VERSION 5.7 ;
  NOWIREEXTENSIONATPIN ON ;
  DIVIDERCHAR "/" ;
  BUSBITCHARS "[]" ;
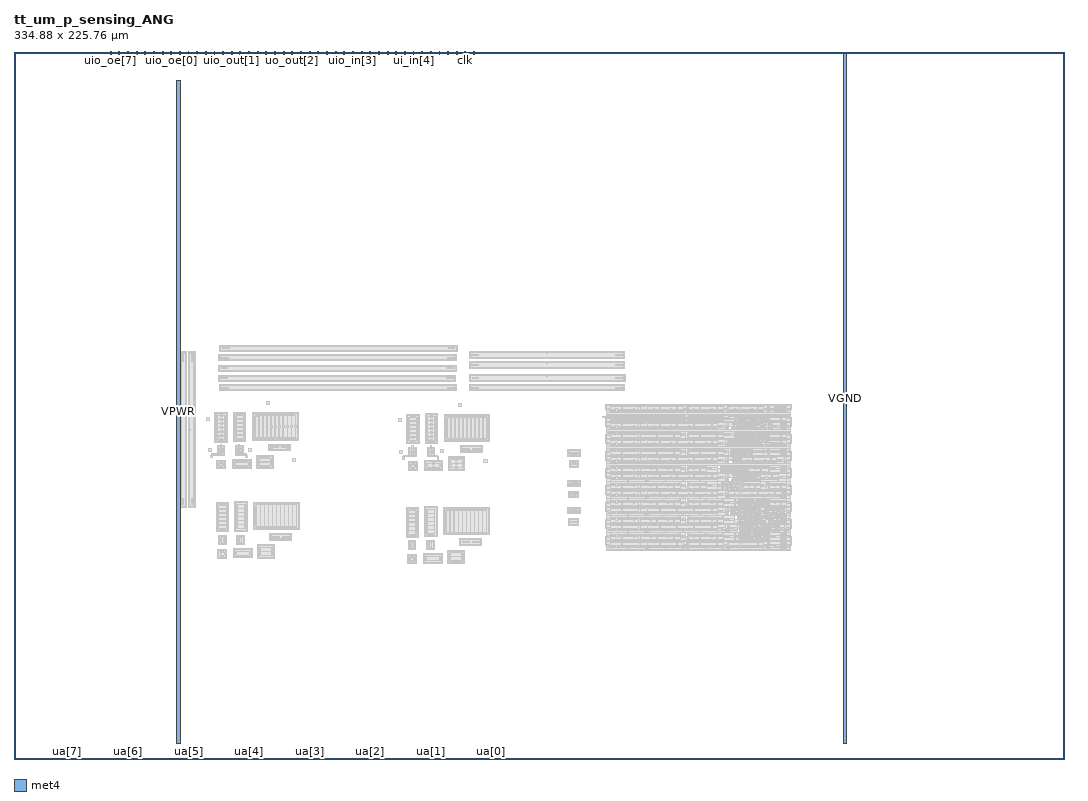
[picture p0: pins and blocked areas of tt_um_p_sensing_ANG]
MACRO tt_um_p_sensing_ANG
  CLASS BLOCK ;
  FOREIGN tt_um_p_sensing_ANG ;
  ORIGIN 0.000 0.000 ;
  SIZE 334.880 BY 225.760 ;
  PIN clk
    DIRECTION INPUT ;
    USE SIGNAL ;
    ANTENNAGATEAREA 0.852000 ;
    PORT
      LAYER met4 ;
        RECT 143.830 224.760 144.130 225.760 ;
    END
  END clk
  PIN ena
    DIRECTION INPUT ;
    USE SIGNAL ;
    PORT
      LAYER met4 ;
        RECT 146.590 224.760 146.890 225.760 ;
    END
  END ena
  PIN rst_n
    DIRECTION INPUT ;
    USE SIGNAL ;
    ANTENNAGATEAREA 0.159000 ;
    PORT
      LAYER met4 ;
        RECT 141.070 224.760 141.370 225.760 ;
    END
  END rst_n
  PIN ua[0]
    DIRECTION INOUT ;
    USE SIGNAL ;
    ANTENNAGATEAREA 0.500000 ;
    PORT
      LAYER met4 ;
        RECT 151.810 0.000 152.710 1.000 ;
    END
  END ua[0]
  PIN ua[1]
    DIRECTION INOUT ;
    USE SIGNAL ;
    ANTENNAGATEAREA 0.500000 ;
    ANTENNADIFFAREA 14.065000 ;
    PORT
      LAYER met4 ;
        RECT 132.490 0.000 133.390 1.000 ;
    END
  END ua[1]
  PIN ua[2]
    DIRECTION INOUT ;
    USE SIGNAL ;
    ANTENNADIFFAREA 13.195000 ;
    PORT
      LAYER met4 ;
        RECT 113.170 0.000 114.070 1.000 ;
    END
  END ua[2]
  PIN ua[3]
    DIRECTION INOUT ;
    USE SIGNAL ;
    ANTENNAGATEAREA 44.079998 ;
    ANTENNADIFFAREA 0.754000 ;
    PORT
      LAYER met4 ;
        RECT 93.850 0.000 94.750 1.000 ;
    END
  END ua[3]
  PIN ua[4]
    DIRECTION INOUT ;
    USE SIGNAL ;
    ANTENNAGATEAREA 0.500000 ;
    PORT
      LAYER met4 ;
        RECT 74.530 0.000 75.430 1.000 ;
    END
  END ua[4]
  PIN ua[5]
    DIRECTION INOUT ;
    USE SIGNAL ;
    ANTENNADIFFAREA 0.445500 ;
    PORT
      LAYER met4 ;
        RECT 55.210 0.000 56.110 1.000 ;
    END
  END ua[5]
  PIN ua[6]
    DIRECTION INOUT ;
    USE SIGNAL ;
    PORT
      LAYER met4 ;
        RECT 35.890 0.000 36.790 1.000 ;
    END
  END ua[6]
  PIN ua[7]
    DIRECTION INOUT ;
    USE SIGNAL ;
    PORT
      LAYER met4 ;
        RECT 16.570 0.000 17.470 1.000 ;
    END
  END ua[7]
  PIN ui_in[0]
    DIRECTION INPUT ;
    USE SIGNAL ;
    PORT
      LAYER met4 ;
        RECT 138.310 224.760 138.610 225.760 ;
    END
  END ui_in[0]
  PIN ui_in[1]
    DIRECTION INPUT ;
    USE SIGNAL ;
    PORT
      LAYER met4 ;
        RECT 135.550 224.760 135.850 225.760 ;
    END
  END ui_in[1]
  PIN ui_in[2]
    DIRECTION INPUT ;
    USE SIGNAL ;
    PORT
      LAYER met4 ;
        RECT 132.790 224.760 133.090 225.760 ;
    END
  END ui_in[2]
  PIN ui_in[3]
    DIRECTION INPUT ;
    USE SIGNAL ;
    PORT
      LAYER met4 ;
        RECT 130.030 224.760 130.330 225.760 ;
    END
  END ui_in[3]
  PIN ui_in[4]
    DIRECTION INPUT ;
    USE SIGNAL ;
    PORT
      LAYER met4 ;
        RECT 127.270 224.760 127.570 225.760 ;
    END
  END ui_in[4]
  PIN ui_in[5]
    DIRECTION INPUT ;
    USE SIGNAL ;
    PORT
      LAYER met4 ;
        RECT 124.510 224.760 124.810 225.760 ;
    END
  END ui_in[5]
  PIN ui_in[6]
    DIRECTION INPUT ;
    USE SIGNAL ;
    PORT
      LAYER met4 ;
        RECT 121.750 224.760 122.050 225.760 ;
    END
  END ui_in[6]
  PIN ui_in[7]
    DIRECTION INPUT ;
    USE SIGNAL ;
    PORT
      LAYER met4 ;
        RECT 118.990 224.760 119.290 225.760 ;
    END
  END ui_in[7]
  PIN uio_in[0]
    DIRECTION INPUT ;
    USE SIGNAL ;
    PORT
      LAYER met4 ;
        RECT 116.230 224.760 116.530 225.760 ;
    END
  END uio_in[0]
  PIN uio_in[1]
    DIRECTION INPUT ;
    USE SIGNAL ;
    PORT
      LAYER met4 ;
        RECT 113.470 224.760 113.770 225.760 ;
    END
  END uio_in[1]
  PIN uio_in[2]
    DIRECTION INPUT ;
    USE SIGNAL ;
    PORT
      LAYER met4 ;
        RECT 110.710 224.760 111.010 225.760 ;
    END
  END uio_in[2]
  PIN uio_in[3]
    DIRECTION INPUT ;
    USE SIGNAL ;
    PORT
      LAYER met4 ;
        RECT 107.950 224.760 108.250 225.760 ;
    END
  END uio_in[3]
  PIN uio_in[4]
    DIRECTION INPUT ;
    USE SIGNAL ;
    PORT
      LAYER met4 ;
        RECT 105.190 224.760 105.490 225.760 ;
    END
  END uio_in[4]
  PIN uio_in[5]
    DIRECTION INPUT ;
    USE SIGNAL ;
    PORT
      LAYER met4 ;
        RECT 102.430 224.760 102.730 225.760 ;
    END
  END uio_in[5]
  PIN uio_in[6]
    DIRECTION INPUT ;
    USE SIGNAL ;
    PORT
      LAYER met4 ;
        RECT 99.670 224.760 99.970 225.760 ;
    END
  END uio_in[6]
  PIN uio_in[7]
    DIRECTION INPUT ;
    USE SIGNAL ;
    PORT
      LAYER met4 ;
        RECT 96.910 224.760 97.210 225.760 ;
    END
  END uio_in[7]
  PIN uio_oe[0]
    DIRECTION OUTPUT ;
    USE SIGNAL ;
    ANTENNAGATEAREA 564.151489 ;
    ANTENNADIFFAREA 378.463593 ;
    PORT
      LAYER met4 ;
        RECT 49.990 224.760 50.290 225.760 ;
    END
  END uio_oe[0]
  PIN uio_oe[1]
    DIRECTION OUTPUT ;
    USE SIGNAL ;
    PORT
      LAYER met4 ;
        RECT 47.230 224.760 47.530 225.760 ;
    END
  END uio_oe[1]
  PIN uio_oe[2]
    DIRECTION OUTPUT ;
    USE SIGNAL ;
    PORT
      LAYER met4 ;
        RECT 44.470 224.760 44.770 225.760 ;
    END
  END uio_oe[2]
  PIN uio_oe[3]
    DIRECTION OUTPUT ;
    USE SIGNAL ;
    PORT
      LAYER met4 ;
        RECT 41.710 224.760 42.010 225.760 ;
    END
  END uio_oe[3]
  PIN uio_oe[4]
    DIRECTION OUTPUT ;
    USE SIGNAL ;
    PORT
      LAYER met4 ;
        RECT 38.950 224.760 39.250 225.760 ;
    END
  END uio_oe[4]
  PIN uio_oe[5]
    DIRECTION OUTPUT ;
    USE SIGNAL ;
    PORT
      LAYER met4 ;
        RECT 36.190 224.760 36.490 225.760 ;
    END
  END uio_oe[5]
  PIN uio_oe[6]
    DIRECTION OUTPUT ;
    USE SIGNAL ;
    PORT
      LAYER met4 ;
        RECT 33.430 224.760 33.730 225.760 ;
    END
  END uio_oe[6]
  PIN uio_oe[7]
    DIRECTION OUTPUT ;
    USE SIGNAL ;
    PORT
      LAYER met4 ;
        RECT 30.670 224.760 30.970 225.760 ;
    END
  END uio_oe[7]
  PIN uio_out[0]
    DIRECTION OUTPUT ;
    USE SIGNAL ;
    ANTENNAGATEAREA 564.151489 ;
    ANTENNADIFFAREA 378.463593 ;
    PORT
      LAYER met4 ;
        RECT 72.070 224.760 72.370 225.760 ;
    END
  END uio_out[0]
  PIN uio_out[1]
    DIRECTION OUTPUT ;
    USE SIGNAL ;
    PORT
      LAYER met4 ;
        RECT 69.310 224.760 69.610 225.760 ;
    END
  END uio_out[1]
  PIN uio_out[2]
    DIRECTION OUTPUT ;
    USE SIGNAL ;
    PORT
      LAYER met4 ;
        RECT 66.550 224.760 66.850 225.760 ;
    END
  END uio_out[2]
  PIN uio_out[3]
    DIRECTION OUTPUT ;
    USE SIGNAL ;
    PORT
      LAYER met4 ;
        RECT 63.790 224.760 64.090 225.760 ;
    END
  END uio_out[3]
  PIN uio_out[4]
    DIRECTION OUTPUT ;
    USE SIGNAL ;
    PORT
      LAYER met4 ;
        RECT 61.030 224.760 61.330 225.760 ;
    END
  END uio_out[4]
  PIN uio_out[5]
    DIRECTION OUTPUT ;
    USE SIGNAL ;
    PORT
      LAYER met4 ;
        RECT 58.270 224.760 58.570 225.760 ;
    END
  END uio_out[5]
  PIN uio_out[6]
    DIRECTION OUTPUT ;
    USE SIGNAL ;
    PORT
      LAYER met4 ;
        RECT 55.510 224.760 55.810 225.760 ;
    END
  END uio_out[6]
  PIN uio_out[7]
    DIRECTION OUTPUT ;
    USE SIGNAL ;
    PORT
      LAYER met4 ;
        RECT 52.750 224.760 53.050 225.760 ;
    END
  END uio_out[7]
  PIN uo_out[0]
    DIRECTION OUTPUT ;
    USE SIGNAL ;
    ANTENNAGATEAREA 564.151489 ;
    ANTENNADIFFAREA 378.463593 ;
    PORT
      LAYER met4 ;
        RECT 94.150 224.760 94.450 225.760 ;
    END
  END uo_out[0]
  PIN uo_out[1]
    DIRECTION OUTPUT ;
    USE SIGNAL ;
    ANTENNAGATEAREA 564.151489 ;
    ANTENNADIFFAREA 378.463593 ;
    PORT
      LAYER met4 ;
        RECT 91.390 224.760 91.690 225.760 ;
    END
  END uo_out[1]
  PIN uo_out[2]
    DIRECTION OUTPUT ;
    USE SIGNAL ;
    PORT
      LAYER met4 ;
        RECT 88.630 224.760 88.930 225.760 ;
    END
  END uo_out[2]
  PIN uo_out[3]
    DIRECTION OUTPUT ;
    USE SIGNAL ;
    PORT
      LAYER met4 ;
        RECT 85.870 224.760 86.170 225.760 ;
    END
  END uo_out[3]
  PIN uo_out[4]
    DIRECTION OUTPUT ;
    USE SIGNAL ;
    PORT
      LAYER met4 ;
        RECT 83.110 224.760 83.410 225.760 ;
    END
  END uo_out[4]
  PIN uo_out[5]
    DIRECTION OUTPUT ;
    USE SIGNAL ;
    PORT
      LAYER met4 ;
        RECT 80.350 224.760 80.650 225.760 ;
    END
  END uo_out[5]
  PIN uo_out[6]
    DIRECTION OUTPUT ;
    USE SIGNAL ;
    PORT
      LAYER met4 ;
        RECT 77.590 224.760 77.890 225.760 ;
    END
  END uo_out[6]
  PIN uo_out[7]
    DIRECTION OUTPUT ;
    USE SIGNAL ;
    PORT
      LAYER met4 ;
        RECT 74.830 224.760 75.130 225.760 ;
    END
  END uo_out[7]
  PIN VPWR
    DIRECTION INOUT ;
    USE POWER ;
    PORT
      LAYER met4 ;
        RECT 51.900 5.000 53.100 216.500 ;
    END
  END VPWR
  PIN VGND
    DIRECTION INOUT ;
    USE GROUND ;
    PORT
      LAYER met4 ;
        RECT 264.400 5.000 265.600 225.000 ;
    END
  END VGND
  OBS
      LAYER pwell ;
        RECT 65.610 129.960 141.430 131.970 ;
        RECT 52.995 80.190 55.005 129.810 ;
        RECT 55.745 80.190 57.755 129.810 ;
        RECT 65.370 127.010 141.190 129.020 ;
        RECT 145.150 127.840 194.770 129.850 ;
        RECT 65.250 123.590 141.070 125.600 ;
        RECT 145.150 124.650 194.770 126.660 ;
        RECT 65.140 120.400 140.960 122.410 ;
        RECT 145.270 120.520 194.890 122.530 ;
        RECT 65.440 117.430 141.260 119.440 ;
        RECT 145.150 117.450 194.770 119.460 ;
      LAYER nwell ;
        RECT 188.740 111.565 248.000 113.170 ;
        RECT 64.100 100.980 68.120 110.390 ;
        RECT 69.970 101.180 73.990 110.590 ;
        RECT 76.040 101.710 90.610 110.400 ;
      LAYER pwell ;
        RECT 188.935 110.365 190.305 111.175 ;
        RECT 190.315 110.365 195.825 111.175 ;
        RECT 195.835 110.365 201.345 111.175 ;
        RECT 201.825 110.450 202.255 111.235 ;
        RECT 202.275 110.365 207.785 111.175 ;
        RECT 207.795 110.365 213.305 111.175 ;
        RECT 213.315 110.365 214.685 111.175 ;
        RECT 214.705 110.450 215.135 111.235 ;
        RECT 215.155 110.365 220.665 111.175 ;
        RECT 220.675 110.365 226.185 111.175 ;
        RECT 226.195 110.365 227.565 111.175 ;
        RECT 227.585 110.450 228.015 111.235 ;
        RECT 228.035 110.365 233.545 111.175 ;
        RECT 233.555 110.365 239.065 111.175 ;
        RECT 239.075 110.365 240.445 111.175 ;
        RECT 240.465 110.450 240.895 111.235 ;
        RECT 240.915 110.365 242.745 111.175 ;
        RECT 243.240 111.045 244.585 111.275 ;
        RECT 245.080 111.045 246.425 111.275 ;
        RECT 242.755 110.365 244.585 111.045 ;
        RECT 244.595 110.365 246.425 111.045 ;
        RECT 246.435 110.365 247.805 111.175 ;
        RECT 189.075 110.155 189.245 110.365 ;
        RECT 190.455 110.155 190.625 110.365 ;
        RECT 192.295 110.155 192.465 110.345 ;
        RECT 195.975 110.175 196.145 110.365 ;
        RECT 197.815 110.155 197.985 110.345 ;
        RECT 201.490 110.205 201.610 110.315 ;
        RECT 202.415 110.175 202.585 110.365 ;
        RECT 203.335 110.155 203.505 110.345 ;
        RECT 207.935 110.175 208.105 110.365 ;
        RECT 208.855 110.155 209.025 110.345 ;
        RECT 213.455 110.175 213.625 110.365 ;
        RECT 214.370 110.205 214.490 110.315 ;
        RECT 215.295 110.155 215.465 110.365 ;
        RECT 220.815 110.155 220.985 110.365 ;
        RECT 226.335 110.155 226.505 110.365 ;
        RECT 228.175 110.175 228.345 110.365 ;
        RECT 230.015 110.155 230.185 110.345 ;
        RECT 233.695 110.175 233.865 110.365 ;
        RECT 239.215 110.175 239.385 110.365 ;
        RECT 240.135 110.155 240.305 110.345 ;
        RECT 241.055 110.155 241.225 110.365 ;
        RECT 242.895 110.175 243.065 110.365 ;
        RECT 244.735 110.175 244.905 110.365 ;
        RECT 247.495 110.155 247.665 110.365 ;
      LAYER nwell ;
        RECT 125.240 100.500 129.260 109.910 ;
        RECT 131.110 100.700 135.130 110.110 ;
        RECT 137.180 101.230 151.750 109.920 ;
      LAYER pwell ;
        RECT 188.935 109.345 190.305 110.155 ;
        RECT 190.315 109.475 192.145 110.155 ;
        RECT 190.800 109.245 192.145 109.475 ;
        RECT 192.155 109.345 197.665 110.155 ;
        RECT 197.675 109.345 203.185 110.155 ;
        RECT 203.195 109.345 208.705 110.155 ;
        RECT 208.715 109.345 214.225 110.155 ;
        RECT 214.705 109.285 215.135 110.070 ;
        RECT 215.155 109.345 220.665 110.155 ;
        RECT 220.675 109.345 226.185 110.155 ;
        RECT 226.195 109.345 229.865 110.155 ;
        RECT 229.875 109.345 231.245 110.155 ;
        RECT 231.255 109.475 240.445 110.155 ;
        RECT 231.255 109.245 232.175 109.475 ;
        RECT 235.005 109.255 235.935 109.475 ;
        RECT 240.465 109.285 240.895 110.070 ;
        RECT 240.915 109.345 246.425 110.155 ;
        RECT 246.435 109.345 247.805 110.155 ;
      LAYER nwell ;
        RECT 188.740 106.125 248.000 108.955 ;
      LAYER pwell ;
        RECT 188.935 104.925 190.305 105.735 ;
        RECT 190.315 104.925 195.825 105.735 ;
        RECT 195.835 104.925 201.345 105.735 ;
        RECT 201.825 105.010 202.255 105.795 ;
        RECT 202.275 104.925 207.785 105.735 ;
        RECT 207.795 104.925 213.305 105.735 ;
        RECT 213.315 104.925 218.825 105.735 ;
        RECT 218.835 104.925 224.345 105.735 ;
        RECT 224.355 104.925 227.105 105.735 ;
        RECT 227.585 105.010 228.015 105.795 ;
        RECT 238.250 105.605 239.170 105.835 ;
        RECT 228.955 104.925 238.060 105.605 ;
        RECT 238.250 104.925 241.715 105.605 ;
        RECT 241.835 104.925 244.585 105.735 ;
        RECT 245.080 105.605 246.425 105.835 ;
        RECT 244.595 104.925 246.425 105.605 ;
        RECT 246.435 104.925 247.805 105.735 ;
        RECT 189.075 104.715 189.245 104.925 ;
        RECT 190.455 104.715 190.625 104.925 ;
        RECT 195.975 104.715 196.145 104.925 ;
        RECT 201.495 104.875 201.665 104.905 ;
        RECT 201.490 104.765 201.665 104.875 ;
        RECT 201.495 104.715 201.665 104.765 ;
        RECT 202.415 104.735 202.585 104.925 ;
        RECT 207.015 104.715 207.185 104.905 ;
        RECT 207.935 104.735 208.105 104.925 ;
        RECT 212.535 104.715 212.705 104.905 ;
        RECT 213.455 104.735 213.625 104.925 ;
        RECT 214.370 104.765 214.490 104.875 ;
        RECT 215.295 104.715 215.465 104.905 ;
        RECT 218.975 104.735 219.145 104.925 ;
        RECT 220.815 104.715 220.985 104.905 ;
        RECT 224.495 104.735 224.665 104.925 ;
        RECT 226.335 104.715 226.505 104.905 ;
        RECT 227.250 104.765 227.370 104.875 ;
        RECT 228.185 104.770 228.345 104.880 ;
        RECT 229.095 104.735 229.265 104.925 ;
        RECT 230.015 104.715 230.185 104.905 ;
        RECT 239.215 104.715 239.385 104.905 ;
        RECT 241.055 104.715 241.225 104.905 ;
        RECT 241.515 104.735 241.685 104.925 ;
        RECT 241.975 104.735 242.145 104.925 ;
        RECT 244.735 104.735 244.905 104.925 ;
        RECT 247.495 104.715 247.665 104.925 ;
        RECT 188.935 103.905 190.305 104.715 ;
        RECT 190.315 103.905 195.825 104.715 ;
        RECT 195.835 103.905 201.345 104.715 ;
        RECT 201.355 103.905 206.865 104.715 ;
        RECT 206.875 103.905 212.385 104.715 ;
        RECT 212.395 103.905 214.225 104.715 ;
        RECT 214.705 103.845 215.135 104.630 ;
        RECT 215.155 103.905 220.665 104.715 ;
        RECT 220.675 103.905 226.185 104.715 ;
        RECT 226.195 103.905 229.865 104.715 ;
        RECT 229.875 104.035 239.065 104.715 ;
        RECT 234.385 103.815 235.315 104.035 ;
        RECT 238.145 103.805 239.065 104.035 ;
        RECT 239.075 103.935 240.445 104.715 ;
        RECT 240.465 103.845 240.895 104.630 ;
        RECT 240.915 103.905 246.425 104.715 ;
        RECT 246.435 103.905 247.805 104.715 ;
      LAYER nwell ;
        RECT 188.740 100.685 248.000 103.515 ;
      LAYER pwell ;
        RECT 64.770 96.840 67.230 99.940 ;
        RECT 70.580 96.840 73.040 99.940 ;
        RECT 81.250 98.370 88.240 100.380 ;
        RECT 64.570 92.580 67.530 95.330 ;
        RECT 69.640 92.640 75.610 95.600 ;
        RECT 77.310 92.570 82.660 96.820 ;
        RECT 125.910 96.360 128.370 99.460 ;
        RECT 131.720 96.360 134.180 99.460 ;
        RECT 142.390 97.890 149.380 99.900 ;
        RECT 188.935 99.485 190.305 100.295 ;
        RECT 190.315 99.485 195.825 100.295 ;
        RECT 195.835 99.485 201.345 100.295 ;
        RECT 201.825 99.570 202.255 100.355 ;
        RECT 202.275 99.485 207.785 100.295 ;
        RECT 207.795 99.485 213.305 100.295 ;
        RECT 213.315 99.485 218.825 100.295 ;
        RECT 218.835 99.485 224.345 100.295 ;
        RECT 224.355 99.485 227.105 100.295 ;
        RECT 227.585 99.570 228.015 100.355 ;
        RECT 228.035 100.165 228.955 100.395 ;
        RECT 231.785 100.165 232.715 100.385 ;
        RECT 237.330 100.165 238.250 100.395 ;
        RECT 228.035 99.485 237.225 100.165 ;
        RECT 237.330 99.485 240.795 100.165 ;
        RECT 240.915 99.485 246.425 100.295 ;
        RECT 246.435 99.485 247.805 100.295 ;
        RECT 189.075 99.275 189.245 99.485 ;
        RECT 190.455 99.275 190.625 99.485 ;
        RECT 195.975 99.275 196.145 99.485 ;
        RECT 201.495 99.435 201.665 99.465 ;
        RECT 201.490 99.325 201.665 99.435 ;
        RECT 201.495 99.275 201.665 99.325 ;
        RECT 202.415 99.295 202.585 99.485 ;
        RECT 207.015 99.275 207.185 99.465 ;
        RECT 207.935 99.295 208.105 99.485 ;
        RECT 212.535 99.275 212.705 99.465 ;
        RECT 213.455 99.295 213.625 99.485 ;
        RECT 214.370 99.325 214.490 99.435 ;
        RECT 215.295 99.275 215.465 99.465 ;
        RECT 218.975 99.295 219.145 99.485 ;
        RECT 220.815 99.275 220.985 99.465 ;
        RECT 224.495 99.295 224.665 99.485 ;
        RECT 226.335 99.275 226.505 99.465 ;
        RECT 227.250 99.325 227.370 99.435 ;
        RECT 228.170 99.325 228.290 99.435 ;
        RECT 231.395 99.275 231.565 99.465 ;
        RECT 231.855 99.275 232.025 99.465 ;
        RECT 235.535 99.275 235.705 99.465 ;
        RECT 236.915 99.295 237.085 99.485 ;
        RECT 239.215 99.275 239.385 99.465 ;
        RECT 240.595 99.295 240.765 99.485 ;
        RECT 241.055 99.275 241.225 99.485 ;
        RECT 244.735 99.275 244.905 99.465 ;
        RECT 247.495 99.275 247.665 99.485 ;
      LAYER nwell ;
        RECT 176.540 96.490 180.730 98.600 ;
      LAYER pwell ;
        RECT 188.935 98.465 190.305 99.275 ;
        RECT 190.315 98.465 195.825 99.275 ;
        RECT 195.835 98.465 201.345 99.275 ;
        RECT 201.355 98.465 206.865 99.275 ;
        RECT 206.875 98.465 212.385 99.275 ;
        RECT 212.395 98.465 214.225 99.275 ;
        RECT 214.705 98.405 215.135 99.190 ;
        RECT 215.155 98.465 220.665 99.275 ;
        RECT 220.675 98.465 226.185 99.275 ;
        RECT 226.195 98.465 228.025 99.275 ;
        RECT 228.495 98.365 231.605 99.275 ;
        RECT 231.825 98.595 235.290 99.275 ;
        RECT 234.370 98.365 235.290 98.595 ;
        RECT 235.395 98.465 239.065 99.275 ;
        RECT 239.075 98.465 240.445 99.275 ;
        RECT 240.465 98.405 240.895 99.190 ;
        RECT 240.915 98.465 244.585 99.275 ;
        RECT 244.595 98.595 246.425 99.275 ;
        RECT 245.080 98.365 246.425 98.595 ;
        RECT 246.435 98.465 247.805 99.275 ;
        RECT 125.710 92.100 128.670 94.850 ;
        RECT 130.780 92.160 136.750 95.120 ;
        RECT 138.450 92.090 143.800 96.340 ;
      LAYER nwell ;
        RECT 188.740 95.245 248.000 98.075 ;
      LAYER pwell ;
        RECT 177.040 93.070 180.140 95.180 ;
        RECT 188.935 94.045 190.305 94.855 ;
        RECT 190.315 94.045 195.825 94.855 ;
        RECT 195.835 94.045 201.345 94.855 ;
        RECT 201.825 94.130 202.255 94.915 ;
        RECT 202.275 94.045 207.785 94.855 ;
        RECT 207.795 94.045 213.305 94.855 ;
        RECT 213.315 94.045 218.825 94.855 ;
        RECT 218.835 94.045 224.345 94.855 ;
        RECT 224.355 94.045 227.105 94.855 ;
        RECT 227.585 94.130 228.015 94.915 ;
        RECT 229.055 94.045 232.165 94.955 ;
        RECT 232.175 94.045 237.685 94.855 ;
        RECT 237.695 94.045 243.205 94.855 ;
        RECT 243.215 94.045 245.965 94.855 ;
        RECT 246.435 94.045 247.805 94.855 ;
        RECT 189.075 93.835 189.245 94.045 ;
        RECT 190.455 93.835 190.625 94.045 ;
        RECT 195.975 93.835 196.145 94.045 ;
        RECT 201.495 93.995 201.665 94.025 ;
        RECT 201.490 93.885 201.665 93.995 ;
        RECT 201.495 93.835 201.665 93.885 ;
        RECT 202.415 93.855 202.585 94.045 ;
        RECT 207.015 93.835 207.185 94.025 ;
        RECT 207.935 93.855 208.105 94.045 ;
        RECT 212.535 93.835 212.705 94.025 ;
        RECT 213.455 93.855 213.625 94.045 ;
        RECT 214.370 93.885 214.490 93.995 ;
        RECT 215.295 93.835 215.465 94.025 ;
        RECT 218.975 93.855 219.145 94.045 ;
        RECT 220.815 93.835 220.985 94.025 ;
        RECT 224.495 93.855 224.665 94.045 ;
        RECT 227.250 93.885 227.370 93.995 ;
        RECT 228.185 93.890 228.345 94.000 ;
        RECT 229.095 93.855 229.265 94.045 ;
        RECT 232.315 93.855 232.485 94.045 ;
        RECT 234.155 93.835 234.325 94.025 ;
        RECT 234.615 93.835 234.785 94.025 ;
        RECT 237.835 93.855 238.005 94.045 ;
        RECT 240.130 93.885 240.250 93.995 ;
        RECT 241.055 93.835 241.225 94.025 ;
        RECT 243.355 93.855 243.525 94.045 ;
        RECT 244.735 93.835 244.905 94.025 ;
        RECT 246.110 93.885 246.230 93.995 ;
        RECT 247.495 93.835 247.665 94.045 ;
        RECT 188.935 93.025 190.305 93.835 ;
        RECT 190.315 93.025 195.825 93.835 ;
        RECT 195.835 93.025 201.345 93.835 ;
        RECT 201.355 93.025 206.865 93.835 ;
        RECT 206.875 93.025 212.385 93.835 ;
        RECT 212.395 93.025 214.225 93.835 ;
        RECT 214.705 92.965 215.135 93.750 ;
        RECT 215.155 93.025 220.665 93.835 ;
        RECT 220.675 93.025 224.345 93.835 ;
        RECT 225.275 93.155 234.465 93.835 ;
        RECT 225.275 92.925 226.195 93.155 ;
        RECT 229.025 92.935 229.955 93.155 ;
        RECT 234.475 93.025 239.985 93.835 ;
        RECT 240.465 92.965 240.895 93.750 ;
        RECT 240.915 93.025 244.585 93.835 ;
        RECT 244.595 93.155 246.425 93.835 ;
        RECT 245.080 92.925 246.425 93.155 ;
        RECT 246.435 93.025 247.805 93.835 ;
      LAYER nwell ;
        RECT 188.740 89.805 248.000 92.635 ;
        RECT 176.580 86.750 180.770 88.860 ;
      LAYER pwell ;
        RECT 188.935 88.605 190.305 89.415 ;
        RECT 190.315 88.605 195.825 89.415 ;
        RECT 195.835 88.605 201.345 89.415 ;
        RECT 201.825 88.690 202.255 89.475 ;
        RECT 202.275 88.605 207.785 89.415 ;
        RECT 207.795 88.605 213.305 89.415 ;
        RECT 213.315 88.605 218.825 89.415 ;
        RECT 218.835 88.605 224.345 89.415 ;
        RECT 224.355 88.605 227.105 89.415 ;
        RECT 227.585 88.690 228.015 89.475 ;
        RECT 228.955 88.605 238.060 89.285 ;
        RECT 238.155 88.605 243.665 89.415 ;
        RECT 243.675 88.605 246.425 89.415 ;
        RECT 246.435 88.605 247.805 89.415 ;
        RECT 189.075 88.395 189.245 88.605 ;
        RECT 190.455 88.395 190.625 88.605 ;
        RECT 195.975 88.395 196.145 88.605 ;
        RECT 201.495 88.555 201.665 88.585 ;
        RECT 201.490 88.445 201.665 88.555 ;
        RECT 201.495 88.395 201.665 88.445 ;
        RECT 202.415 88.415 202.585 88.605 ;
        RECT 207.015 88.395 207.185 88.585 ;
        RECT 207.935 88.415 208.105 88.605 ;
        RECT 212.535 88.395 212.705 88.585 ;
        RECT 213.455 88.415 213.625 88.605 ;
        RECT 214.370 88.445 214.490 88.555 ;
        RECT 215.295 88.395 215.465 88.585 ;
        RECT 218.975 88.415 219.145 88.605 ;
        RECT 220.815 88.395 220.985 88.585 ;
        RECT 224.495 88.395 224.665 88.605 ;
        RECT 225.875 88.395 226.045 88.585 ;
        RECT 227.250 88.445 227.370 88.555 ;
        RECT 228.185 88.450 228.345 88.560 ;
        RECT 229.095 88.395 229.265 88.605 ;
        RECT 232.775 88.395 232.945 88.585 ;
        RECT 238.295 88.395 238.465 88.605 ;
        RECT 240.130 88.445 240.250 88.555 ;
        RECT 241.055 88.395 241.225 88.585 ;
        RECT 243.815 88.415 243.985 88.605 ;
        RECT 247.495 88.395 247.665 88.605 ;
        RECT 188.935 87.585 190.305 88.395 ;
        RECT 190.315 87.585 195.825 88.395 ;
        RECT 195.835 87.585 201.345 88.395 ;
        RECT 201.355 87.585 206.865 88.395 ;
        RECT 206.875 87.585 212.385 88.395 ;
        RECT 212.395 87.585 214.225 88.395 ;
        RECT 214.705 87.525 215.135 88.310 ;
        RECT 215.155 87.585 220.665 88.395 ;
        RECT 220.675 87.585 224.345 88.395 ;
        RECT 224.355 87.585 225.725 88.395 ;
        RECT 225.775 87.485 228.945 88.395 ;
        RECT 229.065 87.715 232.530 88.395 ;
        RECT 231.610 87.485 232.530 87.715 ;
        RECT 232.635 87.585 238.145 88.395 ;
        RECT 238.155 87.585 239.985 88.395 ;
        RECT 240.465 87.525 240.895 88.310 ;
        RECT 240.915 87.585 246.425 88.395 ;
        RECT 246.435 87.585 247.805 88.395 ;
        RECT 177.000 83.330 180.100 85.440 ;
      LAYER nwell ;
        RECT 188.740 84.365 248.000 87.195 ;
      LAYER pwell ;
        RECT 188.935 83.165 190.305 83.975 ;
        RECT 190.315 83.165 195.825 83.975 ;
        RECT 195.835 83.165 201.345 83.975 ;
        RECT 201.825 83.250 202.255 84.035 ;
        RECT 202.275 83.165 207.785 83.975 ;
        RECT 207.795 83.165 213.305 83.975 ;
        RECT 213.315 83.165 218.825 83.975 ;
        RECT 218.835 83.165 224.345 83.975 ;
        RECT 224.355 83.165 227.105 83.975 ;
        RECT 227.585 83.250 228.015 84.035 ;
        RECT 228.035 83.165 233.545 83.975 ;
        RECT 233.555 83.165 239.065 83.975 ;
        RECT 239.075 83.165 244.585 83.975 ;
        RECT 245.080 83.845 246.425 84.075 ;
        RECT 244.595 83.165 246.425 83.845 ;
        RECT 246.435 83.165 247.805 83.975 ;
        RECT 189.075 82.955 189.245 83.165 ;
        RECT 190.455 82.955 190.625 83.165 ;
        RECT 195.975 82.955 196.145 83.165 ;
        RECT 201.495 83.115 201.665 83.145 ;
        RECT 201.490 83.005 201.665 83.115 ;
        RECT 201.495 82.955 201.665 83.005 ;
        RECT 202.415 82.975 202.585 83.165 ;
        RECT 207.015 82.955 207.185 83.145 ;
        RECT 207.935 82.975 208.105 83.165 ;
        RECT 212.535 82.955 212.705 83.145 ;
        RECT 213.455 82.975 213.625 83.165 ;
        RECT 214.370 83.005 214.490 83.115 ;
        RECT 215.295 82.955 215.465 83.145 ;
        RECT 218.975 82.975 219.145 83.165 ;
        RECT 220.815 82.955 220.985 83.145 ;
        RECT 224.495 82.975 224.665 83.165 ;
        RECT 226.335 82.955 226.505 83.145 ;
        RECT 227.250 83.005 227.370 83.115 ;
        RECT 228.175 82.975 228.345 83.165 ;
        RECT 230.015 82.955 230.185 83.145 ;
        RECT 233.695 82.975 233.865 83.165 ;
        RECT 239.215 82.975 239.385 83.165 ;
        RECT 240.135 82.955 240.305 83.145 ;
        RECT 241.055 82.955 241.225 83.145 ;
        RECT 244.735 82.975 244.905 83.165 ;
        RECT 247.495 82.955 247.665 83.165 ;
        RECT 188.935 82.145 190.305 82.955 ;
        RECT 190.315 82.145 195.825 82.955 ;
        RECT 195.835 82.145 201.345 82.955 ;
        RECT 201.355 82.145 206.865 82.955 ;
        RECT 206.875 82.145 212.385 82.955 ;
        RECT 212.395 82.145 214.225 82.955 ;
        RECT 214.705 82.085 215.135 82.870 ;
        RECT 215.155 82.145 220.665 82.955 ;
        RECT 220.675 82.145 226.185 82.955 ;
        RECT 226.195 82.145 229.865 82.955 ;
        RECT 229.875 82.145 231.245 82.955 ;
        RECT 231.255 82.275 240.445 82.955 ;
      LAYER nwell ;
        RECT 64.490 72.450 68.510 81.860 ;
        RECT 70.360 72.650 74.380 82.060 ;
      LAYER pwell ;
        RECT 231.255 82.045 232.175 82.275 ;
        RECT 235.005 82.055 235.935 82.275 ;
        RECT 240.465 82.085 240.895 82.870 ;
        RECT 240.915 82.145 246.425 82.955 ;
        RECT 246.435 82.145 247.805 82.955 ;
      LAYER nwell ;
        RECT 76.430 73.180 91.000 81.870 ;
      LAYER pwell ;
        RECT 65.160 68.310 67.620 71.410 ;
        RECT 70.970 68.310 73.430 71.410 ;
        RECT 81.640 69.840 88.630 71.850 ;
      LAYER nwell ;
        RECT 125.050 70.800 129.070 80.210 ;
        RECT 130.920 71.000 134.940 80.410 ;
        RECT 136.990 71.530 151.560 80.220 ;
        RECT 176.440 78.190 180.630 80.300 ;
        RECT 188.740 78.925 248.000 81.755 ;
      LAYER pwell ;
        RECT 188.935 77.725 190.305 78.535 ;
        RECT 190.315 77.725 195.825 78.535 ;
        RECT 195.835 77.725 201.345 78.535 ;
        RECT 201.825 77.810 202.255 78.595 ;
        RECT 202.275 77.725 207.785 78.535 ;
        RECT 207.795 77.725 213.305 78.535 ;
        RECT 213.315 77.725 218.825 78.535 ;
        RECT 218.835 77.725 224.345 78.535 ;
        RECT 224.355 77.725 227.105 78.535 ;
        RECT 227.585 77.810 228.015 78.595 ;
        RECT 229.855 78.405 230.775 78.625 ;
        RECT 236.855 78.525 237.775 78.635 ;
        RECT 235.440 78.405 237.775 78.525 ;
        RECT 228.495 77.725 237.775 78.405 ;
        RECT 238.155 77.725 239.525 78.535 ;
        RECT 239.630 78.405 240.550 78.635 ;
        RECT 239.630 77.725 243.095 78.405 ;
        RECT 243.215 77.725 245.955 78.405 ;
        RECT 246.435 77.725 247.805 78.535 ;
        RECT 189.075 77.515 189.245 77.725 ;
        RECT 190.455 77.515 190.625 77.725 ;
        RECT 195.975 77.515 196.145 77.725 ;
        RECT 201.495 77.675 201.665 77.705 ;
        RECT 201.490 77.565 201.665 77.675 ;
        RECT 201.495 77.515 201.665 77.565 ;
        RECT 202.415 77.535 202.585 77.725 ;
        RECT 207.015 77.515 207.185 77.705 ;
        RECT 207.935 77.535 208.105 77.725 ;
        RECT 212.535 77.515 212.705 77.705 ;
        RECT 213.455 77.535 213.625 77.725 ;
        RECT 214.370 77.565 214.490 77.675 ;
        RECT 215.295 77.515 215.465 77.705 ;
        RECT 218.975 77.535 219.145 77.725 ;
        RECT 220.815 77.515 220.985 77.705 ;
        RECT 224.495 77.535 224.665 77.725 ;
        RECT 226.335 77.515 226.505 77.705 ;
        RECT 227.250 77.565 227.370 77.675 ;
        RECT 228.170 77.565 228.290 77.675 ;
        RECT 228.635 77.535 228.805 77.725 ;
        RECT 230.025 77.560 230.185 77.670 ;
        RECT 230.935 77.515 231.105 77.705 ;
        RECT 238.295 77.535 238.465 77.725 ;
        RECT 240.130 77.565 240.250 77.675 ;
        RECT 242.895 77.535 243.065 77.725 ;
        RECT 243.355 77.535 243.525 77.725 ;
        RECT 244.275 77.515 244.445 77.705 ;
        RECT 244.735 77.515 244.905 77.705 ;
        RECT 246.110 77.565 246.230 77.675 ;
        RECT 247.495 77.515 247.665 77.725 ;
        RECT 188.935 76.705 190.305 77.515 ;
        RECT 190.315 76.705 195.825 77.515 ;
        RECT 195.835 76.705 201.345 77.515 ;
        RECT 201.355 76.705 206.865 77.515 ;
        RECT 206.875 76.705 212.385 77.515 ;
        RECT 212.395 76.705 214.225 77.515 ;
        RECT 214.705 76.645 215.135 77.430 ;
        RECT 215.155 76.705 220.665 77.515 ;
        RECT 220.675 76.705 226.185 77.515 ;
        RECT 226.195 76.705 229.865 77.515 ;
        RECT 230.795 76.835 239.900 77.515 ;
        RECT 240.465 76.645 240.895 77.430 ;
        RECT 241.010 76.835 244.475 77.515 ;
        RECT 244.595 76.835 246.425 77.515 ;
        RECT 176.910 74.520 180.010 76.630 ;
        RECT 241.010 76.605 241.930 76.835 ;
        RECT 245.080 76.605 246.425 76.835 ;
        RECT 246.435 76.705 247.805 77.515 ;
      LAYER nwell ;
        RECT 188.740 73.485 248.000 76.315 ;
      LAYER pwell ;
        RECT 188.935 72.285 190.305 73.095 ;
        RECT 190.315 72.285 195.825 73.095 ;
        RECT 195.835 72.285 201.345 73.095 ;
        RECT 201.825 72.370 202.255 73.155 ;
        RECT 202.275 72.285 207.785 73.095 ;
        RECT 207.795 72.285 213.305 73.095 ;
        RECT 213.315 72.285 218.825 73.095 ;
        RECT 218.835 72.285 224.345 73.095 ;
        RECT 224.355 72.285 227.105 73.095 ;
        RECT 227.585 72.370 228.015 73.155 ;
        RECT 228.035 72.285 230.785 73.095 ;
        RECT 235.765 72.965 236.695 73.185 ;
        RECT 239.525 72.965 240.445 73.195 ;
        RECT 231.255 72.285 240.445 72.965 ;
        RECT 240.550 72.965 241.470 73.195 ;
        RECT 240.550 72.285 244.015 72.965 ;
        RECT 244.135 72.285 245.965 73.095 ;
        RECT 246.435 72.285 247.805 73.095 ;
        RECT 189.075 72.075 189.245 72.285 ;
        RECT 190.455 72.075 190.625 72.285 ;
        RECT 195.975 72.075 196.145 72.285 ;
        RECT 201.495 72.235 201.665 72.265 ;
        RECT 201.490 72.125 201.665 72.235 ;
        RECT 201.495 72.075 201.665 72.125 ;
        RECT 202.415 72.095 202.585 72.285 ;
        RECT 207.015 72.075 207.185 72.265 ;
        RECT 207.935 72.095 208.105 72.285 ;
        RECT 212.535 72.075 212.705 72.265 ;
        RECT 213.455 72.095 213.625 72.285 ;
        RECT 214.370 72.125 214.490 72.235 ;
        RECT 215.295 72.075 215.465 72.265 ;
        RECT 218.975 72.095 219.145 72.285 ;
        RECT 220.815 72.075 220.985 72.265 ;
        RECT 224.495 72.095 224.665 72.285 ;
        RECT 226.335 72.075 226.505 72.265 ;
        RECT 227.250 72.125 227.370 72.235 ;
        RECT 228.175 72.095 228.345 72.285 ;
        RECT 230.015 72.075 230.185 72.265 ;
        RECT 230.930 72.125 231.050 72.235 ;
        RECT 231.395 72.075 231.565 72.285 ;
        RECT 241.055 72.075 241.225 72.265 ;
        RECT 243.815 72.095 243.985 72.285 ;
        RECT 244.275 72.095 244.445 72.285 ;
        RECT 244.735 72.075 244.905 72.265 ;
        RECT 246.110 72.125 246.230 72.235 ;
        RECT 247.495 72.075 247.665 72.285 ;
        RECT 188.935 71.265 190.305 72.075 ;
        RECT 190.315 71.265 195.825 72.075 ;
        RECT 195.835 71.265 201.345 72.075 ;
        RECT 201.355 71.265 206.865 72.075 ;
        RECT 206.875 71.265 212.385 72.075 ;
        RECT 212.395 71.265 214.225 72.075 ;
        RECT 214.705 71.205 215.135 71.990 ;
        RECT 215.155 71.265 220.665 72.075 ;
        RECT 220.675 71.265 226.185 72.075 ;
        RECT 226.195 71.265 229.865 72.075 ;
        RECT 229.875 71.265 231.245 72.075 ;
        RECT 231.255 71.395 240.445 72.075 ;
        RECT 235.765 71.175 236.695 71.395 ;
        RECT 239.525 71.165 240.445 71.395 ;
        RECT 240.465 71.205 240.895 71.990 ;
        RECT 240.915 71.265 244.585 72.075 ;
        RECT 244.595 71.395 246.425 72.075 ;
        RECT 245.080 71.165 246.425 71.395 ;
        RECT 246.435 71.265 247.805 72.075 ;
        RECT 64.960 64.050 67.920 66.800 ;
        RECT 70.030 64.110 76.000 67.070 ;
        RECT 77.700 64.040 83.050 68.290 ;
        RECT 125.720 66.660 128.180 69.760 ;
        RECT 131.530 66.660 133.990 69.760 ;
        RECT 142.200 68.190 149.190 70.200 ;
      LAYER nwell ;
        RECT 188.740 68.045 248.000 70.875 ;
      LAYER pwell ;
        RECT 188.935 66.845 190.305 67.655 ;
        RECT 190.315 66.845 195.825 67.655 ;
        RECT 195.835 66.845 201.345 67.655 ;
        RECT 201.825 66.930 202.255 67.715 ;
        RECT 202.275 66.845 207.785 67.655 ;
        RECT 207.795 66.845 213.305 67.655 ;
        RECT 213.315 66.845 214.685 67.655 ;
        RECT 214.705 66.930 215.135 67.715 ;
        RECT 215.155 66.845 220.665 67.655 ;
        RECT 220.675 66.845 226.185 67.655 ;
        RECT 226.195 66.845 227.565 67.655 ;
        RECT 227.585 66.930 228.015 67.715 ;
        RECT 228.035 66.845 233.545 67.655 ;
        RECT 233.555 66.845 239.065 67.655 ;
        RECT 239.075 66.845 240.445 67.655 ;
        RECT 240.465 66.930 240.895 67.715 ;
        RECT 240.915 66.845 244.585 67.655 ;
        RECT 245.080 67.525 246.425 67.755 ;
        RECT 244.595 66.845 246.425 67.525 ;
        RECT 246.435 66.845 247.805 67.655 ;
        RECT 189.075 66.655 189.245 66.845 ;
        RECT 190.455 66.655 190.625 66.845 ;
        RECT 195.975 66.655 196.145 66.845 ;
        RECT 201.490 66.685 201.610 66.795 ;
        RECT 202.415 66.655 202.585 66.845 ;
        RECT 207.935 66.655 208.105 66.845 ;
        RECT 213.455 66.655 213.625 66.845 ;
        RECT 215.295 66.655 215.465 66.845 ;
        RECT 220.815 66.655 220.985 66.845 ;
        RECT 226.335 66.655 226.505 66.845 ;
        RECT 228.175 66.655 228.345 66.845 ;
        RECT 233.695 66.655 233.865 66.845 ;
        RECT 239.215 66.655 239.385 66.845 ;
        RECT 241.055 66.655 241.225 66.845 ;
        RECT 244.735 66.655 244.905 66.845 ;
        RECT 247.495 66.655 247.665 66.845 ;
        RECT 125.520 62.400 128.480 65.150 ;
        RECT 130.590 62.460 136.560 65.420 ;
        RECT 138.260 62.390 143.610 66.640 ;
      LAYER li1 ;
        RECT 65.790 131.620 141.250 131.790 ;
        RECT 65.790 130.310 65.960 131.620 ;
        RECT 66.440 130.790 68.600 131.140 ;
        RECT 138.440 130.790 140.600 131.140 ;
        RECT 141.080 130.310 141.250 131.620 ;
        RECT 65.790 130.140 141.250 130.310 ;
        RECT 53.175 129.460 54.825 129.630 ;
        RECT 53.175 80.540 53.345 129.460 ;
        RECT 53.825 126.820 54.175 128.980 ;
        RECT 53.825 81.020 54.175 83.180 ;
        RECT 54.655 80.540 54.825 129.460 ;
        RECT 53.175 80.370 54.825 80.540 ;
        RECT 55.925 129.460 57.575 129.630 ;
        RECT 55.925 80.540 56.095 129.460 ;
        RECT 56.575 126.820 56.925 128.980 ;
        RECT 56.575 81.020 56.925 83.180 ;
        RECT 57.405 80.540 57.575 129.460 ;
        RECT 145.330 129.500 194.590 129.670 ;
        RECT 65.550 128.670 141.010 128.840 ;
        RECT 65.550 127.360 65.720 128.670 ;
        RECT 66.200 127.840 68.360 128.190 ;
        RECT 138.200 127.840 140.360 128.190 ;
        RECT 140.840 127.360 141.010 128.670 ;
        RECT 145.330 128.190 145.500 129.500 ;
        RECT 145.980 128.670 148.140 129.020 ;
        RECT 191.780 128.670 193.940 129.020 ;
        RECT 194.420 128.190 194.590 129.500 ;
        RECT 145.330 128.020 194.590 128.190 ;
        RECT 65.550 127.190 141.010 127.360 ;
        RECT 145.330 126.310 194.590 126.480 ;
        RECT 65.430 125.250 140.890 125.420 ;
        RECT 65.430 123.940 65.600 125.250 ;
        RECT 66.080 124.420 68.240 124.770 ;
        RECT 138.080 124.420 140.240 124.770 ;
        RECT 140.720 123.940 140.890 125.250 ;
        RECT 145.330 125.000 145.500 126.310 ;
        RECT 145.980 125.480 148.140 125.830 ;
        RECT 191.780 125.480 193.940 125.830 ;
        RECT 194.420 125.000 194.590 126.310 ;
        RECT 145.330 124.830 194.590 125.000 ;
        RECT 65.430 123.770 140.890 123.940 ;
        RECT 65.320 122.060 140.780 122.230 ;
        RECT 65.320 120.750 65.490 122.060 ;
        RECT 65.970 121.230 68.130 121.580 ;
        RECT 137.970 121.230 140.130 121.580 ;
        RECT 140.610 120.750 140.780 122.060 ;
        RECT 65.320 120.580 140.780 120.750 ;
        RECT 145.450 122.180 194.710 122.350 ;
        RECT 145.450 120.870 145.620 122.180 ;
        RECT 146.100 121.350 148.260 121.700 ;
        RECT 191.900 121.350 194.060 121.700 ;
        RECT 194.540 120.870 194.710 122.180 ;
        RECT 145.450 120.700 194.710 120.870 ;
        RECT 65.620 119.090 141.080 119.260 ;
        RECT 65.620 117.780 65.790 119.090 ;
        RECT 66.270 118.260 68.430 118.610 ;
        RECT 138.270 118.260 140.430 118.610 ;
        RECT 140.910 117.780 141.080 119.090 ;
        RECT 65.620 117.610 141.080 117.780 ;
        RECT 145.330 119.110 194.590 119.280 ;
        RECT 145.330 117.800 145.500 119.110 ;
        RECT 145.980 118.280 148.140 118.630 ;
        RECT 191.780 118.280 193.940 118.630 ;
        RECT 194.420 117.800 194.590 119.110 ;
        RECT 145.330 117.630 194.590 117.800 ;
        RECT 188.930 112.895 247.810 113.065 ;
        RECT 189.015 111.805 190.225 112.895 ;
        RECT 190.395 112.460 195.740 112.895 ;
        RECT 195.915 112.460 201.260 112.895 ;
        RECT 189.015 111.095 189.535 111.635 ;
        RECT 189.705 111.265 190.225 111.805 ;
        RECT 70.150 110.240 73.810 110.410 ;
        RECT 189.015 110.345 190.225 111.095 ;
        RECT 191.980 110.890 192.320 111.720 ;
        RECT 193.800 111.210 194.150 112.460 ;
        RECT 197.500 110.890 197.840 111.720 ;
        RECT 199.320 111.210 199.670 112.460 ;
        RECT 201.895 111.730 202.185 112.895 ;
        RECT 202.355 112.460 207.700 112.895 ;
        RECT 207.875 112.460 213.220 112.895 ;
        RECT 190.395 110.345 195.740 110.890 ;
        RECT 195.915 110.345 201.260 110.890 ;
        RECT 201.895 110.345 202.185 111.070 ;
        RECT 203.940 110.890 204.280 111.720 ;
        RECT 205.760 111.210 206.110 112.460 ;
        RECT 209.460 110.890 209.800 111.720 ;
        RECT 211.280 111.210 211.630 112.460 ;
        RECT 213.395 111.805 214.605 112.895 ;
        RECT 213.395 111.095 213.915 111.635 ;
        RECT 214.085 111.265 214.605 111.805 ;
        RECT 214.775 111.730 215.065 112.895 ;
        RECT 215.235 112.460 220.580 112.895 ;
        RECT 220.755 112.460 226.100 112.895 ;
        RECT 202.355 110.345 207.700 110.890 ;
        RECT 207.875 110.345 213.220 110.890 ;
        RECT 213.395 110.345 214.605 111.095 ;
        RECT 214.775 110.345 215.065 111.070 ;
        RECT 216.820 110.890 217.160 111.720 ;
        RECT 218.640 111.210 218.990 112.460 ;
        RECT 222.340 110.890 222.680 111.720 ;
        RECT 224.160 111.210 224.510 112.460 ;
        RECT 226.275 111.805 227.485 112.895 ;
        RECT 226.275 111.095 226.795 111.635 ;
        RECT 226.965 111.265 227.485 111.805 ;
        RECT 227.655 111.730 227.945 112.895 ;
        RECT 228.115 112.460 233.460 112.895 ;
        RECT 233.635 112.460 238.980 112.895 ;
        RECT 215.235 110.345 220.580 110.890 ;
        RECT 220.755 110.345 226.100 110.890 ;
        RECT 226.275 110.345 227.485 111.095 ;
        RECT 227.655 110.345 227.945 111.070 ;
        RECT 229.700 110.890 230.040 111.720 ;
        RECT 231.520 111.210 231.870 112.460 ;
        RECT 235.220 110.890 235.560 111.720 ;
        RECT 237.040 111.210 237.390 112.460 ;
        RECT 239.155 111.805 240.365 112.895 ;
        RECT 239.155 111.095 239.675 111.635 ;
        RECT 239.845 111.265 240.365 111.805 ;
        RECT 240.535 111.730 240.825 112.895 ;
        RECT 240.995 111.805 242.665 112.895 ;
        RECT 240.995 111.115 241.745 111.635 ;
        RECT 241.915 111.285 242.665 111.805 ;
        RECT 242.925 111.965 243.095 112.725 ;
        RECT 243.310 112.135 243.640 112.895 ;
        RECT 242.925 111.795 243.640 111.965 ;
        RECT 243.810 111.820 244.065 112.725 ;
        RECT 242.835 111.245 243.190 111.615 ;
        RECT 243.470 111.585 243.640 111.795 ;
        RECT 243.470 111.255 243.725 111.585 ;
        RECT 228.115 110.345 233.460 110.890 ;
        RECT 233.635 110.345 238.980 110.890 ;
        RECT 239.155 110.345 240.365 111.095 ;
        RECT 240.535 110.345 240.825 111.070 ;
        RECT 240.995 110.345 242.665 111.115 ;
        RECT 243.470 111.065 243.640 111.255 ;
        RECT 243.895 111.090 244.065 111.820 ;
        RECT 244.240 111.745 244.500 112.895 ;
        RECT 244.765 111.965 244.935 112.725 ;
        RECT 245.150 112.135 245.480 112.895 ;
        RECT 244.765 111.795 245.480 111.965 ;
        RECT 245.650 111.820 245.905 112.725 ;
        RECT 244.675 111.245 245.030 111.615 ;
        RECT 245.310 111.585 245.480 111.795 ;
        RECT 245.310 111.255 245.565 111.585 ;
        RECT 242.925 110.895 243.640 111.065 ;
        RECT 242.925 110.515 243.095 110.895 ;
        RECT 243.310 110.345 243.640 110.725 ;
        RECT 243.810 110.515 244.065 111.090 ;
        RECT 244.240 110.345 244.500 111.185 ;
        RECT 245.310 111.065 245.480 111.255 ;
        RECT 245.735 111.090 245.905 111.820 ;
        RECT 246.080 111.745 246.340 112.895 ;
        RECT 246.515 111.805 247.725 112.895 ;
        RECT 246.515 111.265 247.035 111.805 ;
        RECT 244.765 110.895 245.480 111.065 ;
        RECT 244.765 110.515 244.935 110.895 ;
        RECT 245.150 110.345 245.480 110.725 ;
        RECT 245.650 110.515 245.905 111.090 ;
        RECT 246.080 110.345 246.340 111.185 ;
        RECT 247.205 111.095 247.725 111.635 ;
        RECT 246.515 110.345 247.725 111.095 ;
        RECT 64.280 110.040 67.940 110.210 ;
        RECT 64.280 101.330 64.450 110.040 ;
        RECT 65.175 109.470 67.045 109.640 ;
        RECT 64.790 108.410 64.960 109.410 ;
        RECT 67.260 108.410 67.430 109.410 ;
        RECT 65.175 108.180 67.045 108.350 ;
        RECT 64.790 107.120 64.960 108.120 ;
        RECT 67.260 107.120 67.430 108.120 ;
        RECT 65.175 106.890 67.045 107.060 ;
        RECT 64.790 105.830 64.960 106.830 ;
        RECT 67.260 105.830 67.430 106.830 ;
        RECT 65.175 105.600 67.045 105.770 ;
        RECT 64.790 104.540 64.960 105.540 ;
        RECT 67.260 104.540 67.430 105.540 ;
        RECT 65.175 104.310 67.045 104.480 ;
        RECT 64.790 103.250 64.960 104.250 ;
        RECT 67.260 103.250 67.430 104.250 ;
        RECT 65.175 103.020 67.045 103.190 ;
        RECT 64.790 101.960 64.960 102.960 ;
        RECT 67.260 101.960 67.430 102.960 ;
        RECT 65.175 101.730 67.045 101.900 ;
        RECT 67.770 101.330 67.940 110.040 ;
        RECT 70.150 101.530 70.320 110.240 ;
        RECT 71.045 109.670 72.915 109.840 ;
        RECT 70.660 108.610 70.830 109.610 ;
        RECT 73.130 108.610 73.300 109.610 ;
        RECT 71.045 108.380 72.915 108.550 ;
        RECT 70.660 107.320 70.830 108.320 ;
        RECT 73.130 107.320 73.300 108.320 ;
        RECT 71.045 107.090 72.915 107.260 ;
        RECT 70.660 106.030 70.830 107.030 ;
        RECT 73.130 106.030 73.300 107.030 ;
        RECT 71.045 105.800 72.915 105.970 ;
        RECT 70.660 104.740 70.830 105.740 ;
        RECT 73.130 104.740 73.300 105.740 ;
        RECT 71.045 104.510 72.915 104.680 ;
        RECT 70.660 103.450 70.830 104.450 ;
        RECT 73.130 103.450 73.300 104.450 ;
        RECT 71.045 103.220 72.915 103.390 ;
        RECT 70.660 102.160 70.830 103.160 ;
        RECT 73.130 102.160 73.300 103.160 ;
        RECT 71.045 101.930 72.915 102.100 ;
        RECT 73.640 101.530 73.810 110.240 ;
        RECT 76.220 110.050 90.430 110.220 ;
        RECT 188.930 110.175 247.810 110.345 ;
        RECT 76.220 102.060 76.390 110.050 ;
        RECT 77.020 109.540 78.020 109.710 ;
        RECT 78.310 109.540 79.310 109.710 ;
        RECT 79.600 109.540 80.600 109.710 ;
        RECT 80.890 109.540 81.890 109.710 ;
        RECT 82.180 109.540 83.180 109.710 ;
        RECT 83.470 109.540 84.470 109.710 ;
        RECT 84.760 109.540 85.760 109.710 ;
        RECT 86.050 109.540 87.050 109.710 ;
        RECT 87.340 109.540 88.340 109.710 ;
        RECT 88.630 109.540 89.630 109.710 ;
        RECT 76.790 102.785 76.960 109.325 ;
        RECT 78.080 102.785 78.250 109.325 ;
        RECT 79.370 102.785 79.540 109.325 ;
        RECT 80.660 102.785 80.830 109.325 ;
        RECT 81.950 102.785 82.120 109.325 ;
        RECT 83.240 102.785 83.410 109.325 ;
        RECT 84.530 102.785 84.700 109.325 ;
        RECT 85.820 102.785 85.990 109.325 ;
        RECT 87.110 102.785 87.280 109.325 ;
        RECT 88.400 102.785 88.570 109.325 ;
        RECT 89.690 102.785 89.860 109.325 ;
        RECT 77.020 102.400 78.020 102.570 ;
        RECT 78.310 102.400 79.310 102.570 ;
        RECT 79.600 102.400 80.600 102.570 ;
        RECT 80.890 102.400 81.890 102.570 ;
        RECT 82.180 102.400 83.180 102.570 ;
        RECT 83.470 102.400 84.470 102.570 ;
        RECT 84.760 102.400 85.760 102.570 ;
        RECT 86.050 102.400 87.050 102.570 ;
        RECT 87.340 102.400 88.340 102.570 ;
        RECT 88.630 102.400 89.630 102.570 ;
        RECT 90.260 102.060 90.430 110.050 ;
        RECT 131.290 109.760 134.950 109.930 ;
        RECT 76.220 101.890 90.430 102.060 ;
        RECT 125.420 109.560 129.080 109.730 ;
        RECT 70.150 101.360 73.810 101.530 ;
        RECT 64.280 101.160 67.940 101.330 ;
        RECT 125.420 100.850 125.590 109.560 ;
        RECT 126.315 108.990 128.185 109.160 ;
        RECT 125.930 107.930 126.100 108.930 ;
        RECT 128.400 107.930 128.570 108.930 ;
        RECT 126.315 107.700 128.185 107.870 ;
        RECT 125.930 106.640 126.100 107.640 ;
        RECT 128.400 106.640 128.570 107.640 ;
        RECT 126.315 106.410 128.185 106.580 ;
        RECT 125.930 105.350 126.100 106.350 ;
        RECT 128.400 105.350 128.570 106.350 ;
        RECT 126.315 105.120 128.185 105.290 ;
        RECT 125.930 104.060 126.100 105.060 ;
        RECT 128.400 104.060 128.570 105.060 ;
        RECT 126.315 103.830 128.185 104.000 ;
        RECT 125.930 102.770 126.100 103.770 ;
        RECT 128.400 102.770 128.570 103.770 ;
        RECT 126.315 102.540 128.185 102.710 ;
        RECT 125.930 101.480 126.100 102.480 ;
        RECT 128.400 101.480 128.570 102.480 ;
        RECT 126.315 101.250 128.185 101.420 ;
        RECT 128.910 100.850 129.080 109.560 ;
        RECT 131.290 101.050 131.460 109.760 ;
        RECT 132.185 109.190 134.055 109.360 ;
        RECT 131.800 108.130 131.970 109.130 ;
        RECT 134.270 108.130 134.440 109.130 ;
        RECT 132.185 107.900 134.055 108.070 ;
        RECT 131.800 106.840 131.970 107.840 ;
        RECT 134.270 106.840 134.440 107.840 ;
        RECT 132.185 106.610 134.055 106.780 ;
        RECT 131.800 105.550 131.970 106.550 ;
        RECT 134.270 105.550 134.440 106.550 ;
        RECT 132.185 105.320 134.055 105.490 ;
        RECT 131.800 104.260 131.970 105.260 ;
        RECT 134.270 104.260 134.440 105.260 ;
        RECT 132.185 104.030 134.055 104.200 ;
        RECT 131.800 102.970 131.970 103.970 ;
        RECT 134.270 102.970 134.440 103.970 ;
        RECT 132.185 102.740 134.055 102.910 ;
        RECT 131.800 101.680 131.970 102.680 ;
        RECT 134.270 101.680 134.440 102.680 ;
        RECT 132.185 101.450 134.055 101.620 ;
        RECT 134.780 101.050 134.950 109.760 ;
        RECT 137.360 109.570 151.570 109.740 ;
        RECT 137.360 101.580 137.530 109.570 ;
        RECT 138.160 109.060 139.160 109.230 ;
        RECT 139.450 109.060 140.450 109.230 ;
        RECT 140.740 109.060 141.740 109.230 ;
        RECT 142.030 109.060 143.030 109.230 ;
        RECT 143.320 109.060 144.320 109.230 ;
        RECT 144.610 109.060 145.610 109.230 ;
        RECT 145.900 109.060 146.900 109.230 ;
        RECT 147.190 109.060 148.190 109.230 ;
        RECT 148.480 109.060 149.480 109.230 ;
        RECT 149.770 109.060 150.770 109.230 ;
        RECT 137.930 102.305 138.100 108.845 ;
        RECT 139.220 102.305 139.390 108.845 ;
        RECT 140.510 102.305 140.680 108.845 ;
        RECT 141.800 102.305 141.970 108.845 ;
        RECT 143.090 102.305 143.260 108.845 ;
        RECT 144.380 102.305 144.550 108.845 ;
        RECT 145.670 102.305 145.840 108.845 ;
        RECT 146.960 102.305 147.130 108.845 ;
        RECT 148.250 102.305 148.420 108.845 ;
        RECT 149.540 102.305 149.710 108.845 ;
        RECT 150.830 102.305 151.000 108.845 ;
        RECT 138.160 101.920 139.160 102.090 ;
        RECT 139.450 101.920 140.450 102.090 ;
        RECT 140.740 101.920 141.740 102.090 ;
        RECT 142.030 101.920 143.030 102.090 ;
        RECT 143.320 101.920 144.320 102.090 ;
        RECT 144.610 101.920 145.610 102.090 ;
        RECT 145.900 101.920 146.900 102.090 ;
        RECT 147.190 101.920 148.190 102.090 ;
        RECT 148.480 101.920 149.480 102.090 ;
        RECT 149.770 101.920 150.770 102.090 ;
        RECT 151.400 101.580 151.570 109.570 ;
        RECT 189.015 109.425 190.225 110.175 ;
        RECT 190.485 109.625 190.655 110.005 ;
        RECT 190.870 109.795 191.200 110.175 ;
        RECT 190.485 109.455 191.200 109.625 ;
        RECT 189.015 108.885 189.535 109.425 ;
        RECT 189.705 108.715 190.225 109.255 ;
        RECT 190.395 108.905 190.750 109.275 ;
        RECT 191.030 109.265 191.200 109.455 ;
        RECT 191.370 109.430 191.625 110.005 ;
        RECT 191.030 108.935 191.285 109.265 ;
        RECT 191.030 108.725 191.200 108.935 ;
        RECT 189.015 107.625 190.225 108.715 ;
        RECT 190.485 108.555 191.200 108.725 ;
        RECT 191.455 108.700 191.625 109.430 ;
        RECT 191.800 109.335 192.060 110.175 ;
        RECT 192.235 109.630 197.580 110.175 ;
        RECT 197.755 109.630 203.100 110.175 ;
        RECT 203.275 109.630 208.620 110.175 ;
        RECT 208.795 109.630 214.140 110.175 ;
        RECT 193.820 108.800 194.160 109.630 ;
        RECT 190.485 107.795 190.655 108.555 ;
        RECT 190.870 107.625 191.200 108.385 ;
        RECT 191.370 107.795 191.625 108.700 ;
        RECT 191.800 107.625 192.060 108.775 ;
        RECT 195.640 108.060 195.990 109.310 ;
        RECT 199.340 108.800 199.680 109.630 ;
        RECT 201.160 108.060 201.510 109.310 ;
        RECT 204.860 108.800 205.200 109.630 ;
        RECT 206.680 108.060 207.030 109.310 ;
        RECT 210.380 108.800 210.720 109.630 ;
        RECT 214.775 109.450 215.065 110.175 ;
        RECT 215.235 109.630 220.580 110.175 ;
        RECT 220.755 109.630 226.100 110.175 ;
        RECT 212.200 108.060 212.550 109.310 ;
        RECT 216.820 108.800 217.160 109.630 ;
        RECT 192.235 107.625 197.580 108.060 ;
        RECT 197.755 107.625 203.100 108.060 ;
        RECT 203.275 107.625 208.620 108.060 ;
        RECT 208.795 107.625 214.140 108.060 ;
        RECT 214.775 107.625 215.065 108.790 ;
        RECT 218.640 108.060 218.990 109.310 ;
        RECT 222.340 108.800 222.680 109.630 ;
        RECT 226.275 109.405 229.785 110.175 ;
        RECT 229.955 109.425 231.165 110.175 ;
        RECT 231.340 109.465 231.595 109.995 ;
        RECT 231.765 109.715 232.070 110.175 ;
        RECT 232.315 109.795 233.385 109.965 ;
        RECT 224.160 108.060 224.510 109.310 ;
        RECT 226.275 108.885 227.925 109.405 ;
        RECT 228.095 108.715 229.785 109.235 ;
        RECT 229.955 108.885 230.475 109.425 ;
        RECT 230.645 108.715 231.165 109.255 ;
        RECT 215.235 107.625 220.580 108.060 ;
        RECT 220.755 107.625 226.100 108.060 ;
        RECT 226.275 107.625 229.785 108.715 ;
        RECT 229.955 107.625 231.165 108.715 ;
        RECT 231.340 108.815 231.550 109.465 ;
        RECT 232.315 109.440 232.635 109.795 ;
        RECT 232.310 109.265 232.635 109.440 ;
        RECT 231.720 108.965 232.635 109.265 ;
        RECT 232.805 109.225 233.045 109.625 ;
        RECT 233.215 109.565 233.385 109.795 ;
        RECT 233.555 109.735 233.745 110.175 ;
        RECT 233.915 109.725 234.865 110.005 ;
        RECT 235.085 109.815 235.435 109.985 ;
        RECT 233.215 109.395 233.745 109.565 ;
        RECT 231.720 108.935 232.460 108.965 ;
        RECT 231.340 107.935 231.595 108.815 ;
        RECT 231.765 107.625 232.070 108.765 ;
        RECT 232.290 108.345 232.460 108.935 ;
        RECT 232.805 108.855 233.345 109.225 ;
        RECT 233.525 109.115 233.745 109.395 ;
        RECT 233.915 108.945 234.085 109.725 ;
        RECT 233.680 108.775 234.085 108.945 ;
        RECT 234.255 108.935 234.605 109.555 ;
        RECT 233.680 108.685 233.850 108.775 ;
        RECT 234.775 108.765 234.985 109.555 ;
        RECT 232.630 108.515 233.850 108.685 ;
        RECT 234.310 108.605 234.985 108.765 ;
        RECT 232.290 108.175 233.090 108.345 ;
        RECT 232.410 107.625 232.740 108.005 ;
        RECT 232.920 107.885 233.090 108.175 ;
        RECT 233.680 108.135 233.850 108.515 ;
        RECT 234.020 108.595 234.985 108.605 ;
        RECT 235.175 109.425 235.435 109.815 ;
        RECT 235.645 109.715 235.975 110.175 ;
        RECT 236.850 109.785 237.705 109.955 ;
        RECT 237.910 109.785 238.405 109.955 ;
        RECT 238.575 109.815 238.905 110.175 ;
        RECT 235.175 108.735 235.345 109.425 ;
        RECT 235.515 109.075 235.685 109.255 ;
        RECT 235.855 109.245 236.645 109.495 ;
        RECT 236.850 109.075 237.020 109.785 ;
        RECT 237.190 109.275 237.545 109.495 ;
        RECT 235.515 108.905 237.205 109.075 ;
        RECT 234.020 108.305 234.480 108.595 ;
        RECT 235.175 108.565 236.675 108.735 ;
        RECT 235.175 108.425 235.345 108.565 ;
        RECT 234.785 108.255 235.345 108.425 ;
        RECT 233.260 107.625 233.510 108.085 ;
        RECT 233.680 107.795 234.550 108.135 ;
        RECT 234.785 107.795 234.955 108.255 ;
        RECT 235.790 108.225 236.865 108.395 ;
        RECT 235.125 107.625 235.495 108.085 ;
        RECT 235.790 107.885 235.960 108.225 ;
        RECT 236.130 107.625 236.460 108.055 ;
        RECT 236.695 107.885 236.865 108.225 ;
        RECT 237.035 108.125 237.205 108.905 ;
        RECT 237.375 108.685 237.545 109.275 ;
        RECT 237.715 108.875 238.065 109.495 ;
        RECT 237.375 108.295 237.840 108.685 ;
        RECT 238.235 108.425 238.405 109.785 ;
        RECT 238.575 108.595 239.035 109.645 ;
        RECT 238.010 108.255 238.405 108.425 ;
        RECT 238.010 108.125 238.180 108.255 ;
        RECT 237.035 107.795 237.715 108.125 ;
        RECT 237.930 107.795 238.180 108.125 ;
        RECT 238.350 107.625 238.600 108.085 ;
        RECT 238.770 107.810 239.095 108.595 ;
        RECT 239.265 107.795 239.435 109.915 ;
        RECT 239.605 109.795 239.935 110.175 ;
        RECT 240.105 109.625 240.360 109.915 ;
        RECT 239.610 109.455 240.360 109.625 ;
        RECT 239.610 108.465 239.840 109.455 ;
        RECT 240.535 109.450 240.825 110.175 ;
        RECT 240.995 109.630 246.340 110.175 ;
        RECT 240.010 108.635 240.360 109.285 ;
        RECT 242.580 108.800 242.920 109.630 ;
        RECT 246.515 109.425 247.725 110.175 ;
        RECT 239.610 108.295 240.360 108.465 ;
        RECT 239.605 107.625 239.935 108.125 ;
        RECT 240.105 107.795 240.360 108.295 ;
        RECT 240.535 107.625 240.825 108.790 ;
        RECT 244.400 108.060 244.750 109.310 ;
        RECT 246.515 108.715 247.035 109.255 ;
        RECT 247.205 108.885 247.725 109.425 ;
        RECT 240.995 107.625 246.340 108.060 ;
        RECT 246.515 107.625 247.725 108.715 ;
        RECT 188.930 107.455 247.810 107.625 ;
        RECT 189.015 106.365 190.225 107.455 ;
        RECT 190.395 107.020 195.740 107.455 ;
        RECT 195.915 107.020 201.260 107.455 ;
        RECT 189.015 105.655 189.535 106.195 ;
        RECT 189.705 105.825 190.225 106.365 ;
        RECT 189.015 104.905 190.225 105.655 ;
        RECT 191.980 105.450 192.320 106.280 ;
        RECT 193.800 105.770 194.150 107.020 ;
        RECT 197.500 105.450 197.840 106.280 ;
        RECT 199.320 105.770 199.670 107.020 ;
        RECT 201.895 106.290 202.185 107.455 ;
        RECT 202.355 107.020 207.700 107.455 ;
        RECT 207.875 107.020 213.220 107.455 ;
        RECT 213.395 107.020 218.740 107.455 ;
        RECT 218.915 107.020 224.260 107.455 ;
        RECT 190.395 104.905 195.740 105.450 ;
        RECT 195.915 104.905 201.260 105.450 ;
        RECT 201.895 104.905 202.185 105.630 ;
        RECT 203.940 105.450 204.280 106.280 ;
        RECT 205.760 105.770 206.110 107.020 ;
        RECT 209.460 105.450 209.800 106.280 ;
        RECT 211.280 105.770 211.630 107.020 ;
        RECT 214.980 105.450 215.320 106.280 ;
        RECT 216.800 105.770 217.150 107.020 ;
        RECT 220.500 105.450 220.840 106.280 ;
        RECT 222.320 105.770 222.670 107.020 ;
        RECT 224.435 106.365 227.025 107.455 ;
        RECT 224.435 105.675 225.645 106.195 ;
        RECT 225.815 105.845 227.025 106.365 ;
        RECT 227.655 106.290 227.945 107.455 ;
        RECT 229.045 106.645 229.340 107.455 ;
        RECT 229.520 106.145 229.765 107.285 ;
        RECT 229.940 106.645 230.200 107.455 ;
        RECT 230.800 107.450 237.075 107.455 ;
        RECT 230.380 106.145 230.630 107.280 ;
        RECT 230.800 106.655 231.060 107.450 ;
        RECT 231.230 106.555 231.490 107.280 ;
        RECT 231.660 106.725 231.920 107.450 ;
        RECT 232.090 106.555 232.350 107.280 ;
        RECT 232.520 106.725 232.780 107.450 ;
        RECT 232.950 106.555 233.210 107.280 ;
        RECT 233.380 106.725 233.640 107.450 ;
        RECT 233.810 106.555 234.070 107.280 ;
        RECT 234.240 106.725 234.485 107.450 ;
        RECT 234.655 106.555 234.915 107.280 ;
        RECT 235.100 106.725 235.345 107.450 ;
        RECT 235.515 106.555 235.775 107.280 ;
        RECT 235.960 106.725 236.205 107.450 ;
        RECT 236.375 106.555 236.635 107.280 ;
        RECT 236.820 106.725 237.075 107.450 ;
        RECT 231.230 106.540 236.635 106.555 ;
        RECT 237.245 106.540 237.535 107.280 ;
        RECT 237.705 106.710 237.975 107.455 ;
        RECT 231.230 106.435 237.975 106.540 ;
        RECT 231.230 106.315 238.005 106.435 ;
        RECT 236.810 106.265 238.005 106.315 ;
        RECT 238.235 106.315 238.620 107.285 ;
        RECT 238.790 106.995 239.115 107.455 ;
        RECT 239.635 106.825 239.915 107.285 ;
        RECT 238.790 106.605 239.915 106.825 ;
        RECT 202.355 104.905 207.700 105.450 ;
        RECT 207.875 104.905 213.220 105.450 ;
        RECT 213.395 104.905 218.740 105.450 ;
        RECT 218.915 104.905 224.260 105.450 ;
        RECT 224.435 104.905 227.025 105.675 ;
        RECT 227.655 104.905 227.945 105.630 ;
        RECT 229.035 105.585 229.350 106.145 ;
        RECT 229.520 105.895 236.640 106.145 ;
        RECT 229.035 104.905 229.340 105.415 ;
        RECT 229.520 105.085 229.770 105.895 ;
        RECT 229.940 104.905 230.200 105.430 ;
        RECT 230.380 105.085 230.630 105.895 ;
        RECT 236.810 105.725 237.975 106.265 ;
        RECT 231.230 105.555 237.975 105.725 ;
        RECT 238.235 105.645 238.515 106.315 ;
        RECT 238.790 106.145 239.240 106.605 ;
        RECT 240.105 106.435 240.505 107.285 ;
        RECT 240.905 106.995 241.175 107.455 ;
        RECT 241.345 106.825 241.630 107.285 ;
        RECT 238.685 105.815 239.240 106.145 ;
        RECT 239.410 105.875 240.505 106.435 ;
        RECT 238.790 105.705 239.240 105.815 ;
        RECT 230.800 104.905 231.060 105.465 ;
        RECT 231.230 105.100 231.490 105.555 ;
        RECT 231.660 104.905 231.920 105.385 ;
        RECT 232.090 105.100 232.350 105.555 ;
        RECT 232.520 104.905 232.780 105.385 ;
        RECT 232.950 105.100 233.210 105.555 ;
        RECT 233.380 104.905 233.625 105.385 ;
        RECT 233.795 105.100 234.070 105.555 ;
        RECT 234.240 104.905 234.485 105.385 ;
        RECT 234.655 105.100 234.915 105.555 ;
        RECT 235.095 104.905 235.345 105.385 ;
        RECT 235.515 105.100 235.775 105.555 ;
        RECT 235.955 104.905 236.205 105.385 ;
        RECT 236.375 105.100 236.635 105.555 ;
        RECT 236.815 104.905 237.075 105.385 ;
        RECT 237.245 105.100 237.505 105.555 ;
        RECT 237.675 104.905 237.975 105.385 ;
        RECT 238.235 105.075 238.620 105.645 ;
        RECT 238.790 105.535 239.915 105.705 ;
        RECT 238.790 104.905 239.115 105.365 ;
        RECT 239.635 105.075 239.915 105.535 ;
        RECT 240.105 105.075 240.505 105.875 ;
        RECT 240.675 106.605 241.630 106.825 ;
        RECT 240.675 105.705 240.885 106.605 ;
        RECT 241.055 105.875 241.745 106.435 ;
        RECT 241.915 106.365 244.505 107.455 ;
        RECT 240.675 105.535 241.630 105.705 ;
        RECT 240.905 104.905 241.175 105.365 ;
        RECT 241.345 105.075 241.630 105.535 ;
        RECT 241.915 105.675 243.125 106.195 ;
        RECT 243.295 105.845 244.505 106.365 ;
        RECT 244.765 106.525 244.935 107.285 ;
        RECT 245.150 106.695 245.480 107.455 ;
        RECT 244.765 106.355 245.480 106.525 ;
        RECT 245.650 106.380 245.905 107.285 ;
        RECT 244.675 105.805 245.030 106.175 ;
        RECT 245.310 106.145 245.480 106.355 ;
        RECT 245.310 105.815 245.565 106.145 ;
        RECT 241.915 104.905 244.505 105.675 ;
        RECT 245.310 105.625 245.480 105.815 ;
        RECT 245.735 105.650 245.905 106.380 ;
        RECT 246.080 106.305 246.340 107.455 ;
        RECT 246.515 106.365 247.725 107.455 ;
        RECT 246.515 105.825 247.035 106.365 ;
        RECT 244.765 105.455 245.480 105.625 ;
        RECT 244.765 105.075 244.935 105.455 ;
        RECT 245.150 104.905 245.480 105.285 ;
        RECT 245.650 105.075 245.905 105.650 ;
        RECT 246.080 104.905 246.340 105.745 ;
        RECT 247.205 105.655 247.725 106.195 ;
        RECT 246.515 104.905 247.725 105.655 ;
        RECT 188.930 104.735 247.810 104.905 ;
        RECT 189.015 103.985 190.225 104.735 ;
        RECT 190.395 104.190 195.740 104.735 ;
        RECT 195.915 104.190 201.260 104.735 ;
        RECT 201.435 104.190 206.780 104.735 ;
        RECT 206.955 104.190 212.300 104.735 ;
        RECT 189.015 103.445 189.535 103.985 ;
        RECT 189.705 103.275 190.225 103.815 ;
        RECT 191.980 103.360 192.320 104.190 ;
        RECT 189.015 102.185 190.225 103.275 ;
        RECT 193.800 102.620 194.150 103.870 ;
        RECT 197.500 103.360 197.840 104.190 ;
        RECT 199.320 102.620 199.670 103.870 ;
        RECT 203.020 103.360 203.360 104.190 ;
        RECT 204.840 102.620 205.190 103.870 ;
        RECT 208.540 103.360 208.880 104.190 ;
        RECT 212.475 103.965 214.145 104.735 ;
        RECT 214.775 104.010 215.065 104.735 ;
        RECT 215.235 104.190 220.580 104.735 ;
        RECT 220.755 104.190 226.100 104.735 ;
        RECT 210.360 102.620 210.710 103.870 ;
        RECT 212.475 103.445 213.225 103.965 ;
        RECT 213.395 103.275 214.145 103.795 ;
        RECT 216.820 103.360 217.160 104.190 ;
        RECT 190.395 102.185 195.740 102.620 ;
        RECT 195.915 102.185 201.260 102.620 ;
        RECT 201.435 102.185 206.780 102.620 ;
        RECT 206.955 102.185 212.300 102.620 ;
        RECT 212.475 102.185 214.145 103.275 ;
        RECT 214.775 102.185 215.065 103.350 ;
        RECT 218.640 102.620 218.990 103.870 ;
        RECT 222.340 103.360 222.680 104.190 ;
        RECT 226.275 103.965 229.785 104.735 ;
        RECT 229.960 104.185 230.215 104.475 ;
        RECT 230.385 104.355 230.715 104.735 ;
        RECT 229.960 104.015 230.710 104.185 ;
        RECT 224.160 102.620 224.510 103.870 ;
        RECT 226.275 103.445 227.925 103.965 ;
        RECT 228.095 103.275 229.785 103.795 ;
        RECT 215.235 102.185 220.580 102.620 ;
        RECT 220.755 102.185 226.100 102.620 ;
        RECT 226.275 102.185 229.785 103.275 ;
        RECT 229.960 103.195 230.310 103.845 ;
        RECT 230.480 103.025 230.710 104.015 ;
        RECT 229.960 102.855 230.710 103.025 ;
        RECT 229.960 102.355 230.215 102.855 ;
        RECT 230.385 102.185 230.715 102.685 ;
        RECT 230.885 102.355 231.055 104.475 ;
        RECT 231.415 104.375 231.745 104.735 ;
        RECT 231.915 104.345 232.410 104.515 ;
        RECT 232.615 104.345 233.470 104.515 ;
        RECT 231.285 103.155 231.745 104.205 ;
        RECT 231.225 102.370 231.550 103.155 ;
        RECT 231.915 102.985 232.085 104.345 ;
        RECT 232.255 103.435 232.605 104.055 ;
        RECT 232.775 103.835 233.130 104.055 ;
        RECT 232.775 103.245 232.945 103.835 ;
        RECT 233.300 103.635 233.470 104.345 ;
        RECT 234.345 104.275 234.675 104.735 ;
        RECT 234.885 104.375 235.235 104.545 ;
        RECT 233.675 103.805 234.465 104.055 ;
        RECT 234.885 103.985 235.145 104.375 ;
        RECT 235.455 104.285 236.405 104.565 ;
        RECT 236.575 104.295 236.765 104.735 ;
        RECT 236.935 104.355 238.005 104.525 ;
        RECT 234.635 103.635 234.805 103.815 ;
        RECT 231.915 102.815 232.310 102.985 ;
        RECT 232.480 102.855 232.945 103.245 ;
        RECT 233.115 103.465 234.805 103.635 ;
        RECT 232.140 102.685 232.310 102.815 ;
        RECT 233.115 102.685 233.285 103.465 ;
        RECT 234.975 103.295 235.145 103.985 ;
        RECT 233.645 103.125 235.145 103.295 ;
        RECT 235.335 103.325 235.545 104.115 ;
        RECT 235.715 103.495 236.065 104.115 ;
        RECT 236.235 103.505 236.405 104.285 ;
        RECT 236.935 104.125 237.105 104.355 ;
        RECT 236.575 103.955 237.105 104.125 ;
        RECT 236.575 103.675 236.795 103.955 ;
        RECT 237.275 103.785 237.515 104.185 ;
        RECT 236.235 103.335 236.640 103.505 ;
        RECT 236.975 103.415 237.515 103.785 ;
        RECT 237.685 104.000 238.005 104.355 ;
        RECT 238.250 104.275 238.555 104.735 ;
        RECT 238.725 104.025 238.980 104.555 ;
        RECT 237.685 103.825 238.010 104.000 ;
        RECT 237.685 103.525 238.600 103.825 ;
        RECT 237.860 103.495 238.600 103.525 ;
        RECT 235.335 103.165 236.010 103.325 ;
        RECT 236.470 103.245 236.640 103.335 ;
        RECT 235.335 103.155 236.300 103.165 ;
        RECT 234.975 102.985 235.145 103.125 ;
        RECT 231.720 102.185 231.970 102.645 ;
        RECT 232.140 102.355 232.390 102.685 ;
        RECT 232.605 102.355 233.285 102.685 ;
        RECT 233.455 102.785 234.530 102.955 ;
        RECT 234.975 102.815 235.535 102.985 ;
        RECT 235.840 102.865 236.300 103.155 ;
        RECT 236.470 103.075 237.690 103.245 ;
        RECT 233.455 102.445 233.625 102.785 ;
        RECT 233.860 102.185 234.190 102.615 ;
        RECT 234.360 102.445 234.530 102.785 ;
        RECT 234.825 102.185 235.195 102.645 ;
        RECT 235.365 102.355 235.535 102.815 ;
        RECT 236.470 102.695 236.640 103.075 ;
        RECT 237.860 102.905 238.030 103.495 ;
        RECT 238.770 103.375 238.980 104.025 ;
        RECT 239.245 104.185 239.415 104.565 ;
        RECT 239.595 104.355 239.925 104.735 ;
        RECT 239.245 104.015 239.910 104.185 ;
        RECT 240.105 104.060 240.365 104.565 ;
        RECT 239.175 103.465 239.505 103.835 ;
        RECT 239.740 103.760 239.910 104.015 ;
        RECT 235.770 102.355 236.640 102.695 ;
        RECT 237.230 102.735 238.030 102.905 ;
        RECT 236.810 102.185 237.060 102.645 ;
        RECT 237.230 102.445 237.400 102.735 ;
        RECT 237.580 102.185 237.910 102.565 ;
        RECT 238.250 102.185 238.555 103.325 ;
        RECT 238.725 102.495 238.980 103.375 ;
        RECT 239.740 103.430 240.025 103.760 ;
        RECT 239.740 103.285 239.910 103.430 ;
        RECT 239.245 103.115 239.910 103.285 ;
        RECT 240.195 103.260 240.365 104.060 ;
        RECT 240.535 104.010 240.825 104.735 ;
        RECT 240.995 104.190 246.340 104.735 ;
        RECT 242.580 103.360 242.920 104.190 ;
        RECT 246.515 103.985 247.725 104.735 ;
        RECT 239.245 102.355 239.415 103.115 ;
        RECT 239.595 102.185 239.925 102.945 ;
        RECT 240.095 102.355 240.365 103.260 ;
        RECT 240.535 102.185 240.825 103.350 ;
        RECT 244.400 102.620 244.750 103.870 ;
        RECT 246.515 103.275 247.035 103.815 ;
        RECT 247.205 103.445 247.725 103.985 ;
        RECT 240.995 102.185 246.340 102.620 ;
        RECT 246.515 102.185 247.725 103.275 ;
        RECT 188.930 102.015 247.810 102.185 ;
        RECT 137.360 101.410 151.570 101.580 ;
        RECT 131.290 100.880 134.950 101.050 ;
        RECT 189.015 100.925 190.225 102.015 ;
        RECT 190.395 101.580 195.740 102.015 ;
        RECT 195.915 101.580 201.260 102.015 ;
        RECT 125.420 100.680 129.080 100.850 ;
        RECT 189.015 100.215 189.535 100.755 ;
        RECT 189.705 100.385 190.225 100.925 ;
        RECT 81.430 100.030 88.060 100.200 ;
        RECT 64.950 99.590 67.050 99.760 ;
        RECT 64.950 97.190 65.120 99.590 ;
        RECT 65.750 99.080 66.250 99.250 ;
        RECT 65.520 97.870 65.690 98.910 ;
        RECT 66.310 97.870 66.480 98.910 ;
        RECT 65.750 97.530 66.250 97.700 ;
        RECT 66.880 97.190 67.050 99.590 ;
        RECT 64.950 97.020 67.050 97.190 ;
        RECT 70.760 99.590 72.860 99.760 ;
        RECT 70.760 97.190 70.930 99.590 ;
        RECT 71.560 99.080 72.060 99.250 ;
        RECT 71.330 97.870 71.500 98.910 ;
        RECT 72.120 97.870 72.290 98.910 ;
        RECT 71.560 97.530 72.060 97.700 ;
        RECT 72.690 97.190 72.860 99.590 ;
        RECT 81.430 98.720 81.600 100.030 ;
        RECT 82.080 99.200 84.240 99.550 ;
        RECT 85.250 99.200 87.410 99.550 ;
        RECT 87.890 98.720 88.060 100.030 ;
        RECT 142.570 99.550 149.200 99.720 ;
        RECT 81.430 98.550 88.060 98.720 ;
        RECT 126.090 99.110 128.190 99.280 ;
        RECT 70.760 97.020 72.860 97.190 ;
        RECT 126.090 96.710 126.260 99.110 ;
        RECT 126.890 98.600 127.390 98.770 ;
        RECT 126.660 97.390 126.830 98.430 ;
        RECT 127.450 97.390 127.620 98.430 ;
        RECT 126.890 97.050 127.390 97.220 ;
        RECT 128.020 96.710 128.190 99.110 ;
        RECT 77.490 96.470 82.480 96.640 ;
        RECT 126.090 96.540 128.190 96.710 ;
        RECT 131.900 99.110 134.000 99.280 ;
        RECT 131.900 96.710 132.070 99.110 ;
        RECT 132.700 98.600 133.200 98.770 ;
        RECT 132.470 97.390 132.640 98.430 ;
        RECT 133.260 97.390 133.430 98.430 ;
        RECT 132.700 97.050 133.200 97.220 ;
        RECT 133.830 96.710 134.000 99.110 ;
        RECT 142.570 98.240 142.740 99.550 ;
        RECT 143.220 98.720 145.380 99.070 ;
        RECT 146.390 98.720 148.550 99.070 ;
        RECT 149.030 98.240 149.200 99.550 ;
        RECT 189.015 99.465 190.225 100.215 ;
        RECT 191.980 100.010 192.320 100.840 ;
        RECT 193.800 100.330 194.150 101.580 ;
        RECT 197.500 100.010 197.840 100.840 ;
        RECT 199.320 100.330 199.670 101.580 ;
        RECT 201.895 100.850 202.185 102.015 ;
        RECT 202.355 101.580 207.700 102.015 ;
        RECT 207.875 101.580 213.220 102.015 ;
        RECT 213.395 101.580 218.740 102.015 ;
        RECT 218.915 101.580 224.260 102.015 ;
        RECT 190.395 99.465 195.740 100.010 ;
        RECT 195.915 99.465 201.260 100.010 ;
        RECT 201.895 99.465 202.185 100.190 ;
        RECT 203.940 100.010 204.280 100.840 ;
        RECT 205.760 100.330 206.110 101.580 ;
        RECT 209.460 100.010 209.800 100.840 ;
        RECT 211.280 100.330 211.630 101.580 ;
        RECT 214.980 100.010 215.320 100.840 ;
        RECT 216.800 100.330 217.150 101.580 ;
        RECT 220.500 100.010 220.840 100.840 ;
        RECT 222.320 100.330 222.670 101.580 ;
        RECT 224.435 100.925 227.025 102.015 ;
        RECT 224.435 100.235 225.645 100.755 ;
        RECT 225.815 100.405 227.025 100.925 ;
        RECT 227.655 100.850 227.945 102.015 ;
        RECT 228.120 100.825 228.375 101.705 ;
        RECT 228.545 100.875 228.850 102.015 ;
        RECT 229.190 101.635 229.520 102.015 ;
        RECT 229.700 101.465 229.870 101.755 ;
        RECT 230.040 101.555 230.290 102.015 ;
        RECT 229.070 101.295 229.870 101.465 ;
        RECT 230.460 101.505 231.330 101.845 ;
        RECT 202.355 99.465 207.700 100.010 ;
        RECT 207.875 99.465 213.220 100.010 ;
        RECT 213.395 99.465 218.740 100.010 ;
        RECT 218.915 99.465 224.260 100.010 ;
        RECT 224.435 99.465 227.025 100.235 ;
        RECT 227.655 99.465 227.945 100.190 ;
        RECT 228.120 100.175 228.330 100.825 ;
        RECT 229.070 100.705 229.240 101.295 ;
        RECT 230.460 101.125 230.630 101.505 ;
        RECT 231.565 101.385 231.735 101.845 ;
        RECT 231.905 101.555 232.275 102.015 ;
        RECT 232.570 101.415 232.740 101.755 ;
        RECT 232.910 101.585 233.240 102.015 ;
        RECT 233.475 101.415 233.645 101.755 ;
        RECT 229.410 100.955 230.630 101.125 ;
        RECT 230.800 101.045 231.260 101.335 ;
        RECT 231.565 101.215 232.125 101.385 ;
        RECT 232.570 101.245 233.645 101.415 ;
        RECT 233.815 101.515 234.495 101.845 ;
        RECT 234.710 101.515 234.960 101.845 ;
        RECT 235.130 101.555 235.380 102.015 ;
        RECT 231.955 101.075 232.125 101.215 ;
        RECT 230.800 101.035 231.765 101.045 ;
        RECT 230.460 100.865 230.630 100.955 ;
        RECT 231.090 100.875 231.765 101.035 ;
        RECT 228.500 100.675 229.240 100.705 ;
        RECT 228.500 100.375 229.415 100.675 ;
        RECT 229.090 100.200 229.415 100.375 ;
        RECT 228.120 99.645 228.375 100.175 ;
        RECT 228.545 99.465 228.850 99.925 ;
        RECT 229.095 99.845 229.415 100.200 ;
        RECT 229.585 100.415 230.125 100.785 ;
        RECT 230.460 100.695 230.865 100.865 ;
        RECT 229.585 100.015 229.825 100.415 ;
        RECT 230.305 100.245 230.525 100.525 ;
        RECT 229.995 100.075 230.525 100.245 ;
        RECT 229.995 99.845 230.165 100.075 ;
        RECT 230.695 99.915 230.865 100.695 ;
        RECT 231.035 100.085 231.385 100.705 ;
        RECT 231.555 100.085 231.765 100.875 ;
        RECT 231.955 100.905 233.455 101.075 ;
        RECT 231.955 100.215 232.125 100.905 ;
        RECT 233.815 100.735 233.985 101.515 ;
        RECT 234.790 101.385 234.960 101.515 ;
        RECT 232.295 100.565 233.985 100.735 ;
        RECT 234.155 100.955 234.620 101.345 ;
        RECT 234.790 101.215 235.185 101.385 ;
        RECT 232.295 100.385 232.465 100.565 ;
        RECT 229.095 99.675 230.165 99.845 ;
        RECT 230.335 99.465 230.525 99.905 ;
        RECT 230.695 99.635 231.645 99.915 ;
        RECT 231.955 99.825 232.215 100.215 ;
        RECT 232.635 100.145 233.425 100.395 ;
        RECT 231.865 99.655 232.215 99.825 ;
        RECT 232.425 99.465 232.755 99.925 ;
        RECT 233.630 99.855 233.800 100.565 ;
        RECT 234.155 100.365 234.325 100.955 ;
        RECT 233.970 100.145 234.325 100.365 ;
        RECT 234.495 100.145 234.845 100.765 ;
        RECT 235.015 99.855 235.185 101.215 ;
        RECT 235.550 101.045 235.875 101.830 ;
        RECT 235.355 99.995 235.815 101.045 ;
        RECT 233.630 99.685 234.485 99.855 ;
        RECT 234.690 99.685 235.185 99.855 ;
        RECT 235.355 99.465 235.685 99.825 ;
        RECT 236.045 99.725 236.215 101.845 ;
        RECT 236.385 101.515 236.715 102.015 ;
        RECT 236.885 101.345 237.140 101.845 ;
        RECT 236.390 101.175 237.140 101.345 ;
        RECT 236.390 100.185 236.620 101.175 ;
        RECT 236.790 100.355 237.140 101.005 ;
        RECT 237.315 100.875 237.700 101.845 ;
        RECT 237.870 101.555 238.195 102.015 ;
        RECT 238.715 101.385 238.995 101.845 ;
        RECT 237.870 101.165 238.995 101.385 ;
        RECT 237.315 100.205 237.595 100.875 ;
        RECT 237.870 100.705 238.320 101.165 ;
        RECT 239.185 100.995 239.585 101.845 ;
        RECT 239.985 101.555 240.255 102.015 ;
        RECT 240.425 101.385 240.710 101.845 ;
        RECT 240.995 101.580 246.340 102.015 ;
        RECT 237.765 100.375 238.320 100.705 ;
        RECT 238.490 100.435 239.585 100.995 ;
        RECT 237.870 100.265 238.320 100.375 ;
        RECT 236.390 100.015 237.140 100.185 ;
        RECT 236.385 99.465 236.715 99.845 ;
        RECT 236.885 99.725 237.140 100.015 ;
        RECT 237.315 99.635 237.700 100.205 ;
        RECT 237.870 100.095 238.995 100.265 ;
        RECT 237.870 99.465 238.195 99.925 ;
        RECT 238.715 99.635 238.995 100.095 ;
        RECT 239.185 99.635 239.585 100.435 ;
        RECT 239.755 101.165 240.710 101.385 ;
        RECT 239.755 100.265 239.965 101.165 ;
        RECT 240.135 100.435 240.825 100.995 ;
        RECT 239.755 100.095 240.710 100.265 ;
        RECT 239.985 99.465 240.255 99.925 ;
        RECT 240.425 99.635 240.710 100.095 ;
        RECT 242.580 100.010 242.920 100.840 ;
        RECT 244.400 100.330 244.750 101.580 ;
        RECT 246.515 100.925 247.725 102.015 ;
        RECT 246.515 100.385 247.035 100.925 ;
        RECT 247.205 100.215 247.725 100.755 ;
        RECT 240.995 99.465 246.340 100.010 ;
        RECT 246.515 99.465 247.725 100.215 ;
        RECT 188.930 99.295 247.810 99.465 ;
        RECT 189.015 98.545 190.225 99.295 ;
        RECT 190.395 98.750 195.740 99.295 ;
        RECT 195.915 98.750 201.260 99.295 ;
        RECT 201.435 98.750 206.780 99.295 ;
        RECT 206.955 98.750 212.300 99.295 ;
        RECT 142.570 98.070 149.200 98.240 ;
        RECT 176.720 98.250 180.550 98.420 ;
        RECT 131.900 96.540 134.000 96.710 ;
        RECT 176.720 96.840 176.890 98.250 ;
        RECT 177.230 97.380 177.400 97.710 ;
        RECT 177.615 97.680 179.655 97.850 ;
        RECT 177.615 97.240 179.655 97.410 ;
        RECT 179.870 97.380 180.040 97.710 ;
        RECT 180.380 96.840 180.550 98.250 ;
        RECT 189.015 98.005 189.535 98.545 ;
        RECT 189.705 97.835 190.225 98.375 ;
        RECT 191.980 97.920 192.320 98.750 ;
        RECT 176.720 96.670 180.550 96.840 ;
        RECT 189.015 96.745 190.225 97.835 ;
        RECT 193.800 97.180 194.150 98.430 ;
        RECT 197.500 97.920 197.840 98.750 ;
        RECT 199.320 97.180 199.670 98.430 ;
        RECT 203.020 97.920 203.360 98.750 ;
        RECT 204.840 97.180 205.190 98.430 ;
        RECT 208.540 97.920 208.880 98.750 ;
        RECT 212.475 98.525 214.145 99.295 ;
        RECT 214.775 98.570 215.065 99.295 ;
        RECT 215.235 98.750 220.580 99.295 ;
        RECT 220.755 98.750 226.100 99.295 ;
        RECT 210.360 97.180 210.710 98.430 ;
        RECT 212.475 98.005 213.225 98.525 ;
        RECT 213.395 97.835 214.145 98.355 ;
        RECT 216.820 97.920 217.160 98.750 ;
        RECT 190.395 96.745 195.740 97.180 ;
        RECT 195.915 96.745 201.260 97.180 ;
        RECT 201.435 96.745 206.780 97.180 ;
        RECT 206.955 96.745 212.300 97.180 ;
        RECT 212.475 96.745 214.145 97.835 ;
        RECT 214.775 96.745 215.065 97.910 ;
        RECT 218.640 97.180 218.990 98.430 ;
        RECT 222.340 97.920 222.680 98.750 ;
        RECT 226.275 98.525 227.945 99.295 ;
        RECT 228.575 98.555 228.895 99.035 ;
        RECT 229.065 98.725 229.295 99.125 ;
        RECT 229.465 98.905 229.815 99.295 ;
        RECT 229.065 98.645 229.575 98.725 ;
        RECT 229.985 98.645 230.315 99.125 ;
        RECT 229.065 98.555 230.315 98.645 ;
        RECT 224.160 97.180 224.510 98.430 ;
        RECT 226.275 98.005 227.025 98.525 ;
        RECT 227.195 97.835 227.945 98.355 ;
        RECT 215.235 96.745 220.580 97.180 ;
        RECT 220.755 96.745 226.100 97.180 ;
        RECT 226.275 96.745 227.945 97.835 ;
        RECT 228.575 97.625 228.745 98.555 ;
        RECT 229.405 98.475 230.315 98.555 ;
        RECT 230.485 98.475 230.655 99.295 ;
        RECT 231.160 98.555 231.625 99.100 ;
        RECT 228.915 97.965 229.085 98.385 ;
        RECT 229.315 98.135 229.915 98.305 ;
        RECT 228.915 97.795 229.575 97.965 ;
        RECT 228.575 97.425 229.235 97.625 ;
        RECT 229.405 97.595 229.575 97.795 ;
        RECT 229.745 97.935 229.915 98.135 ;
        RECT 230.085 98.105 230.780 98.305 ;
        RECT 231.040 97.935 231.285 98.385 ;
        RECT 229.745 97.765 231.285 97.935 ;
        RECT 231.455 97.595 231.625 98.555 ;
        RECT 231.910 98.665 232.195 99.125 ;
        RECT 232.365 98.835 232.635 99.295 ;
        RECT 231.910 98.495 232.865 98.665 ;
        RECT 231.795 97.765 232.485 98.325 ;
        RECT 232.655 97.595 232.865 98.495 ;
        RECT 229.405 97.425 231.625 97.595 ;
        RECT 229.065 97.255 229.235 97.425 ;
        RECT 228.595 96.745 228.895 97.255 ;
        RECT 229.065 97.085 229.445 97.255 ;
        RECT 230.025 96.745 230.655 97.255 ;
        RECT 230.825 96.915 231.155 97.425 ;
        RECT 231.910 97.375 232.865 97.595 ;
        RECT 233.035 98.325 233.435 99.125 ;
        RECT 233.625 98.665 233.905 99.125 ;
        RECT 234.425 98.835 234.750 99.295 ;
        RECT 233.625 98.495 234.750 98.665 ;
        RECT 234.920 98.555 235.305 99.125 ;
        RECT 234.300 98.385 234.750 98.495 ;
        RECT 233.035 97.765 234.130 98.325 ;
        RECT 234.300 98.055 234.855 98.385 ;
        RECT 231.325 96.745 231.625 97.255 ;
        RECT 231.910 96.915 232.195 97.375 ;
        RECT 232.365 96.745 232.635 97.205 ;
        RECT 233.035 96.915 233.435 97.765 ;
        RECT 234.300 97.595 234.750 98.055 ;
        RECT 235.025 97.885 235.305 98.555 ;
        RECT 235.475 98.525 238.985 99.295 ;
        RECT 239.155 98.545 240.365 99.295 ;
        RECT 240.535 98.570 240.825 99.295 ;
        RECT 235.475 98.005 237.125 98.525 ;
        RECT 233.625 97.375 234.750 97.595 ;
        RECT 233.625 96.915 233.905 97.375 ;
        RECT 234.425 96.745 234.750 97.205 ;
        RECT 234.920 96.915 235.305 97.885 ;
        RECT 237.295 97.835 238.985 98.355 ;
        RECT 239.155 98.005 239.675 98.545 ;
        RECT 240.995 98.525 244.505 99.295 ;
        RECT 244.765 98.745 244.935 99.125 ;
        RECT 245.150 98.915 245.480 99.295 ;
        RECT 244.765 98.575 245.480 98.745 ;
        RECT 239.845 97.835 240.365 98.375 ;
        RECT 240.995 98.005 242.645 98.525 ;
        RECT 235.475 96.745 238.985 97.835 ;
        RECT 239.155 96.745 240.365 97.835 ;
        RECT 240.535 96.745 240.825 97.910 ;
        RECT 242.815 97.835 244.505 98.355 ;
        RECT 244.675 98.025 245.030 98.395 ;
        RECT 245.310 98.385 245.480 98.575 ;
        RECT 245.650 98.550 245.905 99.125 ;
        RECT 245.310 98.055 245.565 98.385 ;
        RECT 245.310 97.845 245.480 98.055 ;
        RECT 240.995 96.745 244.505 97.835 ;
        RECT 244.765 97.675 245.480 97.845 ;
        RECT 245.735 97.820 245.905 98.550 ;
        RECT 246.080 98.455 246.340 99.295 ;
        RECT 246.515 98.545 247.725 99.295 ;
        RECT 244.765 96.915 244.935 97.675 ;
        RECT 245.150 96.745 245.480 97.505 ;
        RECT 245.650 96.915 245.905 97.820 ;
        RECT 246.080 96.745 246.340 97.895 ;
        RECT 246.515 97.835 247.035 98.375 ;
        RECT 247.205 98.005 247.725 98.545 ;
        RECT 246.515 96.745 247.725 97.835 ;
        RECT 188.930 96.575 247.810 96.745 ;
        RECT 69.820 95.250 75.430 95.420 ;
        RECT 64.750 94.980 67.350 95.150 ;
        RECT 64.750 92.930 64.920 94.980 ;
        RECT 65.550 94.470 66.550 94.640 ;
        RECT 65.320 93.610 65.490 94.300 ;
        RECT 66.610 93.610 66.780 94.300 ;
        RECT 65.550 93.270 66.550 93.440 ;
        RECT 67.180 92.930 67.350 94.980 ;
        RECT 64.750 92.760 67.350 92.930 ;
        RECT 69.820 92.990 69.990 95.250 ;
        RECT 70.670 94.680 74.580 94.850 ;
        RECT 70.330 93.620 70.500 94.620 ;
        RECT 74.750 93.620 74.920 94.620 ;
        RECT 70.670 93.390 74.580 93.560 ;
        RECT 75.260 92.990 75.430 95.250 ;
        RECT 69.820 92.820 75.430 92.990 ;
        RECT 77.490 92.920 77.660 96.470 ;
        RECT 78.340 95.900 81.630 96.070 ;
        RECT 78.000 94.840 78.170 95.840 ;
        RECT 81.800 94.840 81.970 95.840 ;
        RECT 78.340 94.610 81.630 94.780 ;
        RECT 78.000 93.550 78.170 94.550 ;
        RECT 81.800 93.550 81.970 94.550 ;
        RECT 78.340 93.320 81.630 93.490 ;
        RECT 82.310 92.920 82.480 96.470 ;
        RECT 138.630 95.990 143.620 96.160 ;
        RECT 130.960 94.770 136.570 94.940 ;
        RECT 77.490 92.750 82.480 92.920 ;
        RECT 125.890 94.500 128.490 94.670 ;
        RECT 125.890 92.450 126.060 94.500 ;
        RECT 126.690 93.990 127.690 94.160 ;
        RECT 126.460 93.130 126.630 93.820 ;
        RECT 127.750 93.130 127.920 93.820 ;
        RECT 126.690 92.790 127.690 92.960 ;
        RECT 128.320 92.450 128.490 94.500 ;
        RECT 125.890 92.280 128.490 92.450 ;
        RECT 130.960 92.510 131.130 94.770 ;
        RECT 131.810 94.200 135.720 94.370 ;
        RECT 131.470 93.140 131.640 94.140 ;
        RECT 135.890 93.140 136.060 94.140 ;
        RECT 131.810 92.910 135.720 93.080 ;
        RECT 136.400 92.510 136.570 94.770 ;
        RECT 130.960 92.340 136.570 92.510 ;
        RECT 138.630 92.440 138.800 95.990 ;
        RECT 139.480 95.420 142.770 95.590 ;
        RECT 139.140 94.360 139.310 95.360 ;
        RECT 142.940 94.360 143.110 95.360 ;
        RECT 139.480 94.130 142.770 94.300 ;
        RECT 139.140 93.070 139.310 94.070 ;
        RECT 142.940 93.070 143.110 94.070 ;
        RECT 139.480 92.840 142.770 93.010 ;
        RECT 143.450 92.440 143.620 95.990 ;
        RECT 189.015 95.485 190.225 96.575 ;
        RECT 190.395 96.140 195.740 96.575 ;
        RECT 195.915 96.140 201.260 96.575 ;
        RECT 177.220 94.830 179.960 95.000 ;
        RECT 177.220 93.420 177.390 94.830 ;
        RECT 177.730 93.960 177.900 94.290 ;
        RECT 178.070 94.260 179.110 94.430 ;
        RECT 178.070 93.820 179.110 93.990 ;
        RECT 179.280 93.960 179.450 94.290 ;
        RECT 179.790 93.420 179.960 94.830 ;
        RECT 189.015 94.775 189.535 95.315 ;
        RECT 189.705 94.945 190.225 95.485 ;
        RECT 189.015 94.025 190.225 94.775 ;
        RECT 191.980 94.570 192.320 95.400 ;
        RECT 193.800 94.890 194.150 96.140 ;
        RECT 197.500 94.570 197.840 95.400 ;
        RECT 199.320 94.890 199.670 96.140 ;
        RECT 201.895 95.410 202.185 96.575 ;
        RECT 202.355 96.140 207.700 96.575 ;
        RECT 207.875 96.140 213.220 96.575 ;
        RECT 213.395 96.140 218.740 96.575 ;
        RECT 218.915 96.140 224.260 96.575 ;
        RECT 190.395 94.025 195.740 94.570 ;
        RECT 195.915 94.025 201.260 94.570 ;
        RECT 201.895 94.025 202.185 94.750 ;
        RECT 203.940 94.570 204.280 95.400 ;
        RECT 205.760 94.890 206.110 96.140 ;
        RECT 209.460 94.570 209.800 95.400 ;
        RECT 211.280 94.890 211.630 96.140 ;
        RECT 214.980 94.570 215.320 95.400 ;
        RECT 216.800 94.890 217.150 96.140 ;
        RECT 220.500 94.570 220.840 95.400 ;
        RECT 222.320 94.890 222.670 96.140 ;
        RECT 224.435 95.485 227.025 96.575 ;
        RECT 224.435 94.795 225.645 95.315 ;
        RECT 225.815 94.965 227.025 95.485 ;
        RECT 227.655 95.410 227.945 96.575 ;
        RECT 229.035 96.065 229.335 96.575 ;
        RECT 229.505 95.895 229.835 96.405 ;
        RECT 230.005 96.065 230.635 96.575 ;
        RECT 231.215 96.065 231.595 96.235 ;
        RECT 231.765 96.065 232.065 96.575 ;
        RECT 232.255 96.140 237.600 96.575 ;
        RECT 237.775 96.140 243.120 96.575 ;
        RECT 231.425 95.895 231.595 96.065 ;
        RECT 229.035 95.725 231.255 95.895 ;
        RECT 202.355 94.025 207.700 94.570 ;
        RECT 207.875 94.025 213.220 94.570 ;
        RECT 213.395 94.025 218.740 94.570 ;
        RECT 218.915 94.025 224.260 94.570 ;
        RECT 224.435 94.025 227.025 94.795 ;
        RECT 229.035 94.765 229.205 95.725 ;
        RECT 229.375 95.385 230.915 95.555 ;
        RECT 229.375 94.935 229.620 95.385 ;
        RECT 229.880 95.015 230.575 95.215 ;
        RECT 230.745 95.185 230.915 95.385 ;
        RECT 231.085 95.525 231.255 95.725 ;
        RECT 231.425 95.695 232.085 95.895 ;
        RECT 231.085 95.355 231.745 95.525 ;
        RECT 230.745 95.015 231.345 95.185 ;
        RECT 231.575 94.935 231.745 95.355 ;
        RECT 227.655 94.025 227.945 94.750 ;
        RECT 229.035 94.220 229.500 94.765 ;
        RECT 230.005 94.025 230.175 94.845 ;
        RECT 230.345 94.765 231.255 94.845 ;
        RECT 231.915 94.765 232.085 95.695 ;
        RECT 230.345 94.675 231.595 94.765 ;
        RECT 230.345 94.195 230.675 94.675 ;
        RECT 231.085 94.595 231.595 94.675 ;
        RECT 230.845 94.025 231.195 94.415 ;
        RECT 231.365 94.195 231.595 94.595 ;
        RECT 231.765 94.285 232.085 94.765 ;
        RECT 233.840 94.570 234.180 95.400 ;
        RECT 235.660 94.890 236.010 96.140 ;
        RECT 239.360 94.570 239.700 95.400 ;
        RECT 241.180 94.890 241.530 96.140 ;
        RECT 243.295 95.485 245.885 96.575 ;
        RECT 243.295 94.795 244.505 95.315 ;
        RECT 244.675 94.965 245.885 95.485 ;
        RECT 246.515 95.485 247.725 96.575 ;
        RECT 246.515 94.945 247.035 95.485 ;
        RECT 232.255 94.025 237.600 94.570 ;
        RECT 237.775 94.025 243.120 94.570 ;
        RECT 243.295 94.025 245.885 94.795 ;
        RECT 247.205 94.775 247.725 95.315 ;
        RECT 246.515 94.025 247.725 94.775 ;
        RECT 188.930 93.855 247.810 94.025 ;
        RECT 177.220 93.250 179.960 93.420 ;
        RECT 189.015 93.105 190.225 93.855 ;
        RECT 190.395 93.310 195.740 93.855 ;
        RECT 195.915 93.310 201.260 93.855 ;
        RECT 201.435 93.310 206.780 93.855 ;
        RECT 206.955 93.310 212.300 93.855 ;
        RECT 189.015 92.565 189.535 93.105 ;
        RECT 138.630 92.270 143.620 92.440 ;
        RECT 189.705 92.395 190.225 92.935 ;
        RECT 191.980 92.480 192.320 93.310 ;
        RECT 189.015 91.305 190.225 92.395 ;
        RECT 193.800 91.740 194.150 92.990 ;
        RECT 197.500 92.480 197.840 93.310 ;
        RECT 199.320 91.740 199.670 92.990 ;
        RECT 203.020 92.480 203.360 93.310 ;
        RECT 204.840 91.740 205.190 92.990 ;
        RECT 208.540 92.480 208.880 93.310 ;
        RECT 212.475 93.085 214.145 93.855 ;
        RECT 214.775 93.130 215.065 93.855 ;
        RECT 215.235 93.310 220.580 93.855 ;
        RECT 210.360 91.740 210.710 92.990 ;
        RECT 212.475 92.565 213.225 93.085 ;
        RECT 213.395 92.395 214.145 92.915 ;
        RECT 216.820 92.480 217.160 93.310 ;
        RECT 220.755 93.085 224.265 93.855 ;
        RECT 225.360 93.145 225.615 93.675 ;
        RECT 225.785 93.395 226.090 93.855 ;
        RECT 226.335 93.475 227.405 93.645 ;
        RECT 190.395 91.305 195.740 91.740 ;
        RECT 195.915 91.305 201.260 91.740 ;
        RECT 201.435 91.305 206.780 91.740 ;
        RECT 206.955 91.305 212.300 91.740 ;
        RECT 212.475 91.305 214.145 92.395 ;
        RECT 214.775 91.305 215.065 92.470 ;
        RECT 218.640 91.740 218.990 92.990 ;
        RECT 220.755 92.565 222.405 93.085 ;
        RECT 222.575 92.395 224.265 92.915 ;
        RECT 215.235 91.305 220.580 91.740 ;
        RECT 220.755 91.305 224.265 92.395 ;
        RECT 225.360 92.495 225.570 93.145 ;
        RECT 226.335 93.120 226.655 93.475 ;
        RECT 226.330 92.945 226.655 93.120 ;
        RECT 225.740 92.645 226.655 92.945 ;
        RECT 226.825 92.905 227.065 93.305 ;
        RECT 227.235 93.245 227.405 93.475 ;
        RECT 227.575 93.415 227.765 93.855 ;
        RECT 227.935 93.405 228.885 93.685 ;
        RECT 229.105 93.495 229.455 93.665 ;
        RECT 227.235 93.075 227.765 93.245 ;
        RECT 225.740 92.615 226.480 92.645 ;
        RECT 225.360 91.615 225.615 92.495 ;
        RECT 225.785 91.305 226.090 92.445 ;
        RECT 226.310 92.025 226.480 92.615 ;
        RECT 226.825 92.535 227.365 92.905 ;
        RECT 227.545 92.795 227.765 93.075 ;
        RECT 227.935 92.625 228.105 93.405 ;
        RECT 227.700 92.455 228.105 92.625 ;
        RECT 228.275 92.615 228.625 93.235 ;
        RECT 227.700 92.365 227.870 92.455 ;
        RECT 228.795 92.445 229.005 93.235 ;
        RECT 226.650 92.195 227.870 92.365 ;
        RECT 228.330 92.285 229.005 92.445 ;
        RECT 226.310 91.855 227.110 92.025 ;
        RECT 226.430 91.305 226.760 91.685 ;
        RECT 226.940 91.565 227.110 91.855 ;
        RECT 227.700 91.815 227.870 92.195 ;
        RECT 228.040 92.275 229.005 92.285 ;
        RECT 229.195 93.105 229.455 93.495 ;
        RECT 229.665 93.395 229.995 93.855 ;
        RECT 230.870 93.465 231.725 93.635 ;
        RECT 231.930 93.465 232.425 93.635 ;
        RECT 232.595 93.495 232.925 93.855 ;
        RECT 229.195 92.415 229.365 93.105 ;
        RECT 229.535 92.755 229.705 92.935 ;
        RECT 229.875 92.925 230.665 93.175 ;
        RECT 230.870 92.755 231.040 93.465 ;
        RECT 231.210 92.955 231.565 93.175 ;
        RECT 229.535 92.585 231.225 92.755 ;
        RECT 228.040 91.985 228.500 92.275 ;
        RECT 229.195 92.245 230.695 92.415 ;
        RECT 229.195 92.105 229.365 92.245 ;
        RECT 228.805 91.935 229.365 92.105 ;
        RECT 227.280 91.305 227.530 91.765 ;
        RECT 227.700 91.475 228.570 91.815 ;
        RECT 228.805 91.475 228.975 91.935 ;
        RECT 229.810 91.905 230.885 92.075 ;
        RECT 229.145 91.305 229.515 91.765 ;
        RECT 229.810 91.565 229.980 91.905 ;
        RECT 230.150 91.305 230.480 91.735 ;
        RECT 230.715 91.565 230.885 91.905 ;
        RECT 231.055 91.805 231.225 92.585 ;
        RECT 231.395 92.365 231.565 92.955 ;
        RECT 231.735 92.555 232.085 93.175 ;
        RECT 231.395 91.975 231.860 92.365 ;
        RECT 232.255 92.105 232.425 93.465 ;
        RECT 232.595 92.275 233.055 93.325 ;
        RECT 232.030 91.935 232.425 92.105 ;
        RECT 232.030 91.805 232.200 91.935 ;
        RECT 231.055 91.475 231.735 91.805 ;
        RECT 231.950 91.475 232.200 91.805 ;
        RECT 232.370 91.305 232.620 91.765 ;
        RECT 232.790 91.490 233.115 92.275 ;
        RECT 233.285 91.475 233.455 93.595 ;
        RECT 233.625 93.475 233.955 93.855 ;
        RECT 234.125 93.305 234.380 93.595 ;
        RECT 234.555 93.310 239.900 93.855 ;
        RECT 233.630 93.135 234.380 93.305 ;
        RECT 233.630 92.145 233.860 93.135 ;
        RECT 234.030 92.315 234.380 92.965 ;
        RECT 236.140 92.480 236.480 93.310 ;
        RECT 240.535 93.130 240.825 93.855 ;
        RECT 240.995 93.085 244.505 93.855 ;
        RECT 244.765 93.305 244.935 93.685 ;
        RECT 245.150 93.475 245.480 93.855 ;
        RECT 244.765 93.135 245.480 93.305 ;
        RECT 233.630 91.975 234.380 92.145 ;
        RECT 233.625 91.305 233.955 91.805 ;
        RECT 234.125 91.475 234.380 91.975 ;
        RECT 237.960 91.740 238.310 92.990 ;
        RECT 240.995 92.565 242.645 93.085 ;
        RECT 234.555 91.305 239.900 91.740 ;
        RECT 240.535 91.305 240.825 92.470 ;
        RECT 242.815 92.395 244.505 92.915 ;
        RECT 244.675 92.585 245.030 92.955 ;
        RECT 245.310 92.945 245.480 93.135 ;
        RECT 245.650 93.110 245.905 93.685 ;
        RECT 245.310 92.615 245.565 92.945 ;
        RECT 245.310 92.405 245.480 92.615 ;
        RECT 240.995 91.305 244.505 92.395 ;
        RECT 244.765 92.235 245.480 92.405 ;
        RECT 245.735 92.380 245.905 93.110 ;
        RECT 246.080 93.015 246.340 93.855 ;
        RECT 246.515 93.105 247.725 93.855 ;
        RECT 244.765 91.475 244.935 92.235 ;
        RECT 245.150 91.305 245.480 92.065 ;
        RECT 245.650 91.475 245.905 92.380 ;
        RECT 246.080 91.305 246.340 92.455 ;
        RECT 246.515 92.395 247.035 92.935 ;
        RECT 247.205 92.565 247.725 93.105 ;
        RECT 246.515 91.305 247.725 92.395 ;
        RECT 188.930 91.135 247.810 91.305 ;
        RECT 189.015 90.045 190.225 91.135 ;
        RECT 190.395 90.700 195.740 91.135 ;
        RECT 195.915 90.700 201.260 91.135 ;
        RECT 189.015 89.335 189.535 89.875 ;
        RECT 189.705 89.505 190.225 90.045 ;
        RECT 176.760 88.510 180.590 88.680 ;
        RECT 189.015 88.585 190.225 89.335 ;
        RECT 191.980 89.130 192.320 89.960 ;
        RECT 193.800 89.450 194.150 90.700 ;
        RECT 197.500 89.130 197.840 89.960 ;
        RECT 199.320 89.450 199.670 90.700 ;
        RECT 201.895 89.970 202.185 91.135 ;
        RECT 202.355 90.700 207.700 91.135 ;
        RECT 207.875 90.700 213.220 91.135 ;
        RECT 213.395 90.700 218.740 91.135 ;
        RECT 218.915 90.700 224.260 91.135 ;
        RECT 190.395 88.585 195.740 89.130 ;
        RECT 195.915 88.585 201.260 89.130 ;
        RECT 201.895 88.585 202.185 89.310 ;
        RECT 203.940 89.130 204.280 89.960 ;
        RECT 205.760 89.450 206.110 90.700 ;
        RECT 209.460 89.130 209.800 89.960 ;
        RECT 211.280 89.450 211.630 90.700 ;
        RECT 214.980 89.130 215.320 89.960 ;
        RECT 216.800 89.450 217.150 90.700 ;
        RECT 220.500 89.130 220.840 89.960 ;
        RECT 222.320 89.450 222.670 90.700 ;
        RECT 224.435 90.045 227.025 91.135 ;
        RECT 224.435 89.355 225.645 89.875 ;
        RECT 225.815 89.525 227.025 90.045 ;
        RECT 227.655 89.970 227.945 91.135 ;
        RECT 229.045 90.325 229.340 91.135 ;
        RECT 229.520 89.825 229.765 90.965 ;
        RECT 229.940 90.325 230.200 91.135 ;
        RECT 230.800 91.130 237.075 91.135 ;
        RECT 230.380 89.825 230.630 90.960 ;
        RECT 230.800 90.335 231.060 91.130 ;
        RECT 231.230 90.235 231.490 90.960 ;
        RECT 231.660 90.405 231.920 91.130 ;
        RECT 232.090 90.235 232.350 90.960 ;
        RECT 232.520 90.405 232.780 91.130 ;
        RECT 232.950 90.235 233.210 90.960 ;
        RECT 233.380 90.405 233.640 91.130 ;
        RECT 233.810 90.235 234.070 90.960 ;
        RECT 234.240 90.405 234.485 91.130 ;
        RECT 234.655 90.235 234.915 90.960 ;
        RECT 235.100 90.405 235.345 91.130 ;
        RECT 235.515 90.235 235.775 90.960 ;
        RECT 235.960 90.405 236.205 91.130 ;
        RECT 236.375 90.235 236.635 90.960 ;
        RECT 236.820 90.405 237.075 91.130 ;
        RECT 231.230 90.220 236.635 90.235 ;
        RECT 237.245 90.220 237.535 90.960 ;
        RECT 237.705 90.390 237.975 91.135 ;
        RECT 238.235 90.700 243.580 91.135 ;
        RECT 231.230 89.995 237.975 90.220 ;
        RECT 202.355 88.585 207.700 89.130 ;
        RECT 207.875 88.585 213.220 89.130 ;
        RECT 213.395 88.585 218.740 89.130 ;
        RECT 218.915 88.585 224.260 89.130 ;
        RECT 224.435 88.585 227.025 89.355 ;
        RECT 227.655 88.585 227.945 89.310 ;
        RECT 229.035 89.265 229.350 89.825 ;
        RECT 229.520 89.575 236.640 89.825 ;
        RECT 229.035 88.585 229.340 89.095 ;
        RECT 229.520 88.765 229.770 89.575 ;
        RECT 229.940 88.585 230.200 89.110 ;
        RECT 230.380 88.765 230.630 89.575 ;
        RECT 236.810 89.405 237.975 89.995 ;
        RECT 231.230 89.235 237.975 89.405 ;
        RECT 230.800 88.585 231.060 89.145 ;
        RECT 231.230 88.780 231.490 89.235 ;
        RECT 231.660 88.585 231.920 89.065 ;
        RECT 232.090 88.780 232.350 89.235 ;
        RECT 232.520 88.585 232.780 89.065 ;
        RECT 232.950 88.780 233.210 89.235 ;
        RECT 233.380 88.585 233.625 89.065 ;
        RECT 233.795 88.780 234.070 89.235 ;
        RECT 234.240 88.585 234.485 89.065 ;
        RECT 234.655 88.780 234.915 89.235 ;
        RECT 235.095 88.585 235.345 89.065 ;
        RECT 235.515 88.780 235.775 89.235 ;
        RECT 235.955 88.585 236.205 89.065 ;
        RECT 236.375 88.780 236.635 89.235 ;
        RECT 236.815 88.585 237.075 89.065 ;
        RECT 237.245 88.780 237.505 89.235 ;
        RECT 239.820 89.130 240.160 89.960 ;
        RECT 241.640 89.450 241.990 90.700 ;
        RECT 243.755 90.045 246.345 91.135 ;
        RECT 243.755 89.355 244.965 89.875 ;
        RECT 245.135 89.525 246.345 90.045 ;
        RECT 246.515 90.045 247.725 91.135 ;
        RECT 246.515 89.505 247.035 90.045 ;
        RECT 237.675 88.585 237.975 89.065 ;
        RECT 238.235 88.585 243.580 89.130 ;
        RECT 243.755 88.585 246.345 89.355 ;
        RECT 247.205 89.335 247.725 89.875 ;
        RECT 246.515 88.585 247.725 89.335 ;
        RECT 176.760 87.100 176.930 88.510 ;
        RECT 177.270 87.640 177.440 87.970 ;
        RECT 177.655 87.940 179.695 88.110 ;
        RECT 177.655 87.500 179.695 87.670 ;
        RECT 179.910 87.640 180.080 87.970 ;
        RECT 180.420 87.100 180.590 88.510 ;
        RECT 188.930 88.415 247.810 88.585 ;
        RECT 189.015 87.665 190.225 88.415 ;
        RECT 190.395 87.870 195.740 88.415 ;
        RECT 195.915 87.870 201.260 88.415 ;
        RECT 201.435 87.870 206.780 88.415 ;
        RECT 206.955 87.870 212.300 88.415 ;
        RECT 189.015 87.125 189.535 87.665 ;
        RECT 176.760 86.930 180.590 87.100 ;
        RECT 189.705 86.955 190.225 87.495 ;
        RECT 191.980 87.040 192.320 87.870 ;
        RECT 189.015 85.865 190.225 86.955 ;
        RECT 193.800 86.300 194.150 87.550 ;
        RECT 197.500 87.040 197.840 87.870 ;
        RECT 199.320 86.300 199.670 87.550 ;
        RECT 203.020 87.040 203.360 87.870 ;
        RECT 204.840 86.300 205.190 87.550 ;
        RECT 208.540 87.040 208.880 87.870 ;
        RECT 212.475 87.645 214.145 88.415 ;
        RECT 214.775 87.690 215.065 88.415 ;
        RECT 215.235 87.870 220.580 88.415 ;
        RECT 210.360 86.300 210.710 87.550 ;
        RECT 212.475 87.125 213.225 87.645 ;
        RECT 213.395 86.955 214.145 87.475 ;
        RECT 216.820 87.040 217.160 87.870 ;
        RECT 220.755 87.645 224.265 88.415 ;
        RECT 224.435 87.665 225.645 88.415 ;
        RECT 225.865 88.025 226.195 88.415 ;
        RECT 226.365 87.845 226.535 88.165 ;
        RECT 226.705 88.025 227.035 88.415 ;
        RECT 227.450 88.015 228.405 88.185 ;
        RECT 225.815 87.675 228.065 87.845 ;
        RECT 190.395 85.865 195.740 86.300 ;
        RECT 195.915 85.865 201.260 86.300 ;
        RECT 201.435 85.865 206.780 86.300 ;
        RECT 206.955 85.865 212.300 86.300 ;
        RECT 212.475 85.865 214.145 86.955 ;
        RECT 214.775 85.865 215.065 87.030 ;
        RECT 218.640 86.300 218.990 87.550 ;
        RECT 220.755 87.125 222.405 87.645 ;
        RECT 222.575 86.955 224.265 87.475 ;
        RECT 224.435 87.125 224.955 87.665 ;
        RECT 225.125 86.955 225.645 87.495 ;
        RECT 215.235 85.865 220.580 86.300 ;
        RECT 220.755 85.865 224.265 86.955 ;
        RECT 224.435 85.865 225.645 86.955 ;
        RECT 225.815 86.715 225.985 87.675 ;
        RECT 226.155 87.055 226.400 87.505 ;
        RECT 226.570 87.225 227.120 87.425 ;
        RECT 227.290 87.255 227.665 87.425 ;
        RECT 227.290 87.055 227.460 87.255 ;
        RECT 227.835 87.175 228.065 87.675 ;
        RECT 226.155 86.885 227.460 87.055 ;
        RECT 228.235 87.135 228.405 88.015 ;
        RECT 228.575 87.580 228.865 88.415 ;
        RECT 229.150 87.785 229.435 88.245 ;
        RECT 229.605 87.955 229.875 88.415 ;
        RECT 229.150 87.615 230.105 87.785 ;
        RECT 228.235 86.965 228.865 87.135 ;
        RECT 225.815 86.035 226.195 86.715 ;
        RECT 226.785 85.865 226.955 86.715 ;
        RECT 227.125 86.545 228.365 86.715 ;
        RECT 227.125 86.035 227.455 86.545 ;
        RECT 227.625 85.865 227.795 86.375 ;
        RECT 227.965 86.035 228.365 86.545 ;
        RECT 228.545 86.035 228.865 86.965 ;
        RECT 229.035 86.885 229.725 87.445 ;
        RECT 229.895 86.715 230.105 87.615 ;
        RECT 229.150 86.495 230.105 86.715 ;
        RECT 230.275 87.445 230.675 88.245 ;
        RECT 230.865 87.785 231.145 88.245 ;
        RECT 231.665 87.955 231.990 88.415 ;
        RECT 230.865 87.615 231.990 87.785 ;
        RECT 232.160 87.675 232.545 88.245 ;
        RECT 232.715 87.870 238.060 88.415 ;
        RECT 231.540 87.505 231.990 87.615 ;
        RECT 230.275 86.885 231.370 87.445 ;
        RECT 231.540 87.175 232.095 87.505 ;
        RECT 229.150 86.035 229.435 86.495 ;
        RECT 229.605 85.865 229.875 86.325 ;
        RECT 230.275 86.035 230.675 86.885 ;
        RECT 231.540 86.715 231.990 87.175 ;
        RECT 232.265 87.005 232.545 87.675 ;
        RECT 234.300 87.040 234.640 87.870 ;
        RECT 238.235 87.645 239.905 88.415 ;
        RECT 240.535 87.690 240.825 88.415 ;
        RECT 240.995 87.870 246.340 88.415 ;
        RECT 230.865 86.495 231.990 86.715 ;
        RECT 230.865 86.035 231.145 86.495 ;
        RECT 231.665 85.865 231.990 86.325 ;
        RECT 232.160 86.035 232.545 87.005 ;
        RECT 236.120 86.300 236.470 87.550 ;
        RECT 238.235 87.125 238.985 87.645 ;
        RECT 239.155 86.955 239.905 87.475 ;
        RECT 242.580 87.040 242.920 87.870 ;
        RECT 246.515 87.665 247.725 88.415 ;
        RECT 232.715 85.865 238.060 86.300 ;
        RECT 238.235 85.865 239.905 86.955 ;
        RECT 240.535 85.865 240.825 87.030 ;
        RECT 244.400 86.300 244.750 87.550 ;
        RECT 246.515 86.955 247.035 87.495 ;
        RECT 247.205 87.125 247.725 87.665 ;
        RECT 240.995 85.865 246.340 86.300 ;
        RECT 246.515 85.865 247.725 86.955 ;
        RECT 188.930 85.695 247.810 85.865 ;
        RECT 177.180 85.090 179.920 85.260 ;
        RECT 177.180 83.680 177.350 85.090 ;
        RECT 177.690 84.220 177.860 84.550 ;
        RECT 178.030 84.520 179.070 84.690 ;
        RECT 178.030 84.080 179.070 84.250 ;
        RECT 179.240 84.220 179.410 84.550 ;
        RECT 179.750 83.680 179.920 85.090 ;
        RECT 189.015 84.605 190.225 85.695 ;
        RECT 190.395 85.260 195.740 85.695 ;
        RECT 195.915 85.260 201.260 85.695 ;
        RECT 177.180 83.510 179.920 83.680 ;
        RECT 189.015 83.895 189.535 84.435 ;
        RECT 189.705 84.065 190.225 84.605 ;
        RECT 189.015 83.145 190.225 83.895 ;
        RECT 191.980 83.690 192.320 84.520 ;
        RECT 193.800 84.010 194.150 85.260 ;
        RECT 197.500 83.690 197.840 84.520 ;
        RECT 199.320 84.010 199.670 85.260 ;
        RECT 201.895 84.530 202.185 85.695 ;
        RECT 202.355 85.260 207.700 85.695 ;
        RECT 207.875 85.260 213.220 85.695 ;
        RECT 213.395 85.260 218.740 85.695 ;
        RECT 218.915 85.260 224.260 85.695 ;
        RECT 190.395 83.145 195.740 83.690 ;
        RECT 195.915 83.145 201.260 83.690 ;
        RECT 201.895 83.145 202.185 83.870 ;
        RECT 203.940 83.690 204.280 84.520 ;
        RECT 205.760 84.010 206.110 85.260 ;
        RECT 209.460 83.690 209.800 84.520 ;
        RECT 211.280 84.010 211.630 85.260 ;
        RECT 214.980 83.690 215.320 84.520 ;
        RECT 216.800 84.010 217.150 85.260 ;
        RECT 220.500 83.690 220.840 84.520 ;
        RECT 222.320 84.010 222.670 85.260 ;
        RECT 224.435 84.605 227.025 85.695 ;
        RECT 224.435 83.915 225.645 84.435 ;
        RECT 225.815 84.085 227.025 84.605 ;
        RECT 227.655 84.530 227.945 85.695 ;
        RECT 228.115 85.260 233.460 85.695 ;
        RECT 233.635 85.260 238.980 85.695 ;
        RECT 239.155 85.260 244.500 85.695 ;
        RECT 202.355 83.145 207.700 83.690 ;
        RECT 207.875 83.145 213.220 83.690 ;
        RECT 213.395 83.145 218.740 83.690 ;
        RECT 218.915 83.145 224.260 83.690 ;
        RECT 224.435 83.145 227.025 83.915 ;
        RECT 227.655 83.145 227.945 83.870 ;
        RECT 229.700 83.690 230.040 84.520 ;
        RECT 231.520 84.010 231.870 85.260 ;
        RECT 235.220 83.690 235.560 84.520 ;
        RECT 237.040 84.010 237.390 85.260 ;
        RECT 240.740 83.690 241.080 84.520 ;
        RECT 242.560 84.010 242.910 85.260 ;
        RECT 244.765 84.765 244.935 85.525 ;
        RECT 245.150 84.935 245.480 85.695 ;
        RECT 244.765 84.595 245.480 84.765 ;
        RECT 245.650 84.620 245.905 85.525 ;
        RECT 244.675 84.045 245.030 84.415 ;
        RECT 245.310 84.385 245.480 84.595 ;
        RECT 245.310 84.055 245.565 84.385 ;
        RECT 245.310 83.865 245.480 84.055 ;
        RECT 245.735 83.890 245.905 84.620 ;
        RECT 246.080 84.545 246.340 85.695 ;
        RECT 246.515 84.605 247.725 85.695 ;
        RECT 246.515 84.065 247.035 84.605 ;
        RECT 244.765 83.695 245.480 83.865 ;
        RECT 228.115 83.145 233.460 83.690 ;
        RECT 233.635 83.145 238.980 83.690 ;
        RECT 239.155 83.145 244.500 83.690 ;
        RECT 244.765 83.315 244.935 83.695 ;
        RECT 245.150 83.145 245.480 83.525 ;
        RECT 245.650 83.315 245.905 83.890 ;
        RECT 246.080 83.145 246.340 83.985 ;
        RECT 247.205 83.895 247.725 84.435 ;
        RECT 246.515 83.145 247.725 83.895 ;
        RECT 188.930 82.975 247.810 83.145 ;
        RECT 189.015 82.225 190.225 82.975 ;
        RECT 190.395 82.430 195.740 82.975 ;
        RECT 195.915 82.430 201.260 82.975 ;
        RECT 201.435 82.430 206.780 82.975 ;
        RECT 206.955 82.430 212.300 82.975 ;
        RECT 70.540 81.710 74.200 81.880 ;
        RECT 55.925 80.370 57.575 80.540 ;
        RECT 64.670 81.510 68.330 81.680 ;
        RECT 64.670 72.800 64.840 81.510 ;
        RECT 65.565 80.940 67.435 81.110 ;
        RECT 65.180 79.880 65.350 80.880 ;
        RECT 67.650 79.880 67.820 80.880 ;
        RECT 65.565 79.650 67.435 79.820 ;
        RECT 65.180 78.590 65.350 79.590 ;
        RECT 67.650 78.590 67.820 79.590 ;
        RECT 65.565 78.360 67.435 78.530 ;
        RECT 65.180 77.300 65.350 78.300 ;
        RECT 67.650 77.300 67.820 78.300 ;
        RECT 65.565 77.070 67.435 77.240 ;
        RECT 65.180 76.010 65.350 77.010 ;
        RECT 67.650 76.010 67.820 77.010 ;
        RECT 65.565 75.780 67.435 75.950 ;
        RECT 65.180 74.720 65.350 75.720 ;
        RECT 67.650 74.720 67.820 75.720 ;
        RECT 65.565 74.490 67.435 74.660 ;
        RECT 65.180 73.430 65.350 74.430 ;
        RECT 67.650 73.430 67.820 74.430 ;
        RECT 65.565 73.200 67.435 73.370 ;
        RECT 68.160 72.800 68.330 81.510 ;
        RECT 70.540 73.000 70.710 81.710 ;
        RECT 71.435 81.140 73.305 81.310 ;
        RECT 71.050 80.080 71.220 81.080 ;
        RECT 73.520 80.080 73.690 81.080 ;
        RECT 71.435 79.850 73.305 80.020 ;
        RECT 71.050 78.790 71.220 79.790 ;
        RECT 73.520 78.790 73.690 79.790 ;
        RECT 71.435 78.560 73.305 78.730 ;
        RECT 71.050 77.500 71.220 78.500 ;
        RECT 73.520 77.500 73.690 78.500 ;
        RECT 71.435 77.270 73.305 77.440 ;
        RECT 71.050 76.210 71.220 77.210 ;
        RECT 73.520 76.210 73.690 77.210 ;
        RECT 71.435 75.980 73.305 76.150 ;
        RECT 71.050 74.920 71.220 75.920 ;
        RECT 73.520 74.920 73.690 75.920 ;
        RECT 71.435 74.690 73.305 74.860 ;
        RECT 71.050 73.630 71.220 74.630 ;
        RECT 73.520 73.630 73.690 74.630 ;
        RECT 71.435 73.400 73.305 73.570 ;
        RECT 74.030 73.000 74.200 81.710 ;
        RECT 76.610 81.520 90.820 81.690 ;
        RECT 189.015 81.685 189.535 82.225 ;
        RECT 76.610 73.530 76.780 81.520 ;
        RECT 77.410 81.010 78.410 81.180 ;
        RECT 78.700 81.010 79.700 81.180 ;
        RECT 79.990 81.010 80.990 81.180 ;
        RECT 81.280 81.010 82.280 81.180 ;
        RECT 82.570 81.010 83.570 81.180 ;
        RECT 83.860 81.010 84.860 81.180 ;
        RECT 85.150 81.010 86.150 81.180 ;
        RECT 86.440 81.010 87.440 81.180 ;
        RECT 87.730 81.010 88.730 81.180 ;
        RECT 89.020 81.010 90.020 81.180 ;
        RECT 77.180 74.255 77.350 80.795 ;
        RECT 78.470 74.255 78.640 80.795 ;
        RECT 79.760 74.255 79.930 80.795 ;
        RECT 81.050 74.255 81.220 80.795 ;
        RECT 82.340 74.255 82.510 80.795 ;
        RECT 83.630 74.255 83.800 80.795 ;
        RECT 84.920 74.255 85.090 80.795 ;
        RECT 86.210 74.255 86.380 80.795 ;
        RECT 87.500 74.255 87.670 80.795 ;
        RECT 88.790 74.255 88.960 80.795 ;
        RECT 90.080 74.255 90.250 80.795 ;
        RECT 77.410 73.870 78.410 74.040 ;
        RECT 78.700 73.870 79.700 74.040 ;
        RECT 79.990 73.870 80.990 74.040 ;
        RECT 81.280 73.870 82.280 74.040 ;
        RECT 82.570 73.870 83.570 74.040 ;
        RECT 83.860 73.870 84.860 74.040 ;
        RECT 85.150 73.870 86.150 74.040 ;
        RECT 86.440 73.870 87.440 74.040 ;
        RECT 87.730 73.870 88.730 74.040 ;
        RECT 89.020 73.870 90.020 74.040 ;
        RECT 90.650 73.530 90.820 81.520 ;
        RECT 189.705 81.515 190.225 82.055 ;
        RECT 191.980 81.600 192.320 82.430 ;
        RECT 189.015 80.425 190.225 81.515 ;
        RECT 193.800 80.860 194.150 82.110 ;
        RECT 197.500 81.600 197.840 82.430 ;
        RECT 199.320 80.860 199.670 82.110 ;
        RECT 203.020 81.600 203.360 82.430 ;
        RECT 204.840 80.860 205.190 82.110 ;
        RECT 208.540 81.600 208.880 82.430 ;
        RECT 212.475 82.205 214.145 82.975 ;
        RECT 214.775 82.250 215.065 82.975 ;
        RECT 215.235 82.430 220.580 82.975 ;
        RECT 220.755 82.430 226.100 82.975 ;
        RECT 210.360 80.860 210.710 82.110 ;
        RECT 212.475 81.685 213.225 82.205 ;
        RECT 213.395 81.515 214.145 82.035 ;
        RECT 216.820 81.600 217.160 82.430 ;
        RECT 190.395 80.425 195.740 80.860 ;
        RECT 195.915 80.425 201.260 80.860 ;
        RECT 201.435 80.425 206.780 80.860 ;
        RECT 206.955 80.425 212.300 80.860 ;
        RECT 212.475 80.425 214.145 81.515 ;
        RECT 214.775 80.425 215.065 81.590 ;
        RECT 218.640 80.860 218.990 82.110 ;
        RECT 222.340 81.600 222.680 82.430 ;
        RECT 226.275 82.205 229.785 82.975 ;
        RECT 229.955 82.225 231.165 82.975 ;
        RECT 231.340 82.265 231.595 82.795 ;
        RECT 231.765 82.515 232.070 82.975 ;
        RECT 232.315 82.595 233.385 82.765 ;
        RECT 224.160 80.860 224.510 82.110 ;
        RECT 226.275 81.685 227.925 82.205 ;
        RECT 228.095 81.515 229.785 82.035 ;
        RECT 229.955 81.685 230.475 82.225 ;
        RECT 230.645 81.515 231.165 82.055 ;
        RECT 215.235 80.425 220.580 80.860 ;
        RECT 220.755 80.425 226.100 80.860 ;
        RECT 226.275 80.425 229.785 81.515 ;
        RECT 229.955 80.425 231.165 81.515 ;
        RECT 231.340 81.615 231.550 82.265 ;
        RECT 232.315 82.240 232.635 82.595 ;
        RECT 232.310 82.065 232.635 82.240 ;
        RECT 231.720 81.765 232.635 82.065 ;
        RECT 232.805 82.025 233.045 82.425 ;
        RECT 233.215 82.365 233.385 82.595 ;
        RECT 233.555 82.535 233.745 82.975 ;
        RECT 233.915 82.525 234.865 82.805 ;
        RECT 235.085 82.615 235.435 82.785 ;
        RECT 233.215 82.195 233.745 82.365 ;
        RECT 231.720 81.735 232.460 81.765 ;
        RECT 231.340 80.735 231.595 81.615 ;
        RECT 231.765 80.425 232.070 81.565 ;
        RECT 232.290 81.145 232.460 81.735 ;
        RECT 232.805 81.655 233.345 82.025 ;
        RECT 233.525 81.915 233.745 82.195 ;
        RECT 233.915 81.745 234.085 82.525 ;
        RECT 233.680 81.575 234.085 81.745 ;
        RECT 234.255 81.735 234.605 82.355 ;
        RECT 233.680 81.485 233.850 81.575 ;
        RECT 234.775 81.565 234.985 82.355 ;
        RECT 232.630 81.315 233.850 81.485 ;
        RECT 234.310 81.405 234.985 81.565 ;
        RECT 232.290 80.975 233.090 81.145 ;
        RECT 232.410 80.425 232.740 80.805 ;
        RECT 232.920 80.685 233.090 80.975 ;
        RECT 233.680 80.935 233.850 81.315 ;
        RECT 234.020 81.395 234.985 81.405 ;
        RECT 235.175 82.225 235.435 82.615 ;
        RECT 235.645 82.515 235.975 82.975 ;
        RECT 236.850 82.585 237.705 82.755 ;
        RECT 237.910 82.585 238.405 82.755 ;
        RECT 238.575 82.615 238.905 82.975 ;
        RECT 235.175 81.535 235.345 82.225 ;
        RECT 235.515 81.875 235.685 82.055 ;
        RECT 235.855 82.045 236.645 82.295 ;
        RECT 236.850 81.875 237.020 82.585 ;
        RECT 237.190 82.075 237.545 82.295 ;
        RECT 235.515 81.705 237.205 81.875 ;
        RECT 234.020 81.105 234.480 81.395 ;
        RECT 235.175 81.365 236.675 81.535 ;
        RECT 235.175 81.225 235.345 81.365 ;
        RECT 234.785 81.055 235.345 81.225 ;
        RECT 233.260 80.425 233.510 80.885 ;
        RECT 233.680 80.595 234.550 80.935 ;
        RECT 234.785 80.595 234.955 81.055 ;
        RECT 235.790 81.025 236.865 81.195 ;
        RECT 235.125 80.425 235.495 80.885 ;
        RECT 235.790 80.685 235.960 81.025 ;
        RECT 236.130 80.425 236.460 80.855 ;
        RECT 236.695 80.685 236.865 81.025 ;
        RECT 237.035 80.925 237.205 81.705 ;
        RECT 237.375 81.485 237.545 82.075 ;
        RECT 237.715 81.675 238.065 82.295 ;
        RECT 237.375 81.095 237.840 81.485 ;
        RECT 238.235 81.225 238.405 82.585 ;
        RECT 238.575 81.395 239.035 82.445 ;
        RECT 238.010 81.055 238.405 81.225 ;
        RECT 238.010 80.925 238.180 81.055 ;
        RECT 237.035 80.595 237.715 80.925 ;
        RECT 237.930 80.595 238.180 80.925 ;
        RECT 238.350 80.425 238.600 80.885 ;
        RECT 238.770 80.610 239.095 81.395 ;
        RECT 239.265 80.595 239.435 82.715 ;
        RECT 239.605 82.595 239.935 82.975 ;
        RECT 240.105 82.425 240.360 82.715 ;
        RECT 239.610 82.255 240.360 82.425 ;
        RECT 239.610 81.265 239.840 82.255 ;
        RECT 240.535 82.250 240.825 82.975 ;
        RECT 240.995 82.430 246.340 82.975 ;
        RECT 240.010 81.435 240.360 82.085 ;
        RECT 242.580 81.600 242.920 82.430 ;
        RECT 246.515 82.225 247.725 82.975 ;
        RECT 239.610 81.095 240.360 81.265 ;
        RECT 239.605 80.425 239.935 80.925 ;
        RECT 240.105 80.595 240.360 81.095 ;
        RECT 240.535 80.425 240.825 81.590 ;
        RECT 244.400 80.860 244.750 82.110 ;
        RECT 246.515 81.515 247.035 82.055 ;
        RECT 247.205 81.685 247.725 82.225 ;
        RECT 240.995 80.425 246.340 80.860 ;
        RECT 246.515 80.425 247.725 81.515 ;
        RECT 188.930 80.255 247.810 80.425 ;
        RECT 131.100 80.060 134.760 80.230 ;
        RECT 76.610 73.360 90.820 73.530 ;
        RECT 125.230 79.860 128.890 80.030 ;
        RECT 70.540 72.830 74.200 73.000 ;
        RECT 64.670 72.630 68.330 72.800 ;
        RECT 81.820 71.500 88.450 71.670 ;
        RECT 65.340 71.060 67.440 71.230 ;
        RECT 65.340 68.660 65.510 71.060 ;
        RECT 66.140 70.550 66.640 70.720 ;
        RECT 65.910 69.340 66.080 70.380 ;
        RECT 66.700 69.340 66.870 70.380 ;
        RECT 66.140 69.000 66.640 69.170 ;
        RECT 67.270 68.660 67.440 71.060 ;
        RECT 65.340 68.490 67.440 68.660 ;
        RECT 71.150 71.060 73.250 71.230 ;
        RECT 71.150 68.660 71.320 71.060 ;
        RECT 71.950 70.550 72.450 70.720 ;
        RECT 71.720 69.340 71.890 70.380 ;
        RECT 72.510 69.340 72.680 70.380 ;
        RECT 71.950 69.000 72.450 69.170 ;
        RECT 73.080 68.660 73.250 71.060 ;
        RECT 81.820 70.190 81.990 71.500 ;
        RECT 82.470 70.670 84.630 71.020 ;
        RECT 85.640 70.670 87.800 71.020 ;
        RECT 88.280 70.190 88.450 71.500 ;
        RECT 125.230 71.150 125.400 79.860 ;
        RECT 126.125 79.290 127.995 79.460 ;
        RECT 125.740 78.230 125.910 79.230 ;
        RECT 128.210 78.230 128.380 79.230 ;
        RECT 126.125 78.000 127.995 78.170 ;
        RECT 125.740 76.940 125.910 77.940 ;
        RECT 128.210 76.940 128.380 77.940 ;
        RECT 126.125 76.710 127.995 76.880 ;
        RECT 125.740 75.650 125.910 76.650 ;
        RECT 128.210 75.650 128.380 76.650 ;
        RECT 126.125 75.420 127.995 75.590 ;
        RECT 125.740 74.360 125.910 75.360 ;
        RECT 128.210 74.360 128.380 75.360 ;
        RECT 126.125 74.130 127.995 74.300 ;
        RECT 125.740 73.070 125.910 74.070 ;
        RECT 128.210 73.070 128.380 74.070 ;
        RECT 126.125 72.840 127.995 73.010 ;
        RECT 125.740 71.780 125.910 72.780 ;
        RECT 128.210 71.780 128.380 72.780 ;
        RECT 126.125 71.550 127.995 71.720 ;
        RECT 128.720 71.150 128.890 79.860 ;
        RECT 131.100 71.350 131.270 80.060 ;
        RECT 131.995 79.490 133.865 79.660 ;
        RECT 131.610 78.430 131.780 79.430 ;
        RECT 134.080 78.430 134.250 79.430 ;
        RECT 131.995 78.200 133.865 78.370 ;
        RECT 131.610 77.140 131.780 78.140 ;
        RECT 134.080 77.140 134.250 78.140 ;
        RECT 131.995 76.910 133.865 77.080 ;
        RECT 131.610 75.850 131.780 76.850 ;
        RECT 134.080 75.850 134.250 76.850 ;
        RECT 131.995 75.620 133.865 75.790 ;
        RECT 131.610 74.560 131.780 75.560 ;
        RECT 134.080 74.560 134.250 75.560 ;
        RECT 131.995 74.330 133.865 74.500 ;
        RECT 131.610 73.270 131.780 74.270 ;
        RECT 134.080 73.270 134.250 74.270 ;
        RECT 131.995 73.040 133.865 73.210 ;
        RECT 131.610 71.980 131.780 72.980 ;
        RECT 134.080 71.980 134.250 72.980 ;
        RECT 131.995 71.750 133.865 71.920 ;
        RECT 134.590 71.350 134.760 80.060 ;
        RECT 137.170 79.870 151.380 80.040 ;
        RECT 137.170 71.880 137.340 79.870 ;
        RECT 137.970 79.360 138.970 79.530 ;
        RECT 139.260 79.360 140.260 79.530 ;
        RECT 140.550 79.360 141.550 79.530 ;
        RECT 141.840 79.360 142.840 79.530 ;
        RECT 143.130 79.360 144.130 79.530 ;
        RECT 144.420 79.360 145.420 79.530 ;
        RECT 145.710 79.360 146.710 79.530 ;
        RECT 147.000 79.360 148.000 79.530 ;
        RECT 148.290 79.360 149.290 79.530 ;
        RECT 149.580 79.360 150.580 79.530 ;
        RECT 137.740 72.605 137.910 79.145 ;
        RECT 139.030 72.605 139.200 79.145 ;
        RECT 140.320 72.605 140.490 79.145 ;
        RECT 141.610 72.605 141.780 79.145 ;
        RECT 142.900 72.605 143.070 79.145 ;
        RECT 144.190 72.605 144.360 79.145 ;
        RECT 145.480 72.605 145.650 79.145 ;
        RECT 146.770 72.605 146.940 79.145 ;
        RECT 148.060 72.605 148.230 79.145 ;
        RECT 149.350 72.605 149.520 79.145 ;
        RECT 150.640 72.605 150.810 79.145 ;
        RECT 137.970 72.220 138.970 72.390 ;
        RECT 139.260 72.220 140.260 72.390 ;
        RECT 140.550 72.220 141.550 72.390 ;
        RECT 141.840 72.220 142.840 72.390 ;
        RECT 143.130 72.220 144.130 72.390 ;
        RECT 144.420 72.220 145.420 72.390 ;
        RECT 145.710 72.220 146.710 72.390 ;
        RECT 147.000 72.220 148.000 72.390 ;
        RECT 148.290 72.220 149.290 72.390 ;
        RECT 149.580 72.220 150.580 72.390 ;
        RECT 151.210 71.880 151.380 79.870 ;
        RECT 176.620 79.950 180.450 80.120 ;
        RECT 176.620 78.540 176.790 79.950 ;
        RECT 177.130 79.080 177.300 79.410 ;
        RECT 177.515 79.380 179.555 79.550 ;
        RECT 177.515 78.940 179.555 79.110 ;
        RECT 179.770 79.080 179.940 79.410 ;
        RECT 180.280 78.540 180.450 79.950 ;
        RECT 189.015 79.165 190.225 80.255 ;
        RECT 190.395 79.820 195.740 80.255 ;
        RECT 195.915 79.820 201.260 80.255 ;
        RECT 176.620 78.370 180.450 78.540 ;
        RECT 189.015 78.455 189.535 78.995 ;
        RECT 189.705 78.625 190.225 79.165 ;
        RECT 189.015 77.705 190.225 78.455 ;
        RECT 191.980 78.250 192.320 79.080 ;
        RECT 193.800 78.570 194.150 79.820 ;
        RECT 197.500 78.250 197.840 79.080 ;
        RECT 199.320 78.570 199.670 79.820 ;
        RECT 201.895 79.090 202.185 80.255 ;
        RECT 202.355 79.820 207.700 80.255 ;
        RECT 207.875 79.820 213.220 80.255 ;
        RECT 213.395 79.820 218.740 80.255 ;
        RECT 218.915 79.820 224.260 80.255 ;
        RECT 190.395 77.705 195.740 78.250 ;
        RECT 195.915 77.705 201.260 78.250 ;
        RECT 201.895 77.705 202.185 78.430 ;
        RECT 203.940 78.250 204.280 79.080 ;
        RECT 205.760 78.570 206.110 79.820 ;
        RECT 209.460 78.250 209.800 79.080 ;
        RECT 211.280 78.570 211.630 79.820 ;
        RECT 214.980 78.250 215.320 79.080 ;
        RECT 216.800 78.570 217.150 79.820 ;
        RECT 220.500 78.250 220.840 79.080 ;
        RECT 222.320 78.570 222.670 79.820 ;
        RECT 224.435 79.165 227.025 80.255 ;
        RECT 224.435 78.475 225.645 78.995 ;
        RECT 225.815 78.645 227.025 79.165 ;
        RECT 227.655 79.090 227.945 80.255 ;
        RECT 228.665 79.585 228.835 80.085 ;
        RECT 229.005 79.755 229.335 80.255 ;
        RECT 228.665 79.415 229.330 79.585 ;
        RECT 228.580 78.595 228.930 79.245 ;
        RECT 202.355 77.705 207.700 78.250 ;
        RECT 207.875 77.705 213.220 78.250 ;
        RECT 213.395 77.705 218.740 78.250 ;
        RECT 218.915 77.705 224.260 78.250 ;
        RECT 224.435 77.705 227.025 78.475 ;
        RECT 227.655 77.705 227.945 78.430 ;
        RECT 229.100 78.425 229.330 79.415 ;
        RECT 228.665 78.255 229.330 78.425 ;
        RECT 228.665 77.965 228.835 78.255 ;
        RECT 229.005 77.705 229.335 78.085 ;
        RECT 229.505 77.965 229.730 80.085 ;
        RECT 229.945 79.755 230.275 80.255 ;
        RECT 230.445 79.585 230.615 80.085 ;
        RECT 230.850 79.870 231.680 80.040 ;
        RECT 231.920 79.875 232.300 80.255 ;
        RECT 229.920 79.415 230.615 79.585 ;
        RECT 229.920 78.445 230.090 79.415 ;
        RECT 230.260 78.625 230.670 79.245 ;
        RECT 230.840 79.195 231.340 79.575 ;
        RECT 229.920 78.255 230.615 78.445 ;
        RECT 230.840 78.325 231.060 79.195 ;
        RECT 231.510 79.025 231.680 79.870 ;
        RECT 232.480 79.705 232.650 79.995 ;
        RECT 232.820 79.875 233.150 80.255 ;
        RECT 233.620 79.785 234.250 80.035 ;
        RECT 234.430 79.875 234.850 80.255 ;
        RECT 234.080 79.705 234.250 79.785 ;
        RECT 235.050 79.705 235.290 79.995 ;
        RECT 231.850 79.455 233.220 79.705 ;
        RECT 231.850 79.195 232.100 79.455 ;
        RECT 232.610 79.025 232.860 79.185 ;
        RECT 231.510 78.855 232.860 79.025 ;
        RECT 231.510 78.815 231.930 78.855 ;
        RECT 231.240 78.265 231.590 78.635 ;
        RECT 229.945 77.705 230.275 78.085 ;
        RECT 230.445 77.925 230.615 78.255 ;
        RECT 231.760 78.085 231.930 78.815 ;
        RECT 233.030 78.685 233.220 79.455 ;
        RECT 232.100 78.355 232.510 78.685 ;
        RECT 232.800 78.345 233.220 78.685 ;
        RECT 233.390 79.275 233.910 79.585 ;
        RECT 234.080 79.535 235.290 79.705 ;
        RECT 235.520 79.565 235.850 80.255 ;
        RECT 233.390 78.515 233.560 79.275 ;
        RECT 233.730 78.685 233.910 79.095 ;
        RECT 234.080 79.025 234.250 79.535 ;
        RECT 236.020 79.385 236.190 79.995 ;
        RECT 236.460 79.535 236.790 80.045 ;
        RECT 236.020 79.365 236.340 79.385 ;
        RECT 234.420 79.195 236.340 79.365 ;
        RECT 234.080 78.855 235.980 79.025 ;
        RECT 234.310 78.515 234.640 78.635 ;
        RECT 233.390 78.345 234.640 78.515 ;
        RECT 230.915 77.885 231.930 78.085 ;
        RECT 232.100 77.705 232.510 78.145 ;
        RECT 232.800 77.915 233.050 78.345 ;
        RECT 233.250 77.705 233.570 78.165 ;
        RECT 234.810 78.095 234.980 78.855 ;
        RECT 235.650 78.795 235.980 78.855 ;
        RECT 235.170 78.625 235.500 78.685 ;
        RECT 235.170 78.355 235.830 78.625 ;
        RECT 236.150 78.300 236.340 79.195 ;
        RECT 234.130 77.925 234.980 78.095 ;
        RECT 235.180 77.705 235.840 78.185 ;
        RECT 236.020 77.970 236.340 78.300 ;
        RECT 236.540 78.945 236.790 79.535 ;
        RECT 236.970 79.455 237.255 80.255 ;
        RECT 237.435 79.275 237.690 79.945 ;
        RECT 236.540 78.615 237.340 78.945 ;
        RECT 236.540 77.965 236.790 78.615 ;
        RECT 237.510 78.415 237.690 79.275 ;
        RECT 238.235 79.165 239.445 80.255 ;
        RECT 237.435 78.215 237.690 78.415 ;
        RECT 238.235 78.455 238.755 78.995 ;
        RECT 238.925 78.625 239.445 79.165 ;
        RECT 239.615 79.115 240.000 80.085 ;
        RECT 240.170 79.795 240.495 80.255 ;
        RECT 241.015 79.625 241.295 80.085 ;
        RECT 240.170 79.405 241.295 79.625 ;
        RECT 236.970 77.705 237.255 78.165 ;
        RECT 237.435 78.045 237.775 78.215 ;
        RECT 237.435 77.885 237.690 78.045 ;
        RECT 238.235 77.705 239.445 78.455 ;
        RECT 239.615 78.445 239.895 79.115 ;
        RECT 240.170 78.945 240.620 79.405 ;
        RECT 241.485 79.235 241.885 80.085 ;
        RECT 242.285 79.795 242.555 80.255 ;
        RECT 242.725 79.625 243.010 80.085 ;
        RECT 240.065 78.615 240.620 78.945 ;
        RECT 240.790 78.675 241.885 79.235 ;
        RECT 240.170 78.505 240.620 78.615 ;
        RECT 239.615 77.875 240.000 78.445 ;
        RECT 240.170 78.335 241.295 78.505 ;
        RECT 240.170 77.705 240.495 78.165 ;
        RECT 241.015 77.875 241.295 78.335 ;
        RECT 241.485 77.875 241.885 78.675 ;
        RECT 242.055 79.405 243.010 79.625 ;
        RECT 242.055 78.505 242.265 79.405 ;
        RECT 243.295 79.285 243.605 80.085 ;
        RECT 243.775 79.455 244.085 80.255 ;
        RECT 244.255 79.625 244.515 80.085 ;
        RECT 244.685 79.795 244.940 80.255 ;
        RECT 245.115 79.625 245.375 80.085 ;
        RECT 244.255 79.455 245.375 79.625 ;
        RECT 242.435 78.675 243.125 79.235 ;
        RECT 243.295 79.115 244.325 79.285 ;
        RECT 242.055 78.335 243.010 78.505 ;
        RECT 242.285 77.705 242.555 78.165 ;
        RECT 242.725 77.875 243.010 78.335 ;
        RECT 243.295 78.205 243.465 79.115 ;
        RECT 243.635 78.375 243.985 78.945 ;
        RECT 244.155 78.865 244.325 79.115 ;
        RECT 245.115 79.205 245.375 79.455 ;
        RECT 245.545 79.385 245.830 80.255 ;
        RECT 245.115 79.035 245.870 79.205 ;
        RECT 244.155 78.695 245.295 78.865 ;
        RECT 245.465 78.525 245.870 79.035 ;
        RECT 246.515 79.165 247.725 80.255 ;
        RECT 246.515 78.625 247.035 79.165 ;
        RECT 244.220 78.355 245.870 78.525 ;
        RECT 247.205 78.455 247.725 78.995 ;
        RECT 243.295 77.875 243.595 78.205 ;
        RECT 243.765 77.705 244.040 78.185 ;
        RECT 244.220 77.965 244.515 78.355 ;
        RECT 244.685 77.705 244.940 78.185 ;
        RECT 245.115 77.965 245.375 78.355 ;
        RECT 245.545 77.705 245.825 78.185 ;
        RECT 246.515 77.705 247.725 78.455 ;
        RECT 188.930 77.535 247.810 77.705 ;
        RECT 189.015 76.785 190.225 77.535 ;
        RECT 190.395 76.990 195.740 77.535 ;
        RECT 195.915 76.990 201.260 77.535 ;
        RECT 201.435 76.990 206.780 77.535 ;
        RECT 206.955 76.990 212.300 77.535 ;
        RECT 177.090 76.280 179.830 76.450 ;
        RECT 177.090 74.870 177.260 76.280 ;
        RECT 177.600 75.410 177.770 75.740 ;
        RECT 177.940 75.710 178.980 75.880 ;
        RECT 177.940 75.270 178.980 75.440 ;
        RECT 179.150 75.410 179.320 75.740 ;
        RECT 179.660 74.870 179.830 76.280 ;
        RECT 189.015 76.245 189.535 76.785 ;
        RECT 189.705 76.075 190.225 76.615 ;
        RECT 191.980 76.160 192.320 76.990 ;
        RECT 189.015 74.985 190.225 76.075 ;
        RECT 193.800 75.420 194.150 76.670 ;
        RECT 197.500 76.160 197.840 76.990 ;
        RECT 199.320 75.420 199.670 76.670 ;
        RECT 203.020 76.160 203.360 76.990 ;
        RECT 204.840 75.420 205.190 76.670 ;
        RECT 208.540 76.160 208.880 76.990 ;
        RECT 212.475 76.765 214.145 77.535 ;
        RECT 214.775 76.810 215.065 77.535 ;
        RECT 215.235 76.990 220.580 77.535 ;
        RECT 220.755 76.990 226.100 77.535 ;
        RECT 210.360 75.420 210.710 76.670 ;
        RECT 212.475 76.245 213.225 76.765 ;
        RECT 213.395 76.075 214.145 76.595 ;
        RECT 216.820 76.160 217.160 76.990 ;
        RECT 190.395 74.985 195.740 75.420 ;
        RECT 195.915 74.985 201.260 75.420 ;
        RECT 201.435 74.985 206.780 75.420 ;
        RECT 206.955 74.985 212.300 75.420 ;
        RECT 212.475 74.985 214.145 76.075 ;
        RECT 214.775 74.985 215.065 76.150 ;
        RECT 218.640 75.420 218.990 76.670 ;
        RECT 222.340 76.160 222.680 76.990 ;
        RECT 226.275 76.765 229.785 77.535 ;
        RECT 230.875 77.025 231.180 77.535 ;
        RECT 224.160 75.420 224.510 76.670 ;
        RECT 226.275 76.245 227.925 76.765 ;
        RECT 228.095 76.075 229.785 76.595 ;
        RECT 230.875 76.295 231.190 76.855 ;
        RECT 231.360 76.545 231.610 77.355 ;
        RECT 231.780 77.010 232.040 77.535 ;
        RECT 232.220 76.545 232.470 77.355 ;
        RECT 232.640 76.975 232.900 77.535 ;
        RECT 233.070 76.885 233.330 77.340 ;
        RECT 233.500 77.055 233.760 77.535 ;
        RECT 233.930 76.885 234.190 77.340 ;
        RECT 234.360 77.055 234.620 77.535 ;
        RECT 234.790 76.885 235.050 77.340 ;
        RECT 235.220 77.055 235.465 77.535 ;
        RECT 235.635 76.885 235.910 77.340 ;
        RECT 236.080 77.055 236.325 77.535 ;
        RECT 236.495 76.885 236.755 77.340 ;
        RECT 236.935 77.055 237.185 77.535 ;
        RECT 237.355 76.885 237.615 77.340 ;
        RECT 237.795 77.055 238.045 77.535 ;
        RECT 238.215 76.885 238.475 77.340 ;
        RECT 238.655 77.055 238.915 77.535 ;
        RECT 239.085 76.885 239.345 77.340 ;
        RECT 239.515 77.055 239.815 77.535 ;
        RECT 233.070 76.855 239.815 76.885 ;
        RECT 233.070 76.715 239.845 76.855 ;
        RECT 240.535 76.810 240.825 77.535 ;
        RECT 238.650 76.685 239.845 76.715 ;
        RECT 240.995 76.795 241.380 77.365 ;
        RECT 241.550 77.075 241.875 77.535 ;
        RECT 242.395 76.905 242.675 77.365 ;
        RECT 231.360 76.295 238.480 76.545 ;
        RECT 215.235 74.985 220.580 75.420 ;
        RECT 220.755 74.985 226.100 75.420 ;
        RECT 226.275 74.985 229.785 76.075 ;
        RECT 230.885 74.985 231.180 75.795 ;
        RECT 231.360 75.155 231.605 76.295 ;
        RECT 231.780 74.985 232.040 75.795 ;
        RECT 232.220 75.160 232.470 76.295 ;
        RECT 238.650 76.125 239.815 76.685 ;
        RECT 233.070 75.900 239.815 76.125 ;
        RECT 233.070 75.885 238.475 75.900 ;
        RECT 232.640 74.990 232.900 75.785 ;
        RECT 233.070 75.160 233.330 75.885 ;
        RECT 233.500 74.990 233.760 75.715 ;
        RECT 233.930 75.160 234.190 75.885 ;
        RECT 234.360 74.990 234.620 75.715 ;
        RECT 234.790 75.160 235.050 75.885 ;
        RECT 235.220 74.990 235.480 75.715 ;
        RECT 235.650 75.160 235.910 75.885 ;
        RECT 236.080 74.990 236.325 75.715 ;
        RECT 236.495 75.160 236.755 75.885 ;
        RECT 236.940 74.990 237.185 75.715 ;
        RECT 237.355 75.160 237.615 75.885 ;
        RECT 237.800 74.990 238.045 75.715 ;
        RECT 238.215 75.160 238.475 75.885 ;
        RECT 238.660 74.990 238.915 75.715 ;
        RECT 239.085 75.160 239.375 75.900 ;
        RECT 232.640 74.985 238.915 74.990 ;
        RECT 239.545 74.985 239.815 75.730 ;
        RECT 240.535 74.985 240.825 76.150 ;
        RECT 240.995 76.125 241.275 76.795 ;
        RECT 241.550 76.735 242.675 76.905 ;
        RECT 241.550 76.625 242.000 76.735 ;
        RECT 241.445 76.295 242.000 76.625 ;
        RECT 242.865 76.565 243.265 77.365 ;
        RECT 243.665 77.075 243.935 77.535 ;
        RECT 244.105 76.905 244.390 77.365 ;
        RECT 240.995 75.155 241.380 76.125 ;
        RECT 241.550 75.835 242.000 76.295 ;
        RECT 242.170 76.005 243.265 76.565 ;
        RECT 241.550 75.615 242.675 75.835 ;
        RECT 241.550 74.985 241.875 75.445 ;
        RECT 242.395 75.155 242.675 75.615 ;
        RECT 242.865 75.155 243.265 76.005 ;
        RECT 243.435 76.735 244.390 76.905 ;
        RECT 244.765 76.985 244.935 77.365 ;
        RECT 245.150 77.155 245.480 77.535 ;
        RECT 244.765 76.815 245.480 76.985 ;
        RECT 243.435 75.835 243.645 76.735 ;
        RECT 243.815 76.005 244.505 76.565 ;
        RECT 244.675 76.265 245.030 76.635 ;
        RECT 245.310 76.625 245.480 76.815 ;
        RECT 245.650 76.790 245.905 77.365 ;
        RECT 245.310 76.295 245.565 76.625 ;
        RECT 245.310 76.085 245.480 76.295 ;
        RECT 244.765 75.915 245.480 76.085 ;
        RECT 245.735 76.060 245.905 76.790 ;
        RECT 246.080 76.695 246.340 77.535 ;
        RECT 246.515 76.785 247.725 77.535 ;
        RECT 243.435 75.615 244.390 75.835 ;
        RECT 243.665 74.985 243.935 75.445 ;
        RECT 244.105 75.155 244.390 75.615 ;
        RECT 244.765 75.155 244.935 75.915 ;
        RECT 245.150 74.985 245.480 75.745 ;
        RECT 245.650 75.155 245.905 76.060 ;
        RECT 246.080 74.985 246.340 76.135 ;
        RECT 246.515 76.075 247.035 76.615 ;
        RECT 247.205 76.245 247.725 76.785 ;
        RECT 246.515 74.985 247.725 76.075 ;
        RECT 177.090 74.700 179.830 74.870 ;
        RECT 188.930 74.815 247.810 74.985 ;
        RECT 189.015 73.725 190.225 74.815 ;
        RECT 190.395 74.380 195.740 74.815 ;
        RECT 195.915 74.380 201.260 74.815 ;
        RECT 189.015 73.015 189.535 73.555 ;
        RECT 189.705 73.185 190.225 73.725 ;
        RECT 189.015 72.265 190.225 73.015 ;
        RECT 191.980 72.810 192.320 73.640 ;
        RECT 193.800 73.130 194.150 74.380 ;
        RECT 197.500 72.810 197.840 73.640 ;
        RECT 199.320 73.130 199.670 74.380 ;
        RECT 201.895 73.650 202.185 74.815 ;
        RECT 202.355 74.380 207.700 74.815 ;
        RECT 207.875 74.380 213.220 74.815 ;
        RECT 213.395 74.380 218.740 74.815 ;
        RECT 218.915 74.380 224.260 74.815 ;
        RECT 190.395 72.265 195.740 72.810 ;
        RECT 195.915 72.265 201.260 72.810 ;
        RECT 201.895 72.265 202.185 72.990 ;
        RECT 203.940 72.810 204.280 73.640 ;
        RECT 205.760 73.130 206.110 74.380 ;
        RECT 209.460 72.810 209.800 73.640 ;
        RECT 211.280 73.130 211.630 74.380 ;
        RECT 214.980 72.810 215.320 73.640 ;
        RECT 216.800 73.130 217.150 74.380 ;
        RECT 220.500 72.810 220.840 73.640 ;
        RECT 222.320 73.130 222.670 74.380 ;
        RECT 224.435 73.725 227.025 74.815 ;
        RECT 224.435 73.035 225.645 73.555 ;
        RECT 225.815 73.205 227.025 73.725 ;
        RECT 227.655 73.650 227.945 74.815 ;
        RECT 228.115 73.725 230.705 74.815 ;
        RECT 231.340 74.145 231.595 74.645 ;
        RECT 231.765 74.315 232.095 74.815 ;
        RECT 231.340 73.975 232.090 74.145 ;
        RECT 228.115 73.035 229.325 73.555 ;
        RECT 229.495 73.205 230.705 73.725 ;
        RECT 231.340 73.155 231.690 73.805 ;
        RECT 202.355 72.265 207.700 72.810 ;
        RECT 207.875 72.265 213.220 72.810 ;
        RECT 213.395 72.265 218.740 72.810 ;
        RECT 218.915 72.265 224.260 72.810 ;
        RECT 224.435 72.265 227.025 73.035 ;
        RECT 227.655 72.265 227.945 72.990 ;
        RECT 228.115 72.265 230.705 73.035 ;
        RECT 231.860 72.985 232.090 73.975 ;
        RECT 231.340 72.815 232.090 72.985 ;
        RECT 231.340 72.525 231.595 72.815 ;
        RECT 231.765 72.265 232.095 72.645 ;
        RECT 232.265 72.525 232.435 74.645 ;
        RECT 232.605 73.845 232.930 74.630 ;
        RECT 233.100 74.355 233.350 74.815 ;
        RECT 233.520 74.315 233.770 74.645 ;
        RECT 233.985 74.315 234.665 74.645 ;
        RECT 233.520 74.185 233.690 74.315 ;
        RECT 233.295 74.015 233.690 74.185 ;
        RECT 232.665 72.795 233.125 73.845 ;
        RECT 233.295 72.655 233.465 74.015 ;
        RECT 233.860 73.755 234.325 74.145 ;
        RECT 233.635 72.945 233.985 73.565 ;
        RECT 234.155 73.165 234.325 73.755 ;
        RECT 234.495 73.535 234.665 74.315 ;
        RECT 234.835 74.215 235.005 74.555 ;
        RECT 235.240 74.385 235.570 74.815 ;
        RECT 235.740 74.215 235.910 74.555 ;
        RECT 236.205 74.355 236.575 74.815 ;
        RECT 234.835 74.045 235.910 74.215 ;
        RECT 236.745 74.185 236.915 74.645 ;
        RECT 237.150 74.305 238.020 74.645 ;
        RECT 238.190 74.355 238.440 74.815 ;
        RECT 236.355 74.015 236.915 74.185 ;
        RECT 236.355 73.875 236.525 74.015 ;
        RECT 235.025 73.705 236.525 73.875 ;
        RECT 237.220 73.845 237.680 74.135 ;
        RECT 234.495 73.365 236.185 73.535 ;
        RECT 234.155 72.945 234.510 73.165 ;
        RECT 234.680 72.655 234.850 73.365 ;
        RECT 235.055 72.945 235.845 73.195 ;
        RECT 236.015 73.185 236.185 73.365 ;
        RECT 236.355 73.015 236.525 73.705 ;
        RECT 232.795 72.265 233.125 72.625 ;
        RECT 233.295 72.485 233.790 72.655 ;
        RECT 233.995 72.485 234.850 72.655 ;
        RECT 235.725 72.265 236.055 72.725 ;
        RECT 236.265 72.625 236.525 73.015 ;
        RECT 236.715 73.835 237.680 73.845 ;
        RECT 237.850 73.925 238.020 74.305 ;
        RECT 238.610 74.265 238.780 74.555 ;
        RECT 238.960 74.435 239.290 74.815 ;
        RECT 238.610 74.095 239.410 74.265 ;
        RECT 236.715 73.675 237.390 73.835 ;
        RECT 237.850 73.755 239.070 73.925 ;
        RECT 236.715 72.885 236.925 73.675 ;
        RECT 237.850 73.665 238.020 73.755 ;
        RECT 237.095 72.885 237.445 73.505 ;
        RECT 237.615 73.495 238.020 73.665 ;
        RECT 237.615 72.715 237.785 73.495 ;
        RECT 237.955 73.045 238.175 73.325 ;
        RECT 238.355 73.215 238.895 73.585 ;
        RECT 239.240 73.505 239.410 74.095 ;
        RECT 239.630 73.675 239.935 74.815 ;
        RECT 240.105 73.625 240.360 74.505 ;
        RECT 239.240 73.475 239.980 73.505 ;
        RECT 237.955 72.875 238.485 73.045 ;
        RECT 236.265 72.455 236.615 72.625 ;
        RECT 236.835 72.435 237.785 72.715 ;
        RECT 237.955 72.265 238.145 72.705 ;
        RECT 238.315 72.645 238.485 72.875 ;
        RECT 238.655 72.815 238.895 73.215 ;
        RECT 239.065 73.175 239.980 73.475 ;
        RECT 239.065 73.000 239.390 73.175 ;
        RECT 239.065 72.645 239.385 73.000 ;
        RECT 240.150 72.975 240.360 73.625 ;
        RECT 238.315 72.475 239.385 72.645 ;
        RECT 239.630 72.265 239.935 72.725 ;
        RECT 240.105 72.445 240.360 72.975 ;
        RECT 240.535 73.675 240.920 74.645 ;
        RECT 241.090 74.355 241.415 74.815 ;
        RECT 241.935 74.185 242.215 74.645 ;
        RECT 241.090 73.965 242.215 74.185 ;
        RECT 240.535 73.005 240.815 73.675 ;
        RECT 241.090 73.505 241.540 73.965 ;
        RECT 242.405 73.795 242.805 74.645 ;
        RECT 243.205 74.355 243.475 74.815 ;
        RECT 243.645 74.185 243.930 74.645 ;
        RECT 240.985 73.175 241.540 73.505 ;
        RECT 241.710 73.235 242.805 73.795 ;
        RECT 241.090 73.065 241.540 73.175 ;
        RECT 240.535 72.435 240.920 73.005 ;
        RECT 241.090 72.895 242.215 73.065 ;
        RECT 241.090 72.265 241.415 72.725 ;
        RECT 241.935 72.435 242.215 72.895 ;
        RECT 242.405 72.435 242.805 73.235 ;
        RECT 242.975 73.965 243.930 74.185 ;
        RECT 242.975 73.065 243.185 73.965 ;
        RECT 243.355 73.235 244.045 73.795 ;
        RECT 244.215 73.725 245.885 74.815 ;
        RECT 242.975 72.895 243.930 73.065 ;
        RECT 243.205 72.265 243.475 72.725 ;
        RECT 243.645 72.435 243.930 72.895 ;
        RECT 244.215 73.035 244.965 73.555 ;
        RECT 245.135 73.205 245.885 73.725 ;
        RECT 246.515 73.725 247.725 74.815 ;
        RECT 246.515 73.185 247.035 73.725 ;
        RECT 244.215 72.265 245.885 73.035 ;
        RECT 247.205 73.015 247.725 73.555 ;
        RECT 246.515 72.265 247.725 73.015 ;
        RECT 188.930 72.095 247.810 72.265 ;
        RECT 137.170 71.710 151.380 71.880 ;
        RECT 131.100 71.180 134.760 71.350 ;
        RECT 189.015 71.345 190.225 72.095 ;
        RECT 190.395 71.550 195.740 72.095 ;
        RECT 195.915 71.550 201.260 72.095 ;
        RECT 201.435 71.550 206.780 72.095 ;
        RECT 206.955 71.550 212.300 72.095 ;
        RECT 125.230 70.980 128.890 71.150 ;
        RECT 189.015 70.805 189.535 71.345 ;
        RECT 189.705 70.635 190.225 71.175 ;
        RECT 191.980 70.720 192.320 71.550 ;
        RECT 81.820 70.020 88.450 70.190 ;
        RECT 142.380 69.850 149.010 70.020 ;
        RECT 71.150 68.490 73.250 68.660 ;
        RECT 125.900 69.410 128.000 69.580 ;
        RECT 77.880 67.940 82.870 68.110 ;
        RECT 70.210 66.720 75.820 66.890 ;
        RECT 65.140 66.450 67.740 66.620 ;
        RECT 65.140 64.400 65.310 66.450 ;
        RECT 65.940 65.940 66.940 66.110 ;
        RECT 65.710 65.080 65.880 65.770 ;
        RECT 67.000 65.080 67.170 65.770 ;
        RECT 65.940 64.740 66.940 64.910 ;
        RECT 67.570 64.400 67.740 66.450 ;
        RECT 65.140 64.230 67.740 64.400 ;
        RECT 70.210 64.460 70.380 66.720 ;
        RECT 71.060 66.150 74.970 66.320 ;
        RECT 70.720 65.090 70.890 66.090 ;
        RECT 75.140 65.090 75.310 66.090 ;
        RECT 71.060 64.860 74.970 65.030 ;
        RECT 75.650 64.460 75.820 66.720 ;
        RECT 70.210 64.290 75.820 64.460 ;
        RECT 77.880 64.390 78.050 67.940 ;
        RECT 78.730 67.370 82.020 67.540 ;
        RECT 78.390 66.310 78.560 67.310 ;
        RECT 82.190 66.310 82.360 67.310 ;
        RECT 78.730 66.080 82.020 66.250 ;
        RECT 78.390 65.020 78.560 66.020 ;
        RECT 82.190 65.020 82.360 66.020 ;
        RECT 78.730 64.790 82.020 64.960 ;
        RECT 82.700 64.390 82.870 67.940 ;
        RECT 125.900 67.010 126.070 69.410 ;
        RECT 126.700 68.900 127.200 69.070 ;
        RECT 126.470 67.690 126.640 68.730 ;
        RECT 127.260 67.690 127.430 68.730 ;
        RECT 126.700 67.350 127.200 67.520 ;
        RECT 127.830 67.010 128.000 69.410 ;
        RECT 125.900 66.840 128.000 67.010 ;
        RECT 131.710 69.410 133.810 69.580 ;
        RECT 131.710 67.010 131.880 69.410 ;
        RECT 132.510 68.900 133.010 69.070 ;
        RECT 132.280 67.690 132.450 68.730 ;
        RECT 133.070 67.690 133.240 68.730 ;
        RECT 132.510 67.350 133.010 67.520 ;
        RECT 133.640 67.010 133.810 69.410 ;
        RECT 142.380 68.540 142.550 69.850 ;
        RECT 143.030 69.020 145.190 69.370 ;
        RECT 146.200 69.020 148.360 69.370 ;
        RECT 148.840 68.540 149.010 69.850 ;
        RECT 189.015 69.545 190.225 70.635 ;
        RECT 193.800 69.980 194.150 71.230 ;
        RECT 197.500 70.720 197.840 71.550 ;
        RECT 199.320 69.980 199.670 71.230 ;
        RECT 203.020 70.720 203.360 71.550 ;
        RECT 204.840 69.980 205.190 71.230 ;
        RECT 208.540 70.720 208.880 71.550 ;
        RECT 212.475 71.325 214.145 72.095 ;
        RECT 214.775 71.370 215.065 72.095 ;
        RECT 215.235 71.550 220.580 72.095 ;
        RECT 220.755 71.550 226.100 72.095 ;
        RECT 210.360 69.980 210.710 71.230 ;
        RECT 212.475 70.805 213.225 71.325 ;
        RECT 213.395 70.635 214.145 71.155 ;
        RECT 216.820 70.720 217.160 71.550 ;
        RECT 190.395 69.545 195.740 69.980 ;
        RECT 195.915 69.545 201.260 69.980 ;
        RECT 201.435 69.545 206.780 69.980 ;
        RECT 206.955 69.545 212.300 69.980 ;
        RECT 212.475 69.545 214.145 70.635 ;
        RECT 214.775 69.545 215.065 70.710 ;
        RECT 218.640 69.980 218.990 71.230 ;
        RECT 222.340 70.720 222.680 71.550 ;
        RECT 226.275 71.325 229.785 72.095 ;
        RECT 229.955 71.345 231.165 72.095 ;
        RECT 231.340 71.545 231.595 71.835 ;
        RECT 231.765 71.715 232.095 72.095 ;
        RECT 231.340 71.375 232.090 71.545 ;
        RECT 224.160 69.980 224.510 71.230 ;
        RECT 226.275 70.805 227.925 71.325 ;
        RECT 228.095 70.635 229.785 71.155 ;
        RECT 229.955 70.805 230.475 71.345 ;
        RECT 230.645 70.635 231.165 71.175 ;
        RECT 215.235 69.545 220.580 69.980 ;
        RECT 220.755 69.545 226.100 69.980 ;
        RECT 226.275 69.545 229.785 70.635 ;
        RECT 229.955 69.545 231.165 70.635 ;
        RECT 231.340 70.555 231.690 71.205 ;
        RECT 231.860 70.385 232.090 71.375 ;
        RECT 231.340 70.215 232.090 70.385 ;
        RECT 231.340 69.715 231.595 70.215 ;
        RECT 231.765 69.545 232.095 70.045 ;
        RECT 232.265 69.715 232.435 71.835 ;
        RECT 232.795 71.735 233.125 72.095 ;
        RECT 233.295 71.705 233.790 71.875 ;
        RECT 233.995 71.705 234.850 71.875 ;
        RECT 232.665 70.515 233.125 71.565 ;
        RECT 232.605 69.730 232.930 70.515 ;
        RECT 233.295 70.345 233.465 71.705 ;
        RECT 233.635 70.795 233.985 71.415 ;
        RECT 234.155 71.195 234.510 71.415 ;
        RECT 234.155 70.605 234.325 71.195 ;
        RECT 234.680 70.995 234.850 71.705 ;
        RECT 235.725 71.635 236.055 72.095 ;
        RECT 236.265 71.735 236.615 71.905 ;
        RECT 235.055 71.165 235.845 71.415 ;
        RECT 236.265 71.345 236.525 71.735 ;
        RECT 236.835 71.645 237.785 71.925 ;
        RECT 237.955 71.655 238.145 72.095 ;
        RECT 238.315 71.715 239.385 71.885 ;
        RECT 236.015 70.995 236.185 71.175 ;
        RECT 233.295 70.175 233.690 70.345 ;
        RECT 233.860 70.215 234.325 70.605 ;
        RECT 234.495 70.825 236.185 70.995 ;
        RECT 233.520 70.045 233.690 70.175 ;
        RECT 234.495 70.045 234.665 70.825 ;
        RECT 236.355 70.655 236.525 71.345 ;
        RECT 235.025 70.485 236.525 70.655 ;
        RECT 236.715 70.685 236.925 71.475 ;
        RECT 237.095 70.855 237.445 71.475 ;
        RECT 237.615 70.865 237.785 71.645 ;
        RECT 238.315 71.485 238.485 71.715 ;
        RECT 237.955 71.315 238.485 71.485 ;
        RECT 237.955 71.035 238.175 71.315 ;
        RECT 238.655 71.145 238.895 71.545 ;
        RECT 237.615 70.695 238.020 70.865 ;
        RECT 238.355 70.775 238.895 71.145 ;
        RECT 239.065 71.360 239.385 71.715 ;
        RECT 239.630 71.635 239.935 72.095 ;
        RECT 240.105 71.385 240.360 71.915 ;
        RECT 239.065 71.185 239.390 71.360 ;
        RECT 239.065 70.885 239.980 71.185 ;
        RECT 239.240 70.855 239.980 70.885 ;
        RECT 236.715 70.525 237.390 70.685 ;
        RECT 237.850 70.605 238.020 70.695 ;
        RECT 236.715 70.515 237.680 70.525 ;
        RECT 236.355 70.345 236.525 70.485 ;
        RECT 233.100 69.545 233.350 70.005 ;
        RECT 233.520 69.715 233.770 70.045 ;
        RECT 233.985 69.715 234.665 70.045 ;
        RECT 234.835 70.145 235.910 70.315 ;
        RECT 236.355 70.175 236.915 70.345 ;
        RECT 237.220 70.225 237.680 70.515 ;
        RECT 237.850 70.435 239.070 70.605 ;
        RECT 234.835 69.805 235.005 70.145 ;
        RECT 235.240 69.545 235.570 69.975 ;
        RECT 235.740 69.805 235.910 70.145 ;
        RECT 236.205 69.545 236.575 70.005 ;
        RECT 236.745 69.715 236.915 70.175 ;
        RECT 237.850 70.055 238.020 70.435 ;
        RECT 239.240 70.265 239.410 70.855 ;
        RECT 240.150 70.735 240.360 71.385 ;
        RECT 240.535 71.370 240.825 72.095 ;
        RECT 240.995 71.325 244.505 72.095 ;
        RECT 244.765 71.545 244.935 71.925 ;
        RECT 245.150 71.715 245.480 72.095 ;
        RECT 244.765 71.375 245.480 71.545 ;
        RECT 240.995 70.805 242.645 71.325 ;
        RECT 237.150 69.715 238.020 70.055 ;
        RECT 238.610 70.095 239.410 70.265 ;
        RECT 238.190 69.545 238.440 70.005 ;
        RECT 238.610 69.805 238.780 70.095 ;
        RECT 238.960 69.545 239.290 69.925 ;
        RECT 239.630 69.545 239.935 70.685 ;
        RECT 240.105 69.855 240.360 70.735 ;
        RECT 240.535 69.545 240.825 70.710 ;
        RECT 242.815 70.635 244.505 71.155 ;
        RECT 244.675 70.825 245.030 71.195 ;
        RECT 245.310 71.185 245.480 71.375 ;
        RECT 245.650 71.350 245.905 71.925 ;
        RECT 245.310 70.855 245.565 71.185 ;
        RECT 245.310 70.645 245.480 70.855 ;
        RECT 240.995 69.545 244.505 70.635 ;
        RECT 244.765 70.475 245.480 70.645 ;
        RECT 245.735 70.620 245.905 71.350 ;
        RECT 246.080 71.255 246.340 72.095 ;
        RECT 246.515 71.345 247.725 72.095 ;
        RECT 244.765 69.715 244.935 70.475 ;
        RECT 245.150 69.545 245.480 70.305 ;
        RECT 245.650 69.715 245.905 70.620 ;
        RECT 246.080 69.545 246.340 70.695 ;
        RECT 246.515 70.635 247.035 71.175 ;
        RECT 247.205 70.805 247.725 71.345 ;
        RECT 246.515 69.545 247.725 70.635 ;
        RECT 188.930 69.375 247.810 69.545 ;
        RECT 142.380 68.370 149.010 68.540 ;
        RECT 189.015 68.285 190.225 69.375 ;
        RECT 190.395 68.940 195.740 69.375 ;
        RECT 195.915 68.940 201.260 69.375 ;
        RECT 131.710 66.840 133.810 67.010 ;
        RECT 189.015 67.575 189.535 68.115 ;
        RECT 189.705 67.745 190.225 68.285 ;
        RECT 189.015 66.825 190.225 67.575 ;
        RECT 191.980 67.370 192.320 68.200 ;
        RECT 193.800 67.690 194.150 68.940 ;
        RECT 197.500 67.370 197.840 68.200 ;
        RECT 199.320 67.690 199.670 68.940 ;
        RECT 201.895 68.210 202.185 69.375 ;
        RECT 202.355 68.940 207.700 69.375 ;
        RECT 207.875 68.940 213.220 69.375 ;
        RECT 190.395 66.825 195.740 67.370 ;
        RECT 195.915 66.825 201.260 67.370 ;
        RECT 201.895 66.825 202.185 67.550 ;
        RECT 203.940 67.370 204.280 68.200 ;
        RECT 205.760 67.690 206.110 68.940 ;
        RECT 209.460 67.370 209.800 68.200 ;
        RECT 211.280 67.690 211.630 68.940 ;
        RECT 213.395 68.285 214.605 69.375 ;
        RECT 213.395 67.575 213.915 68.115 ;
        RECT 214.085 67.745 214.605 68.285 ;
        RECT 214.775 68.210 215.065 69.375 ;
        RECT 215.235 68.940 220.580 69.375 ;
        RECT 220.755 68.940 226.100 69.375 ;
        RECT 202.355 66.825 207.700 67.370 ;
        RECT 207.875 66.825 213.220 67.370 ;
        RECT 213.395 66.825 214.605 67.575 ;
        RECT 214.775 66.825 215.065 67.550 ;
        RECT 216.820 67.370 217.160 68.200 ;
        RECT 218.640 67.690 218.990 68.940 ;
        RECT 222.340 67.370 222.680 68.200 ;
        RECT 224.160 67.690 224.510 68.940 ;
        RECT 226.275 68.285 227.485 69.375 ;
        RECT 226.275 67.575 226.795 68.115 ;
        RECT 226.965 67.745 227.485 68.285 ;
        RECT 227.655 68.210 227.945 69.375 ;
        RECT 228.115 68.940 233.460 69.375 ;
        RECT 233.635 68.940 238.980 69.375 ;
        RECT 215.235 66.825 220.580 67.370 ;
        RECT 220.755 66.825 226.100 67.370 ;
        RECT 226.275 66.825 227.485 67.575 ;
        RECT 227.655 66.825 227.945 67.550 ;
        RECT 229.700 67.370 230.040 68.200 ;
        RECT 231.520 67.690 231.870 68.940 ;
        RECT 235.220 67.370 235.560 68.200 ;
        RECT 237.040 67.690 237.390 68.940 ;
        RECT 239.155 68.285 240.365 69.375 ;
        RECT 239.155 67.575 239.675 68.115 ;
        RECT 239.845 67.745 240.365 68.285 ;
        RECT 240.535 68.210 240.825 69.375 ;
        RECT 240.995 68.285 244.505 69.375 ;
        RECT 240.995 67.595 242.645 68.115 ;
        RECT 242.815 67.765 244.505 68.285 ;
        RECT 244.765 68.445 244.935 69.205 ;
        RECT 245.150 68.615 245.480 69.375 ;
        RECT 244.765 68.275 245.480 68.445 ;
        RECT 245.650 68.300 245.905 69.205 ;
        RECT 244.675 67.725 245.030 68.095 ;
        RECT 245.310 68.065 245.480 68.275 ;
        RECT 245.310 67.735 245.565 68.065 ;
        RECT 228.115 66.825 233.460 67.370 ;
        RECT 233.635 66.825 238.980 67.370 ;
        RECT 239.155 66.825 240.365 67.575 ;
        RECT 240.535 66.825 240.825 67.550 ;
        RECT 240.995 66.825 244.505 67.595 ;
        RECT 245.310 67.545 245.480 67.735 ;
        RECT 245.735 67.570 245.905 68.300 ;
        RECT 246.080 68.225 246.340 69.375 ;
        RECT 246.515 68.285 247.725 69.375 ;
        RECT 246.515 67.745 247.035 68.285 ;
        RECT 244.765 67.375 245.480 67.545 ;
        RECT 244.765 66.995 244.935 67.375 ;
        RECT 245.150 66.825 245.480 67.205 ;
        RECT 245.650 66.995 245.905 67.570 ;
        RECT 246.080 66.825 246.340 67.665 ;
        RECT 247.205 67.575 247.725 68.115 ;
        RECT 246.515 66.825 247.725 67.575 ;
        RECT 188.930 66.655 247.810 66.825 ;
        RECT 138.440 66.290 143.430 66.460 ;
        RECT 130.770 65.070 136.380 65.240 ;
        RECT 77.880 64.220 82.870 64.390 ;
        RECT 125.700 64.800 128.300 64.970 ;
        RECT 125.700 62.750 125.870 64.800 ;
        RECT 126.500 64.290 127.500 64.460 ;
        RECT 126.270 63.430 126.440 64.120 ;
        RECT 127.560 63.430 127.730 64.120 ;
        RECT 126.500 63.090 127.500 63.260 ;
        RECT 128.130 62.750 128.300 64.800 ;
        RECT 125.700 62.580 128.300 62.750 ;
        RECT 130.770 62.810 130.940 65.070 ;
        RECT 131.620 64.500 135.530 64.670 ;
        RECT 131.280 63.440 131.450 64.440 ;
        RECT 135.700 63.440 135.870 64.440 ;
        RECT 131.620 63.210 135.530 63.380 ;
        RECT 136.210 62.810 136.380 65.070 ;
        RECT 130.770 62.640 136.380 62.810 ;
        RECT 138.440 62.740 138.610 66.290 ;
        RECT 139.290 65.720 142.580 65.890 ;
        RECT 138.950 64.660 139.120 65.660 ;
        RECT 142.750 64.660 142.920 65.660 ;
        RECT 139.290 64.430 142.580 64.600 ;
        RECT 138.950 63.370 139.120 64.370 ;
        RECT 142.750 63.370 142.920 64.370 ;
        RECT 139.290 63.140 142.580 63.310 ;
        RECT 143.260 62.740 143.430 66.290 ;
        RECT 138.440 62.570 143.430 62.740 ;
      LAYER met1 ;
        RECT 103.390 131.850 103.650 131.865 ;
        RECT 103.375 131.560 103.665 131.850 ;
        RECT 103.390 131.545 103.650 131.560 ;
        RECT 66.455 131.090 66.775 131.095 ;
        RECT 140.265 131.090 140.585 131.095 ;
        RECT 66.455 130.840 68.575 131.090 ;
        RECT 138.465 130.840 140.585 131.090 ;
        RECT 66.455 130.835 66.775 130.840 ;
        RECT 140.265 130.835 140.585 130.840 ;
        RECT 169.830 129.730 170.090 129.745 ;
        RECT 169.815 129.440 170.105 129.730 ;
        RECT 169.830 129.425 170.090 129.440 ;
        RECT 145.995 128.970 146.315 128.975 ;
        RECT 193.605 128.970 193.925 128.975 ;
        RECT 53.875 128.935 54.125 128.950 ;
        RECT 56.625 128.935 56.875 128.950 ;
        RECT 53.840 128.675 54.160 128.935 ;
        RECT 56.590 128.675 56.910 128.935 ;
        RECT 103.150 128.900 103.410 128.915 ;
        RECT 53.875 126.845 54.125 128.675 ;
        RECT 56.625 126.845 56.875 128.675 ;
        RECT 103.135 128.610 103.425 128.900 ;
        RECT 145.995 128.720 148.115 128.970 ;
        RECT 191.805 128.720 193.925 128.970 ;
        RECT 145.995 128.715 146.315 128.720 ;
        RECT 193.605 128.715 193.925 128.720 ;
        RECT 103.150 128.595 103.410 128.610 ;
        RECT 66.215 128.140 66.535 128.145 ;
        RECT 140.025 128.140 140.345 128.145 ;
        RECT 66.215 127.890 68.335 128.140 ;
        RECT 138.225 127.890 140.345 128.140 ;
        RECT 66.215 127.885 66.535 127.890 ;
        RECT 140.025 127.885 140.345 127.890 ;
        RECT 169.830 126.540 170.090 126.555 ;
        RECT 169.815 126.250 170.105 126.540 ;
        RECT 169.830 126.235 170.090 126.250 ;
        RECT 145.995 125.780 146.315 125.785 ;
        RECT 193.605 125.780 193.925 125.785 ;
        RECT 145.995 125.530 148.115 125.780 ;
        RECT 191.805 125.530 193.925 125.780 ;
        RECT 145.995 125.525 146.315 125.530 ;
        RECT 193.605 125.525 193.925 125.530 ;
        RECT 103.030 125.480 103.290 125.495 ;
        RECT 103.015 125.190 103.305 125.480 ;
        RECT 103.030 125.175 103.290 125.190 ;
        RECT 66.095 124.720 66.415 124.725 ;
        RECT 139.905 124.720 140.225 124.725 ;
        RECT 66.095 124.470 68.215 124.720 ;
        RECT 138.105 124.470 140.225 124.720 ;
        RECT 66.095 124.465 66.415 124.470 ;
        RECT 139.905 124.465 140.225 124.470 ;
        RECT 169.950 122.410 170.210 122.425 ;
        RECT 102.920 122.290 103.180 122.305 ;
        RECT 102.905 122.000 103.195 122.290 ;
        RECT 169.935 122.120 170.225 122.410 ;
        RECT 169.950 122.105 170.210 122.120 ;
        RECT 102.920 121.985 103.180 122.000 ;
        RECT 146.115 121.650 146.435 121.655 ;
        RECT 193.725 121.650 194.045 121.655 ;
        RECT 65.985 121.530 66.305 121.535 ;
        RECT 139.795 121.530 140.115 121.535 ;
        RECT 65.985 121.280 68.105 121.530 ;
        RECT 137.995 121.280 140.115 121.530 ;
        RECT 146.115 121.400 148.235 121.650 ;
        RECT 191.925 121.400 194.045 121.650 ;
        RECT 146.115 121.395 146.435 121.400 ;
        RECT 193.725 121.395 194.045 121.400 ;
        RECT 65.985 121.275 66.305 121.280 ;
        RECT 139.795 121.275 140.115 121.280 ;
        RECT 169.830 119.340 170.090 119.355 ;
        RECT 103.220 119.320 103.480 119.335 ;
        RECT 103.205 119.030 103.495 119.320 ;
        RECT 169.815 119.050 170.105 119.340 ;
        RECT 169.830 119.035 170.090 119.050 ;
        RECT 103.220 119.015 103.480 119.030 ;
        RECT 145.995 118.580 146.315 118.585 ;
        RECT 193.605 118.580 193.925 118.585 ;
        RECT 66.285 118.560 66.605 118.565 ;
        RECT 140.095 118.560 140.415 118.565 ;
        RECT 66.285 118.310 68.405 118.560 ;
        RECT 138.295 118.310 140.415 118.560 ;
        RECT 145.995 118.330 148.115 118.580 ;
        RECT 191.805 118.330 193.925 118.580 ;
        RECT 145.995 118.325 146.315 118.330 ;
        RECT 193.605 118.325 193.925 118.330 ;
        RECT 66.285 118.305 66.605 118.310 ;
        RECT 140.095 118.305 140.415 118.310 ;
        RECT 80.580 112.910 81.580 113.910 ;
        RECT 141.720 112.430 142.720 113.430 ;
        RECT 188.930 112.740 247.810 113.220 ;
        RECT 243.740 112.340 244.060 112.600 ;
        RECT 245.580 112.000 245.900 112.260 ;
        RECT 240.060 111.520 240.380 111.580 ;
        RECT 242.835 111.520 243.125 111.565 ;
        RECT 240.060 111.380 243.125 111.520 ;
        RECT 240.060 111.320 240.380 111.380 ;
        RECT 242.835 111.335 243.125 111.380 ;
        RECT 243.280 111.520 243.600 111.580 ;
        RECT 244.675 111.520 244.965 111.565 ;
        RECT 243.280 111.380 244.965 111.520 ;
        RECT 243.280 111.320 243.600 111.380 ;
        RECT 244.675 111.335 244.965 111.380 ;
        RECT 188.930 110.020 247.810 110.500 ;
        RECT 71.730 109.870 72.230 110.005 ;
        RECT 65.860 109.670 66.360 109.805 ;
        RECT 65.195 109.440 67.025 109.670 ;
        RECT 71.065 109.640 72.895 109.870 ;
        RECT 77.270 109.740 77.770 109.875 ;
        RECT 61.500 108.050 62.500 109.050 ;
        RECT 54.610 105.145 54.870 105.160 ;
        RECT 55.880 105.145 56.140 105.160 ;
        RECT 54.595 104.855 54.885 105.145 ;
        RECT 55.865 104.855 56.155 105.145 ;
        RECT 54.610 104.840 54.870 104.855 ;
        RECT 55.880 104.840 56.140 104.855 ;
        RECT 64.760 102.710 64.990 109.390 ;
        RECT 65.860 109.305 66.360 109.440 ;
        RECT 65.860 108.380 66.360 108.515 ;
        RECT 67.230 108.430 67.460 109.390 ;
        RECT 65.195 108.150 67.025 108.380 ;
        RECT 65.860 108.015 66.360 108.150 ;
        RECT 65.860 107.090 66.360 107.225 ;
        RECT 67.230 107.140 67.460 108.100 ;
        RECT 65.195 106.860 67.025 107.090 ;
        RECT 65.860 106.725 66.360 106.860 ;
        RECT 65.860 105.800 66.360 105.935 ;
        RECT 67.230 105.850 67.460 106.810 ;
        RECT 65.195 105.570 67.025 105.800 ;
        RECT 65.860 105.435 66.360 105.570 ;
        RECT 65.860 104.510 66.360 104.645 ;
        RECT 67.230 104.560 67.460 105.520 ;
        RECT 67.605 105.435 68.105 105.935 ;
        RECT 65.195 104.280 67.025 104.510 ;
        RECT 65.860 104.145 66.360 104.280 ;
        RECT 65.860 103.220 66.360 103.355 ;
        RECT 67.230 103.270 67.460 104.230 ;
        RECT 65.195 102.990 67.025 103.220 ;
        RECT 65.860 102.855 66.360 102.990 ;
        RECT 64.625 102.210 65.125 102.710 ;
        RECT 64.760 101.980 64.990 102.210 ;
        RECT 65.860 101.930 66.360 102.065 ;
        RECT 67.230 101.980 67.460 102.940 ;
        RECT 70.630 102.910 70.860 109.590 ;
        RECT 71.730 109.505 72.230 109.640 ;
        RECT 71.730 108.580 72.230 108.715 ;
        RECT 73.100 108.630 73.330 109.590 ;
        RECT 77.040 109.510 89.610 109.740 ;
        RECT 77.270 109.375 77.770 109.510 ;
        RECT 132.870 109.390 133.370 109.525 ;
        RECT 232.815 109.480 233.105 109.525 ;
        RECT 236.055 109.480 236.705 109.525 ;
        RECT 71.065 108.350 72.895 108.580 ;
        RECT 71.730 108.215 72.230 108.350 ;
        RECT 71.730 107.290 72.230 107.425 ;
        RECT 73.100 107.340 73.330 108.300 ;
        RECT 71.065 107.060 72.895 107.290 ;
        RECT 71.730 106.925 72.230 107.060 ;
        RECT 71.730 106.000 72.230 106.135 ;
        RECT 73.100 106.050 73.330 107.010 ;
        RECT 76.760 106.305 76.990 109.305 ;
        RECT 78.050 106.305 78.280 109.305 ;
        RECT 79.340 106.305 79.570 109.305 ;
        RECT 80.630 106.305 80.860 109.305 ;
        RECT 81.920 106.305 82.150 109.305 ;
        RECT 83.210 106.305 83.440 109.305 ;
        RECT 84.500 106.305 84.730 109.305 ;
        RECT 85.790 106.305 86.020 109.305 ;
        RECT 87.080 106.305 87.310 109.305 ;
        RECT 88.370 106.305 88.600 109.305 ;
        RECT 89.660 106.305 89.890 109.305 ;
        RECT 127.000 109.190 127.500 109.325 ;
        RECT 126.335 108.960 128.165 109.190 ;
        RECT 132.205 109.160 134.035 109.390 ;
        RECT 138.410 109.260 138.910 109.395 ;
        RECT 232.815 109.340 236.705 109.480 ;
        RECT 232.815 109.295 233.405 109.340 ;
        RECT 236.055 109.295 236.705 109.340 ;
        RECT 122.640 107.570 123.640 108.570 ;
        RECT 71.065 105.770 72.895 106.000 ;
        RECT 71.730 105.635 72.230 105.770 ;
        RECT 71.730 104.710 72.230 104.845 ;
        RECT 73.100 104.760 73.330 105.720 ;
        RECT 73.475 105.635 73.975 106.135 ;
        RECT 76.625 105.805 77.125 106.305 ;
        RECT 77.915 105.805 78.415 106.305 ;
        RECT 79.205 105.805 79.705 106.305 ;
        RECT 80.495 105.805 80.995 106.305 ;
        RECT 81.785 105.805 82.285 106.305 ;
        RECT 83.075 105.805 83.575 106.305 ;
        RECT 84.365 105.805 84.865 106.305 ;
        RECT 85.655 105.805 86.155 106.305 ;
        RECT 86.945 105.805 87.445 106.305 ;
        RECT 88.235 105.805 88.735 106.305 ;
        RECT 89.525 105.805 90.025 106.305 ;
        RECT 71.065 104.480 72.895 104.710 ;
        RECT 71.730 104.345 72.230 104.480 ;
        RECT 71.730 103.420 72.230 103.555 ;
        RECT 73.100 103.470 73.330 104.430 ;
        RECT 71.065 103.190 72.895 103.420 ;
        RECT 71.730 103.055 72.230 103.190 ;
        RECT 70.495 102.410 70.995 102.910 ;
        RECT 70.630 102.180 70.860 102.410 ;
        RECT 71.730 102.130 72.230 102.265 ;
        RECT 73.100 102.180 73.330 103.140 ;
        RECT 76.760 102.805 76.990 105.805 ;
        RECT 78.050 102.805 78.280 105.805 ;
        RECT 79.340 102.805 79.570 105.805 ;
        RECT 80.630 102.805 80.860 105.805 ;
        RECT 81.920 102.805 82.150 105.805 ;
        RECT 83.210 102.805 83.440 105.805 ;
        RECT 84.500 102.805 84.730 105.805 ;
        RECT 85.790 102.805 86.020 105.805 ;
        RECT 87.080 102.805 87.310 105.805 ;
        RECT 88.370 102.805 88.600 105.805 ;
        RECT 89.660 102.805 89.890 105.805 ;
        RECT 77.040 102.370 78.000 102.600 ;
        RECT 78.330 102.370 79.290 102.600 ;
        RECT 79.620 102.370 80.580 102.600 ;
        RECT 80.910 102.370 81.870 102.600 ;
        RECT 82.200 102.370 83.160 102.600 ;
        RECT 83.490 102.370 84.450 102.600 ;
        RECT 84.780 102.370 85.740 102.600 ;
        RECT 86.070 102.370 87.030 102.600 ;
        RECT 87.360 102.370 88.320 102.600 ;
        RECT 88.650 102.370 89.610 102.600 ;
        RECT 125.900 102.230 126.130 108.910 ;
        RECT 127.000 108.825 127.500 108.960 ;
        RECT 127.000 107.900 127.500 108.035 ;
        RECT 128.370 107.950 128.600 108.910 ;
        RECT 126.335 107.670 128.165 107.900 ;
        RECT 127.000 107.535 127.500 107.670 ;
        RECT 127.000 106.610 127.500 106.745 ;
        RECT 128.370 106.660 128.600 107.620 ;
        RECT 126.335 106.380 128.165 106.610 ;
        RECT 127.000 106.245 127.500 106.380 ;
        RECT 127.000 105.320 127.500 105.455 ;
        RECT 128.370 105.370 128.600 106.330 ;
        RECT 126.335 105.090 128.165 105.320 ;
        RECT 127.000 104.955 127.500 105.090 ;
        RECT 127.000 104.030 127.500 104.165 ;
        RECT 128.370 104.080 128.600 105.040 ;
        RECT 128.745 104.955 129.245 105.455 ;
        RECT 126.335 103.800 128.165 104.030 ;
        RECT 127.000 103.665 127.500 103.800 ;
        RECT 127.000 102.740 127.500 102.875 ;
        RECT 128.370 102.790 128.600 103.750 ;
        RECT 126.335 102.510 128.165 102.740 ;
        RECT 127.000 102.375 127.500 102.510 ;
        RECT 65.195 101.700 67.025 101.930 ;
        RECT 71.065 101.900 72.895 102.130 ;
        RECT 71.730 101.765 72.230 101.900 ;
        RECT 83.075 101.725 83.575 102.225 ;
        RECT 125.765 101.730 126.265 102.230 ;
        RECT 65.860 101.565 66.360 101.700 ;
        RECT 125.900 101.500 126.130 101.730 ;
        RECT 127.000 101.450 127.500 101.585 ;
        RECT 128.370 101.500 128.600 102.460 ;
        RECT 131.770 102.430 132.000 109.110 ;
        RECT 132.870 109.025 133.370 109.160 ;
        RECT 132.870 108.100 133.370 108.235 ;
        RECT 134.240 108.150 134.470 109.110 ;
        RECT 138.180 109.030 150.750 109.260 ;
        RECT 187.620 109.140 187.940 109.200 ;
        RECT 190.395 109.140 190.685 109.185 ;
        RECT 138.410 108.895 138.910 109.030 ;
        RECT 187.620 109.000 190.685 109.140 ;
        RECT 187.620 108.940 187.940 109.000 ;
        RECT 190.395 108.955 190.685 109.000 ;
        RECT 233.115 108.980 233.405 109.295 ;
        RECT 234.195 109.140 234.485 109.185 ;
        RECT 237.775 109.140 238.065 109.185 ;
        RECT 239.610 109.140 239.900 109.185 ;
        RECT 234.195 109.000 239.900 109.140 ;
        RECT 132.205 107.870 134.035 108.100 ;
        RECT 132.870 107.735 133.370 107.870 ;
        RECT 132.870 106.810 133.370 106.945 ;
        RECT 134.240 106.860 134.470 107.820 ;
        RECT 132.205 106.580 134.035 106.810 ;
        RECT 132.870 106.445 133.370 106.580 ;
        RECT 132.870 105.520 133.370 105.655 ;
        RECT 134.240 105.570 134.470 106.530 ;
        RECT 137.900 105.825 138.130 108.825 ;
        RECT 139.190 105.825 139.420 108.825 ;
        RECT 140.480 105.825 140.710 108.825 ;
        RECT 141.770 105.825 142.000 108.825 ;
        RECT 143.060 105.825 143.290 108.825 ;
        RECT 144.350 105.825 144.580 108.825 ;
        RECT 145.640 105.825 145.870 108.825 ;
        RECT 146.930 105.825 147.160 108.825 ;
        RECT 148.220 105.825 148.450 108.825 ;
        RECT 149.510 105.825 149.740 108.825 ;
        RECT 150.800 105.825 151.030 108.825 ;
        RECT 191.315 108.460 191.605 108.505 ;
        RECT 233.250 108.460 233.390 108.980 ;
        RECT 234.195 108.955 234.485 109.000 ;
        RECT 237.775 108.955 238.065 109.000 ;
        RECT 239.610 108.955 239.900 109.000 ;
        RECT 238.220 108.800 238.540 108.860 ;
        RECT 238.695 108.800 238.985 108.845 ;
        RECT 238.220 108.660 238.985 108.800 ;
        RECT 238.220 108.600 238.540 108.660 ;
        RECT 238.695 108.615 238.985 108.660 ;
        RECT 240.075 108.615 240.365 108.845 ;
        RECT 233.620 108.460 233.940 108.520 ;
        RECT 191.315 108.320 233.940 108.460 ;
        RECT 191.315 108.275 191.605 108.320 ;
        RECT 233.620 108.260 233.940 108.320 ;
        RECT 234.195 108.460 234.485 108.505 ;
        RECT 237.315 108.460 237.605 108.505 ;
        RECT 239.205 108.460 239.495 108.505 ;
        RECT 234.195 108.320 239.495 108.460 ;
        RECT 234.195 108.275 234.485 108.320 ;
        RECT 237.315 108.275 237.605 108.320 ;
        RECT 239.205 108.275 239.495 108.320 ;
        RECT 230.860 108.120 231.180 108.180 ;
        RECT 231.335 108.120 231.625 108.165 ;
        RECT 230.860 107.980 231.625 108.120 ;
        RECT 230.860 107.920 231.180 107.980 ;
        RECT 231.335 107.935 231.625 107.980 ;
        RECT 237.760 108.120 238.080 108.180 ;
        RECT 240.150 108.120 240.290 108.615 ;
        RECT 237.760 107.980 240.290 108.120 ;
        RECT 237.760 107.920 238.080 107.980 ;
        RECT 188.930 107.300 247.810 107.780 ;
        RECT 238.220 106.900 238.540 107.160 ;
        RECT 237.760 106.220 238.080 106.480 ;
        RECT 238.680 106.420 239.000 106.480 ;
        RECT 241.455 106.420 241.745 106.465 ;
        RECT 243.280 106.420 243.600 106.480 ;
        RECT 238.680 106.280 243.600 106.420 ;
        RECT 238.680 106.220 239.000 106.280 ;
        RECT 241.455 106.235 241.745 106.280 ;
        RECT 243.280 106.220 243.600 106.280 ;
        RECT 244.660 105.880 244.980 106.140 ;
        RECT 132.205 105.290 134.035 105.520 ;
        RECT 132.870 105.155 133.370 105.290 ;
        RECT 132.870 104.230 133.370 104.365 ;
        RECT 134.240 104.280 134.470 105.240 ;
        RECT 134.615 105.155 135.115 105.655 ;
        RECT 137.765 105.325 138.265 105.825 ;
        RECT 139.055 105.325 139.555 105.825 ;
        RECT 140.345 105.325 140.845 105.825 ;
        RECT 141.635 105.325 142.135 105.825 ;
        RECT 142.925 105.325 143.425 105.825 ;
        RECT 144.215 105.325 144.715 105.825 ;
        RECT 145.505 105.325 146.005 105.825 ;
        RECT 146.795 105.325 147.295 105.825 ;
        RECT 148.085 105.325 148.585 105.825 ;
        RECT 149.375 105.325 149.875 105.825 ;
        RECT 150.665 105.325 151.165 105.825 ;
        RECT 229.035 105.740 229.325 105.785 ;
        RECT 229.480 105.740 229.800 105.800 ;
        RECT 229.035 105.600 229.800 105.740 ;
        RECT 229.035 105.555 229.325 105.600 ;
        RECT 229.480 105.540 229.800 105.600 ;
        RECT 132.205 104.000 134.035 104.230 ;
        RECT 132.870 103.865 133.370 104.000 ;
        RECT 132.870 102.940 133.370 103.075 ;
        RECT 134.240 102.990 134.470 103.950 ;
        RECT 132.205 102.710 134.035 102.940 ;
        RECT 132.870 102.575 133.370 102.710 ;
        RECT 131.635 101.930 132.135 102.430 ;
        RECT 131.770 101.700 132.000 101.930 ;
        RECT 132.870 101.650 133.370 101.785 ;
        RECT 134.240 101.700 134.470 102.660 ;
        RECT 137.900 102.325 138.130 105.325 ;
        RECT 139.190 102.325 139.420 105.325 ;
        RECT 140.480 102.325 140.710 105.325 ;
        RECT 141.770 102.325 142.000 105.325 ;
        RECT 143.060 102.325 143.290 105.325 ;
        RECT 144.350 102.325 144.580 105.325 ;
        RECT 145.640 102.325 145.870 105.325 ;
        RECT 146.930 102.325 147.160 105.325 ;
        RECT 148.220 102.325 148.450 105.325 ;
        RECT 149.510 102.325 149.740 105.325 ;
        RECT 150.800 102.325 151.030 105.325 ;
        RECT 245.580 105.200 245.900 105.460 ;
        RECT 188.930 104.580 247.810 105.060 ;
        RECT 238.680 104.180 239.000 104.440 ;
        RECT 233.620 104.085 233.940 104.100 ;
        RECT 233.615 104.040 234.265 104.085 ;
        RECT 237.215 104.040 237.505 104.085 ;
        RECT 233.615 103.900 237.505 104.040 ;
        RECT 233.615 103.855 234.265 103.900 ;
        RECT 236.915 103.855 237.505 103.900 ;
        RECT 233.620 103.840 233.940 103.855 ;
        RECT 230.420 103.700 230.710 103.745 ;
        RECT 232.255 103.700 232.545 103.745 ;
        RECT 235.835 103.700 236.125 103.745 ;
        RECT 230.420 103.560 236.125 103.700 ;
        RECT 230.420 103.515 230.710 103.560 ;
        RECT 232.255 103.515 232.545 103.560 ;
        RECT 235.835 103.515 236.125 103.560 ;
        RECT 236.915 103.540 237.205 103.855 ;
        RECT 239.140 103.500 239.460 103.760 ;
        RECT 229.955 103.175 230.245 103.405 ;
        RECT 231.335 103.360 231.625 103.405 ;
        RECT 237.300 103.360 237.620 103.420 ;
        RECT 231.335 103.220 237.620 103.360 ;
        RECT 231.335 103.175 231.625 103.220 ;
        RECT 230.030 102.680 230.170 103.175 ;
        RECT 237.300 103.160 237.620 103.220 ;
        RECT 230.825 103.020 231.115 103.065 ;
        RECT 232.715 103.020 233.005 103.065 ;
        RECT 235.835 103.020 236.125 103.065 ;
        RECT 230.825 102.880 236.125 103.020 ;
        RECT 230.825 102.835 231.115 102.880 ;
        RECT 232.715 102.835 233.005 102.880 ;
        RECT 235.835 102.835 236.125 102.880 ;
        RECT 240.060 102.820 240.380 103.080 ;
        RECT 234.080 102.680 234.400 102.740 ;
        RECT 237.760 102.680 238.080 102.740 ;
        RECT 230.030 102.540 238.080 102.680 ;
        RECT 234.080 102.480 234.400 102.540 ;
        RECT 237.760 102.480 238.080 102.540 ;
        RECT 138.180 101.890 139.140 102.120 ;
        RECT 139.470 101.890 140.430 102.120 ;
        RECT 140.760 101.890 141.720 102.120 ;
        RECT 142.050 101.890 143.010 102.120 ;
        RECT 143.340 101.890 144.300 102.120 ;
        RECT 144.630 101.890 145.590 102.120 ;
        RECT 145.920 101.890 146.880 102.120 ;
        RECT 147.210 101.890 148.170 102.120 ;
        RECT 148.500 101.890 149.460 102.120 ;
        RECT 149.790 101.890 150.750 102.120 ;
        RECT 188.930 101.860 247.810 102.340 ;
        RECT 126.335 101.220 128.165 101.450 ;
        RECT 132.205 101.420 134.035 101.650 ;
        RECT 132.870 101.285 133.370 101.420 ;
        RECT 144.215 101.245 144.715 101.745 ;
        RECT 237.300 101.460 237.620 101.720 ;
        RECT 230.975 101.320 231.265 101.365 ;
        RECT 234.095 101.320 234.385 101.365 ;
        RECT 235.985 101.320 236.275 101.365 ;
        RECT 127.000 101.085 127.500 101.220 ;
        RECT 230.975 101.180 236.275 101.320 ;
        RECT 230.975 101.135 231.265 101.180 ;
        RECT 234.095 101.135 234.385 101.180 ;
        RECT 235.985 101.135 236.275 101.180 ;
        RECT 236.470 101.180 240.750 101.320 ;
        RECT 228.115 100.980 228.405 101.025 ;
        RECT 230.400 100.980 230.720 101.040 ;
        RECT 236.470 100.980 236.610 101.180 ;
        RECT 228.115 100.840 236.610 100.980 ;
        RECT 236.855 100.980 237.145 101.025 ;
        RECT 237.760 100.980 238.080 101.040 ;
        RECT 240.610 101.025 240.750 101.180 ;
        RECT 236.855 100.840 238.080 100.980 ;
        RECT 228.115 100.795 228.405 100.840 ;
        RECT 230.400 100.780 230.720 100.840 ;
        RECT 236.855 100.795 237.145 100.840 ;
        RECT 237.760 100.780 238.080 100.840 ;
        RECT 240.535 100.980 240.825 101.025 ;
        RECT 244.660 100.980 244.980 101.040 ;
        RECT 240.535 100.840 244.980 100.980 ;
        RECT 240.535 100.795 240.825 100.840 ;
        RECT 244.660 100.780 244.980 100.840 ;
        RECT 65.750 99.235 66.250 100.410 ;
        RECT 71.560 99.235 72.060 100.410 ;
        RECT 229.895 100.345 230.185 100.660 ;
        RECT 230.975 100.640 231.265 100.685 ;
        RECT 234.555 100.640 234.845 100.685 ;
        RECT 236.390 100.640 236.680 100.685 ;
        RECT 230.975 100.500 236.680 100.640 ;
        RECT 230.975 100.455 231.265 100.500 ;
        RECT 234.555 100.455 234.845 100.500 ;
        RECT 236.390 100.455 236.680 100.500 ;
        RECT 233.160 100.345 233.480 100.360 ;
        RECT 229.595 100.300 230.185 100.345 ;
        RECT 232.835 100.300 233.485 100.345 ;
        RECT 229.595 100.160 233.485 100.300 ;
        RECT 229.595 100.115 229.885 100.160 ;
        RECT 232.835 100.115 233.485 100.160 ;
        RECT 235.000 100.300 235.320 100.360 ;
        RECT 235.475 100.300 235.765 100.345 ;
        RECT 235.000 100.160 235.765 100.300 ;
        RECT 233.160 100.100 233.480 100.115 ;
        RECT 235.000 100.100 235.320 100.160 ;
        RECT 235.475 100.115 235.765 100.160 ;
        RECT 65.770 99.050 66.230 99.235 ;
        RECT 71.580 99.050 72.040 99.235 ;
        RECT 61.900 97.970 62.900 98.970 ;
        RECT 65.490 98.640 65.720 98.890 ;
        RECT 66.280 98.640 66.510 98.890 ;
        RECT 71.300 98.640 71.530 98.890 ;
        RECT 72.090 98.640 72.320 98.890 ;
        RECT 65.355 98.140 65.855 98.640 ;
        RECT 66.145 98.140 66.645 98.640 ;
        RECT 71.165 98.140 71.665 98.640 ;
        RECT 71.955 98.140 72.455 98.640 ;
        RECT 74.840 98.170 75.840 99.170 ;
        RECT 81.265 99.125 81.765 99.625 ;
        RECT 82.005 99.500 82.505 99.625 ;
        RECT 86.985 99.500 87.485 99.625 ;
        RECT 82.005 99.250 84.215 99.500 ;
        RECT 85.275 99.250 87.485 99.500 ;
        RECT 82.005 99.125 82.505 99.250 ;
        RECT 86.985 99.125 87.485 99.250 ;
        RECT 126.890 98.755 127.390 99.930 ;
        RECT 132.700 98.755 133.200 99.930 ;
        RECT 126.910 98.570 127.370 98.755 ;
        RECT 132.720 98.570 133.180 98.755 ;
        RECT 65.490 97.890 65.720 98.140 ;
        RECT 66.280 97.890 66.510 98.140 ;
        RECT 71.300 97.890 71.530 98.140 ;
        RECT 72.090 97.890 72.320 98.140 ;
        RECT 65.770 97.500 66.230 97.730 ;
        RECT 71.580 97.500 72.040 97.730 ;
        RECT 123.040 97.490 124.040 98.490 ;
        RECT 126.630 98.160 126.860 98.410 ;
        RECT 127.420 98.160 127.650 98.410 ;
        RECT 132.440 98.160 132.670 98.410 ;
        RECT 133.230 98.160 133.460 98.410 ;
        RECT 126.495 97.660 126.995 98.160 ;
        RECT 127.285 97.660 127.785 98.160 ;
        RECT 132.305 97.660 132.805 98.160 ;
        RECT 133.095 97.660 133.595 98.160 ;
        RECT 135.980 97.690 136.980 98.690 ;
        RECT 142.405 98.645 142.905 99.145 ;
        RECT 143.145 99.020 143.645 99.145 ;
        RECT 148.125 99.020 148.625 99.145 ;
        RECT 188.930 99.140 247.810 99.620 ;
        RECT 143.145 98.770 145.355 99.020 ;
        RECT 146.415 98.770 148.625 99.020 ;
        RECT 143.145 98.645 143.645 98.770 ;
        RECT 148.125 98.645 148.625 98.770 ;
        RECT 235.000 98.740 235.320 99.000 ;
        RECT 230.400 98.060 230.720 98.320 ;
        RECT 231.320 98.260 231.640 98.320 ;
        RECT 232.255 98.260 232.545 98.305 ;
        RECT 244.675 98.260 244.965 98.305 ;
        RECT 231.320 98.120 244.965 98.260 ;
        RECT 231.320 98.060 231.640 98.120 ;
        RECT 232.255 98.075 232.545 98.120 ;
        RECT 244.675 98.075 244.965 98.120 ;
        RECT 230.860 97.920 231.180 97.980 ;
        RECT 239.140 97.920 239.460 97.980 ;
        RECT 178.475 97.880 178.795 97.895 ;
        RECT 177.200 97.675 177.430 97.690 ;
        RECT 126.630 97.410 126.860 97.660 ;
        RECT 127.420 97.410 127.650 97.660 ;
        RECT 132.440 97.410 132.670 97.660 ;
        RECT 133.230 97.410 133.460 97.660 ;
        RECT 177.105 97.415 177.430 97.675 ;
        RECT 177.635 97.650 179.635 97.880 ;
        RECT 230.860 97.780 239.460 97.920 ;
        RECT 230.860 97.720 231.180 97.780 ;
        RECT 239.140 97.720 239.460 97.780 ;
        RECT 180.335 97.690 180.595 97.705 ;
        RECT 179.840 97.675 180.070 97.690 ;
        RECT 178.475 97.635 178.795 97.650 ;
        RECT 178.475 97.440 178.795 97.455 ;
        RECT 177.200 97.400 177.430 97.415 ;
        RECT 65.800 97.280 66.200 97.305 ;
        RECT 63.070 97.105 66.200 97.280 ;
        RECT 62.895 96.930 66.200 97.105 ;
        RECT 62.895 96.660 63.245 96.930 ;
        RECT 65.800 96.905 66.200 96.930 ;
        RECT 71.610 97.280 72.010 97.305 ;
        RECT 71.610 97.105 74.070 97.280 ;
        RECT 71.610 96.930 74.245 97.105 ;
        RECT 126.910 97.020 127.370 97.250 ;
        RECT 132.720 97.020 133.180 97.250 ;
        RECT 177.635 97.210 179.635 97.440 ;
        RECT 179.840 97.415 180.165 97.675 ;
        RECT 179.840 97.400 180.070 97.415 ;
        RECT 180.320 97.400 180.610 97.690 ;
        RECT 180.335 97.385 180.595 97.400 ;
        RECT 245.580 97.380 245.900 97.640 ;
        RECT 229.035 97.240 229.325 97.285 ;
        RECT 229.940 97.240 230.260 97.300 ;
        RECT 178.475 97.195 178.795 97.210 ;
        RECT 229.035 97.100 230.260 97.240 ;
        RECT 229.035 97.055 229.325 97.100 ;
        RECT 229.940 97.040 230.260 97.100 ;
        RECT 71.610 96.905 72.010 96.930 ;
        RECT 73.895 96.660 74.245 96.930 ;
        RECT 126.940 96.800 127.340 96.825 ;
        RECT 62.820 96.160 63.320 96.660 ;
        RECT 73.820 96.160 74.320 96.660 ;
        RECT 124.210 96.625 127.340 96.800 ;
        RECT 124.035 96.450 127.340 96.625 ;
        RECT 79.735 96.100 80.235 96.235 ;
        RECT 124.035 96.180 124.385 96.450 ;
        RECT 126.940 96.425 127.340 96.450 ;
        RECT 132.750 96.800 133.150 96.825 ;
        RECT 132.750 96.625 135.210 96.800 ;
        RECT 132.750 96.450 135.385 96.625 ;
        RECT 132.750 96.425 133.150 96.450 ;
        RECT 135.035 96.180 135.385 96.450 ;
        RECT 188.930 96.420 247.810 96.900 ;
        RECT 78.360 95.870 81.610 96.100 ;
        RECT 77.970 95.480 78.200 95.820 ;
        RECT 79.735 95.735 80.235 95.870 ;
        RECT 72.375 94.880 72.875 95.015 ;
        RECT 65.800 94.670 66.300 94.805 ;
        RECT 65.570 94.440 66.530 94.670 ;
        RECT 70.690 94.650 74.560 94.880 ;
        RECT 65.800 94.305 66.300 94.440 ;
        RECT 70.300 94.370 70.530 94.600 ;
        RECT 72.375 94.515 72.875 94.650 ;
        RECT 65.290 94.205 65.520 94.280 ;
        RECT 66.580 94.205 66.810 94.280 ;
        RECT 65.155 93.705 65.655 94.205 ;
        RECT 66.445 93.705 66.945 94.205 ;
        RECT 70.165 93.870 70.665 94.370 ;
        RECT 65.290 93.630 65.520 93.705 ;
        RECT 66.580 93.630 66.810 93.705 ;
        RECT 70.300 93.640 70.530 93.870 ;
        RECT 72.375 93.590 72.875 93.725 ;
        RECT 74.720 93.640 74.950 94.600 ;
        RECT 75.095 93.870 75.595 94.370 ;
        RECT 77.965 94.300 78.205 95.480 ;
        RECT 79.735 94.810 80.235 94.945 ;
        RECT 81.770 94.860 82.000 95.820 ;
        RECT 78.360 94.580 81.610 94.810 ;
        RECT 79.735 94.445 80.235 94.580 ;
        RECT 77.835 93.800 78.335 94.300 ;
        RECT 65.570 93.240 66.530 93.470 ;
        RECT 70.690 93.360 74.560 93.590 ;
        RECT 77.970 93.570 78.200 93.800 ;
        RECT 79.735 93.520 80.235 93.655 ;
        RECT 81.770 93.570 82.000 94.530 ;
        RECT 82.145 94.445 82.645 94.945 ;
        RECT 88.720 94.910 89.720 95.910 ;
        RECT 123.960 95.680 124.460 96.180 ;
        RECT 134.960 95.680 135.460 96.180 ;
        RECT 140.875 95.620 141.375 95.755 ;
        RECT 139.500 95.390 142.750 95.620 ;
        RECT 228.560 95.540 228.880 95.600 ;
        RECT 229.495 95.540 229.785 95.585 ;
        RECT 139.110 95.000 139.340 95.340 ;
        RECT 140.875 95.255 141.375 95.390 ;
        RECT 133.515 94.400 134.015 94.535 ;
        RECT 126.940 94.190 127.440 94.325 ;
        RECT 126.710 93.960 127.670 94.190 ;
        RECT 131.830 94.170 135.700 94.400 ;
        RECT 126.940 93.825 127.440 93.960 ;
        RECT 131.440 93.890 131.670 94.120 ;
        RECT 133.515 94.035 134.015 94.170 ;
        RECT 126.430 93.725 126.660 93.800 ;
        RECT 127.720 93.725 127.950 93.800 ;
        RECT 72.375 93.225 72.875 93.360 ;
        RECT 78.360 93.290 81.610 93.520 ;
        RECT 79.735 93.155 80.235 93.290 ;
        RECT 126.295 93.225 126.795 93.725 ;
        RECT 127.585 93.225 128.085 93.725 ;
        RECT 131.305 93.390 131.805 93.890 ;
        RECT 126.430 93.150 126.660 93.225 ;
        RECT 127.720 93.150 127.950 93.225 ;
        RECT 131.440 93.160 131.670 93.390 ;
        RECT 133.515 93.110 134.015 93.245 ;
        RECT 135.860 93.160 136.090 94.120 ;
        RECT 136.235 93.390 136.735 93.890 ;
        RECT 139.105 93.820 139.345 95.000 ;
        RECT 140.875 94.330 141.375 94.465 ;
        RECT 142.910 94.380 143.140 95.340 ;
        RECT 139.500 94.100 142.750 94.330 ;
        RECT 140.875 93.965 141.375 94.100 ;
        RECT 138.975 93.320 139.475 93.820 ;
        RECT 65.800 92.595 66.300 93.095 ;
        RECT 126.710 92.760 127.670 92.990 ;
        RECT 131.830 92.880 135.700 93.110 ;
        RECT 139.110 93.090 139.340 93.320 ;
        RECT 140.875 93.040 141.375 93.175 ;
        RECT 142.910 93.090 143.140 94.050 ;
        RECT 143.285 93.965 143.785 94.465 ;
        RECT 149.860 94.430 150.860 95.430 ;
        RECT 228.560 95.400 229.785 95.540 ;
        RECT 228.560 95.340 228.880 95.400 ;
        RECT 229.495 95.355 229.785 95.400 ;
        RECT 229.940 95.000 230.260 95.260 ;
        RECT 230.400 94.520 230.720 94.580 ;
        RECT 231.795 94.520 232.085 94.565 ;
        RECT 178.430 94.460 178.750 94.475 ;
        RECT 177.700 94.255 177.930 94.270 ;
        RECT 177.605 93.995 177.930 94.255 ;
        RECT 178.090 94.230 179.090 94.460 ;
        RECT 230.400 94.380 232.085 94.520 ;
        RECT 230.400 94.320 230.720 94.380 ;
        RECT 231.795 94.335 232.085 94.380 ;
        RECT 179.745 94.270 180.005 94.285 ;
        RECT 179.250 94.255 179.480 94.270 ;
        RECT 178.430 94.215 178.750 94.230 ;
        RECT 178.430 94.020 178.750 94.035 ;
        RECT 177.700 93.980 177.930 93.995 ;
        RECT 178.090 93.790 179.090 94.020 ;
        RECT 179.250 93.995 179.575 94.255 ;
        RECT 179.250 93.980 179.480 93.995 ;
        RECT 179.730 93.980 180.020 94.270 ;
        RECT 179.745 93.965 180.005 93.980 ;
        RECT 178.430 93.775 178.750 93.790 ;
        RECT 188.930 93.700 247.810 94.180 ;
        RECT 225.355 93.500 225.645 93.545 ;
        RECT 226.260 93.500 226.580 93.560 ;
        RECT 231.320 93.500 231.640 93.560 ;
        RECT 225.355 93.360 231.640 93.500 ;
        RECT 225.355 93.315 225.645 93.360 ;
        RECT 226.260 93.300 226.580 93.360 ;
        RECT 231.320 93.300 231.640 93.360 ;
        RECT 226.835 93.160 227.125 93.205 ;
        RECT 230.075 93.160 230.725 93.205 ;
        RECT 233.160 93.160 233.480 93.220 ;
        RECT 133.515 92.745 134.015 92.880 ;
        RECT 139.500 92.810 142.750 93.040 ;
        RECT 226.835 93.020 233.480 93.160 ;
        RECT 226.835 92.975 227.425 93.020 ;
        RECT 230.075 92.975 230.725 93.020 ;
        RECT 140.875 92.675 141.375 92.810 ;
        RECT 227.135 92.660 227.425 92.975 ;
        RECT 233.160 92.960 233.480 93.020 ;
        RECT 228.215 92.820 228.505 92.865 ;
        RECT 231.795 92.820 232.085 92.865 ;
        RECT 233.630 92.820 233.920 92.865 ;
        RECT 228.215 92.680 233.920 92.820 ;
        RECT 228.215 92.635 228.505 92.680 ;
        RECT 231.795 92.635 232.085 92.680 ;
        RECT 233.630 92.635 233.920 92.680 ;
        RECT 234.080 92.620 234.400 92.880 ;
        RECT 244.675 92.635 244.965 92.865 ;
        RECT 126.940 92.115 127.440 92.615 ;
        RECT 232.700 92.280 233.020 92.540 ;
        RECT 228.215 92.140 228.505 92.185 ;
        RECT 231.335 92.140 231.625 92.185 ;
        RECT 233.225 92.140 233.515 92.185 ;
        RECT 228.215 92.000 233.515 92.140 ;
        RECT 228.215 91.955 228.505 92.000 ;
        RECT 231.335 91.955 231.625 92.000 ;
        RECT 233.225 91.955 233.515 92.000 ;
        RECT 229.940 91.800 230.260 91.860 ;
        RECT 244.750 91.800 244.890 92.635 ;
        RECT 229.940 91.660 244.890 91.800 ;
        RECT 229.940 91.600 230.260 91.660 ;
        RECT 245.580 91.600 245.900 91.860 ;
        RECT 188.930 90.980 247.810 91.460 ;
        RECT 80.310 88.840 81.310 89.840 ;
        RECT 141.450 88.360 142.450 89.360 ;
        RECT 229.020 89.220 229.340 89.480 ;
        RECT 229.480 89.080 229.800 89.140 ;
        RECT 235.475 89.080 235.765 89.125 ;
        RECT 229.480 88.940 235.765 89.080 ;
        RECT 229.480 88.880 229.800 88.940 ;
        RECT 235.475 88.895 235.765 88.940 ;
        RECT 188.930 88.260 247.810 88.740 ;
        RECT 178.515 88.140 178.835 88.155 ;
        RECT 177.240 87.935 177.470 87.950 ;
        RECT 177.145 87.675 177.470 87.935 ;
        RECT 177.675 87.910 179.675 88.140 ;
        RECT 232.255 88.060 232.545 88.105 ;
        RECT 232.700 88.060 233.020 88.120 ;
        RECT 180.375 87.950 180.635 87.965 ;
        RECT 179.880 87.935 180.110 87.950 ;
        RECT 178.515 87.895 178.835 87.910 ;
        RECT 178.515 87.700 178.835 87.715 ;
        RECT 177.240 87.660 177.470 87.675 ;
        RECT 177.675 87.470 179.675 87.700 ;
        RECT 179.880 87.675 180.205 87.935 ;
        RECT 179.880 87.660 180.110 87.675 ;
        RECT 180.360 87.660 180.650 87.950 ;
        RECT 232.255 87.920 233.020 88.060 ;
        RECT 232.255 87.875 232.545 87.920 ;
        RECT 232.700 87.860 233.020 87.920 ;
        RECT 180.375 87.645 180.635 87.660 ;
        RECT 178.515 87.455 178.835 87.470 ;
        RECT 226.260 87.380 226.580 87.440 ;
        RECT 226.735 87.380 227.025 87.425 ;
        RECT 226.260 87.240 227.025 87.380 ;
        RECT 226.260 87.180 226.580 87.240 ;
        RECT 226.735 87.195 227.025 87.240 ;
        RECT 227.195 86.855 227.485 87.085 ;
        RECT 227.270 86.700 227.410 86.855 ;
        RECT 228.560 86.840 228.880 87.100 ;
        RECT 229.495 87.040 229.785 87.085 ;
        RECT 229.940 87.040 230.260 87.100 ;
        RECT 231.320 87.040 231.640 87.100 ;
        RECT 229.495 86.900 231.640 87.040 ;
        RECT 229.495 86.855 229.785 86.900 ;
        RECT 229.570 86.700 229.710 86.855 ;
        RECT 229.940 86.840 230.260 86.900 ;
        RECT 231.320 86.840 231.640 86.900 ;
        RECT 227.270 86.560 229.710 86.700 ;
        RECT 188.930 85.540 247.810 86.020 ;
        RECT 80.970 84.380 81.970 85.380 ;
        RECT 178.390 84.720 178.710 84.735 ;
        RECT 177.660 84.515 177.890 84.530 ;
        RECT 177.565 84.255 177.890 84.515 ;
        RECT 178.050 84.490 179.050 84.720 ;
        RECT 179.705 84.530 179.965 84.545 ;
        RECT 179.210 84.515 179.440 84.530 ;
        RECT 178.390 84.475 178.710 84.490 ;
        RECT 178.390 84.280 178.710 84.295 ;
        RECT 177.660 84.240 177.890 84.255 ;
        RECT 178.050 84.050 179.050 84.280 ;
        RECT 179.210 84.255 179.535 84.515 ;
        RECT 179.210 84.240 179.440 84.255 ;
        RECT 179.690 84.240 179.980 84.530 ;
        RECT 179.705 84.225 179.965 84.240 ;
        RECT 244.660 84.120 244.980 84.380 ;
        RECT 178.390 84.035 178.710 84.050 ;
        RECT 53.875 81.325 54.125 83.155 ;
        RECT 56.625 81.325 56.875 83.155 ;
        RECT 141.530 82.730 142.530 83.730 ;
        RECT 245.580 83.440 245.900 83.700 ;
        RECT 188.930 82.820 247.810 83.300 ;
        RECT 231.320 82.420 231.640 82.680 ;
        RECT 232.815 82.280 233.105 82.325 ;
        RECT 235.000 82.280 235.320 82.340 ;
        RECT 236.055 82.280 236.705 82.325 ;
        RECT 232.815 82.140 236.705 82.280 ;
        RECT 232.815 82.095 233.405 82.140 ;
        RECT 233.115 81.780 233.405 82.095 ;
        RECT 235.000 82.080 235.320 82.140 ;
        RECT 236.055 82.095 236.705 82.140 ;
        RECT 234.195 81.940 234.485 81.985 ;
        RECT 237.775 81.940 238.065 81.985 ;
        RECT 239.610 81.940 239.900 81.985 ;
        RECT 234.195 81.800 239.900 81.940 ;
        RECT 234.195 81.755 234.485 81.800 ;
        RECT 237.775 81.755 238.065 81.800 ;
        RECT 239.610 81.755 239.900 81.800 ;
        RECT 72.120 81.340 72.620 81.475 ;
        RECT 238.680 81.400 239.000 81.660 ;
        RECT 240.075 81.600 240.365 81.645 ;
        RECT 243.740 81.600 244.060 81.660 ;
        RECT 240.075 81.460 244.060 81.600 ;
        RECT 240.075 81.415 240.365 81.460 ;
        RECT 243.740 81.400 244.060 81.460 ;
        RECT 53.840 81.065 54.160 81.325 ;
        RECT 56.590 81.065 56.910 81.325 ;
        RECT 66.250 81.140 66.750 81.275 ;
        RECT 53.875 81.050 54.125 81.065 ;
        RECT 56.625 81.050 56.875 81.065 ;
        RECT 65.585 80.910 67.415 81.140 ;
        RECT 71.455 81.110 73.285 81.340 ;
        RECT 77.660 81.210 78.160 81.345 ;
        RECT 234.195 81.260 234.485 81.305 ;
        RECT 237.315 81.260 237.605 81.305 ;
        RECT 239.205 81.260 239.495 81.305 ;
        RECT 61.890 79.520 62.890 80.520 ;
        RECT 65.150 74.180 65.380 80.860 ;
        RECT 66.250 80.775 66.750 80.910 ;
        RECT 66.250 79.850 66.750 79.985 ;
        RECT 67.620 79.900 67.850 80.860 ;
        RECT 65.585 79.620 67.415 79.850 ;
        RECT 66.250 79.485 66.750 79.620 ;
        RECT 66.250 78.560 66.750 78.695 ;
        RECT 67.620 78.610 67.850 79.570 ;
        RECT 65.585 78.330 67.415 78.560 ;
        RECT 66.250 78.195 66.750 78.330 ;
        RECT 66.250 77.270 66.750 77.405 ;
        RECT 67.620 77.320 67.850 78.280 ;
        RECT 65.585 77.040 67.415 77.270 ;
        RECT 66.250 76.905 66.750 77.040 ;
        RECT 66.250 75.980 66.750 76.115 ;
        RECT 67.620 76.030 67.850 76.990 ;
        RECT 67.995 76.905 68.495 77.405 ;
        RECT 65.585 75.750 67.415 75.980 ;
        RECT 66.250 75.615 66.750 75.750 ;
        RECT 66.250 74.690 66.750 74.825 ;
        RECT 67.620 74.740 67.850 75.700 ;
        RECT 65.585 74.460 67.415 74.690 ;
        RECT 66.250 74.325 66.750 74.460 ;
        RECT 65.015 73.680 65.515 74.180 ;
        RECT 65.150 73.450 65.380 73.680 ;
        RECT 66.250 73.400 66.750 73.535 ;
        RECT 67.620 73.450 67.850 74.410 ;
        RECT 71.020 74.380 71.250 81.060 ;
        RECT 72.120 80.975 72.620 81.110 ;
        RECT 72.120 80.050 72.620 80.185 ;
        RECT 73.490 80.100 73.720 81.060 ;
        RECT 77.430 80.980 90.000 81.210 ;
        RECT 234.195 81.120 239.495 81.260 ;
        RECT 234.195 81.075 234.485 81.120 ;
        RECT 237.315 81.075 237.605 81.120 ;
        RECT 239.205 81.075 239.495 81.120 ;
        RECT 77.660 80.845 78.160 80.980 ;
        RECT 71.455 79.820 73.285 80.050 ;
        RECT 72.120 79.685 72.620 79.820 ;
        RECT 72.120 78.760 72.620 78.895 ;
        RECT 73.490 78.810 73.720 79.770 ;
        RECT 71.455 78.530 73.285 78.760 ;
        RECT 72.120 78.395 72.620 78.530 ;
        RECT 72.120 77.470 72.620 77.605 ;
        RECT 73.490 77.520 73.720 78.480 ;
        RECT 77.150 77.775 77.380 80.775 ;
        RECT 78.440 77.775 78.670 80.775 ;
        RECT 79.730 77.775 79.960 80.775 ;
        RECT 81.020 77.775 81.250 80.775 ;
        RECT 82.310 77.775 82.540 80.775 ;
        RECT 83.600 77.775 83.830 80.775 ;
        RECT 84.890 77.775 85.120 80.775 ;
        RECT 86.180 77.775 86.410 80.775 ;
        RECT 87.470 77.775 87.700 80.775 ;
        RECT 88.760 77.775 88.990 80.775 ;
        RECT 90.050 77.775 90.280 80.775 ;
        RECT 188.930 80.100 247.810 80.580 ;
        RECT 238.680 79.900 239.000 79.960 ;
        RECT 239.615 79.900 239.905 79.945 ;
        RECT 132.680 79.690 133.180 79.825 ;
        RECT 238.680 79.760 239.905 79.900 ;
        RECT 238.680 79.700 239.000 79.760 ;
        RECT 239.615 79.715 239.905 79.760 ;
        RECT 126.810 79.490 127.310 79.625 ;
        RECT 126.145 79.260 127.975 79.490 ;
        RECT 132.015 79.460 133.845 79.690 ;
        RECT 138.220 79.560 138.720 79.695 ;
        RECT 178.375 79.580 178.695 79.595 ;
        RECT 122.450 77.870 123.450 78.870 ;
        RECT 71.455 77.240 73.285 77.470 ;
        RECT 72.120 77.105 72.620 77.240 ;
        RECT 72.120 76.180 72.620 76.315 ;
        RECT 73.490 76.230 73.720 77.190 ;
        RECT 73.865 77.105 74.365 77.605 ;
        RECT 77.015 77.275 77.515 77.775 ;
        RECT 78.305 77.275 78.805 77.775 ;
        RECT 79.595 77.275 80.095 77.775 ;
        RECT 80.885 77.275 81.385 77.775 ;
        RECT 82.175 77.275 82.675 77.775 ;
        RECT 83.465 77.275 83.965 77.775 ;
        RECT 84.755 77.275 85.255 77.775 ;
        RECT 86.045 77.275 86.545 77.775 ;
        RECT 87.335 77.275 87.835 77.775 ;
        RECT 88.625 77.275 89.125 77.775 ;
        RECT 89.915 77.275 90.415 77.775 ;
        RECT 71.455 75.950 73.285 76.180 ;
        RECT 72.120 75.815 72.620 75.950 ;
        RECT 72.120 74.890 72.620 75.025 ;
        RECT 73.490 74.940 73.720 75.900 ;
        RECT 71.455 74.660 73.285 74.890 ;
        RECT 72.120 74.525 72.620 74.660 ;
        RECT 70.885 73.880 71.385 74.380 ;
        RECT 71.020 73.650 71.250 73.880 ;
        RECT 72.120 73.600 72.620 73.735 ;
        RECT 73.490 73.650 73.720 74.610 ;
        RECT 77.150 74.275 77.380 77.275 ;
        RECT 78.440 74.275 78.670 77.275 ;
        RECT 79.730 74.275 79.960 77.275 ;
        RECT 81.020 74.275 81.250 77.275 ;
        RECT 82.310 74.275 82.540 77.275 ;
        RECT 83.600 74.275 83.830 77.275 ;
        RECT 84.890 74.275 85.120 77.275 ;
        RECT 86.180 74.275 86.410 77.275 ;
        RECT 87.470 74.275 87.700 77.275 ;
        RECT 88.760 74.275 88.990 77.275 ;
        RECT 90.050 74.275 90.280 77.275 ;
        RECT 77.430 73.840 78.390 74.070 ;
        RECT 78.720 73.840 79.680 74.070 ;
        RECT 80.010 73.840 80.970 74.070 ;
        RECT 81.300 73.840 82.260 74.070 ;
        RECT 82.590 73.840 83.550 74.070 ;
        RECT 83.880 73.840 84.840 74.070 ;
        RECT 85.170 73.840 86.130 74.070 ;
        RECT 86.460 73.840 87.420 74.070 ;
        RECT 87.750 73.840 88.710 74.070 ;
        RECT 89.040 73.840 90.000 74.070 ;
        RECT 65.585 73.170 67.415 73.400 ;
        RECT 71.455 73.370 73.285 73.600 ;
        RECT 72.120 73.235 72.620 73.370 ;
        RECT 83.465 73.195 83.965 73.695 ;
        RECT 66.250 73.035 66.750 73.170 ;
        RECT 125.710 72.530 125.940 79.210 ;
        RECT 126.810 79.125 127.310 79.260 ;
        RECT 126.810 78.200 127.310 78.335 ;
        RECT 128.180 78.250 128.410 79.210 ;
        RECT 126.145 77.970 127.975 78.200 ;
        RECT 126.810 77.835 127.310 77.970 ;
        RECT 126.810 76.910 127.310 77.045 ;
        RECT 128.180 76.960 128.410 77.920 ;
        RECT 126.145 76.680 127.975 76.910 ;
        RECT 126.810 76.545 127.310 76.680 ;
        RECT 126.810 75.620 127.310 75.755 ;
        RECT 128.180 75.670 128.410 76.630 ;
        RECT 126.145 75.390 127.975 75.620 ;
        RECT 126.810 75.255 127.310 75.390 ;
        RECT 126.810 74.330 127.310 74.465 ;
        RECT 128.180 74.380 128.410 75.340 ;
        RECT 128.555 75.255 129.055 75.755 ;
        RECT 126.145 74.100 127.975 74.330 ;
        RECT 126.810 73.965 127.310 74.100 ;
        RECT 126.810 73.040 127.310 73.175 ;
        RECT 128.180 73.090 128.410 74.050 ;
        RECT 126.145 72.810 127.975 73.040 ;
        RECT 126.810 72.675 127.310 72.810 ;
        RECT 125.575 72.030 126.075 72.530 ;
        RECT 66.140 70.705 66.640 71.880 ;
        RECT 71.950 70.705 72.450 71.880 ;
        RECT 125.710 71.800 125.940 72.030 ;
        RECT 126.810 71.750 127.310 71.885 ;
        RECT 128.180 71.800 128.410 72.760 ;
        RECT 131.580 72.730 131.810 79.410 ;
        RECT 132.680 79.325 133.180 79.460 ;
        RECT 132.680 78.400 133.180 78.535 ;
        RECT 134.050 78.450 134.280 79.410 ;
        RECT 137.990 79.330 150.560 79.560 ;
        RECT 177.100 79.375 177.330 79.390 ;
        RECT 138.220 79.195 138.720 79.330 ;
        RECT 132.015 78.170 133.845 78.400 ;
        RECT 132.680 78.035 133.180 78.170 ;
        RECT 132.680 77.110 133.180 77.245 ;
        RECT 134.050 77.160 134.280 78.120 ;
        RECT 132.015 76.880 133.845 77.110 ;
        RECT 132.680 76.745 133.180 76.880 ;
        RECT 132.680 75.820 133.180 75.955 ;
        RECT 134.050 75.870 134.280 76.830 ;
        RECT 137.710 76.125 137.940 79.125 ;
        RECT 139.000 76.125 139.230 79.125 ;
        RECT 140.290 76.125 140.520 79.125 ;
        RECT 141.580 76.125 141.810 79.125 ;
        RECT 142.870 76.125 143.100 79.125 ;
        RECT 144.160 76.125 144.390 79.125 ;
        RECT 145.450 76.125 145.680 79.125 ;
        RECT 146.740 76.125 146.970 79.125 ;
        RECT 148.030 76.125 148.260 79.125 ;
        RECT 149.320 76.125 149.550 79.125 ;
        RECT 150.610 76.125 150.840 79.125 ;
        RECT 177.005 79.115 177.330 79.375 ;
        RECT 177.535 79.350 179.535 79.580 ;
        RECT 229.040 79.560 229.330 79.605 ;
        RECT 230.900 79.560 231.190 79.605 ;
        RECT 233.680 79.560 233.970 79.605 ;
        RECT 229.040 79.420 233.970 79.560 ;
        RECT 180.235 79.390 180.495 79.405 ;
        RECT 179.740 79.375 179.970 79.390 ;
        RECT 178.375 79.335 178.695 79.350 ;
        RECT 178.375 79.140 178.695 79.155 ;
        RECT 177.100 79.100 177.330 79.115 ;
        RECT 177.535 78.910 179.535 79.140 ;
        RECT 179.740 79.115 180.065 79.375 ;
        RECT 179.740 79.100 179.970 79.115 ;
        RECT 180.220 79.100 180.510 79.390 ;
        RECT 229.040 79.375 229.330 79.420 ;
        RECT 230.900 79.375 231.190 79.420 ;
        RECT 233.680 79.375 233.970 79.420 ;
        RECT 228.575 79.220 228.865 79.265 ;
        RECT 231.320 79.220 231.640 79.280 ;
        RECT 243.740 79.220 244.060 79.280 ;
        RECT 180.235 79.085 180.495 79.100 ;
        RECT 228.575 79.080 244.060 79.220 ;
        RECT 228.575 79.035 228.865 79.080 ;
        RECT 231.320 79.020 231.640 79.080 ;
        RECT 243.740 79.020 244.060 79.080 ;
        RECT 178.375 78.895 178.695 78.910 ;
        RECT 230.400 78.680 230.720 78.940 ;
        RECT 233.680 78.880 233.970 78.925 ;
        RECT 231.435 78.740 233.970 78.880 ;
        RECT 231.435 78.585 231.650 78.740 ;
        RECT 233.680 78.695 233.970 78.740 ;
        RECT 240.060 78.880 240.380 78.940 ;
        RECT 242.375 78.880 242.665 78.925 ;
        RECT 244.660 78.880 244.980 78.940 ;
        RECT 240.060 78.740 244.980 78.880 ;
        RECT 240.060 78.680 240.380 78.740 ;
        RECT 242.375 78.695 242.665 78.740 ;
        RECT 244.660 78.680 244.980 78.740 ;
        RECT 229.500 78.540 229.790 78.585 ;
        RECT 231.360 78.540 231.650 78.585 ;
        RECT 229.500 78.400 231.650 78.540 ;
        RECT 229.500 78.355 229.790 78.400 ;
        RECT 231.360 78.355 231.650 78.400 ;
        RECT 232.280 78.540 232.570 78.585 ;
        RECT 235.000 78.540 235.320 78.600 ;
        RECT 235.540 78.540 235.830 78.585 ;
        RECT 232.280 78.400 235.830 78.540 ;
        RECT 232.280 78.355 232.570 78.400 ;
        RECT 235.000 78.340 235.320 78.400 ;
        RECT 235.540 78.355 235.830 78.400 ;
        RECT 243.740 78.340 244.060 78.600 ;
        RECT 237.545 78.200 237.835 78.245 ;
        RECT 242.820 78.200 243.140 78.260 ;
        RECT 237.545 78.060 243.140 78.200 ;
        RECT 237.545 78.015 237.835 78.060 ;
        RECT 242.820 78.000 243.140 78.060 ;
        RECT 188.930 77.380 247.810 77.860 ;
        RECT 229.480 76.840 229.800 76.900 ;
        RECT 230.875 76.840 231.165 76.885 ;
        RECT 229.480 76.700 231.165 76.840 ;
        RECT 229.480 76.640 229.800 76.700 ;
        RECT 230.875 76.655 231.165 76.700 ;
        RECT 239.615 76.840 239.905 76.885 ;
        RECT 243.740 76.840 244.060 76.900 ;
        RECT 239.615 76.700 244.060 76.840 ;
        RECT 239.615 76.655 239.905 76.700 ;
        RECT 243.740 76.640 244.060 76.700 ;
        RECT 243.280 76.500 243.600 76.560 ;
        RECT 244.675 76.500 244.965 76.545 ;
        RECT 243.280 76.360 244.965 76.500 ;
        RECT 243.280 76.300 243.600 76.360 ;
        RECT 244.675 76.315 244.965 76.360 ;
        RECT 242.820 76.160 243.140 76.220 ;
        RECT 243.755 76.160 244.045 76.205 ;
        RECT 132.015 75.590 133.845 75.820 ;
        RECT 132.680 75.455 133.180 75.590 ;
        RECT 132.680 74.530 133.180 74.665 ;
        RECT 134.050 74.580 134.280 75.540 ;
        RECT 134.425 75.455 134.925 75.955 ;
        RECT 137.575 75.625 138.075 76.125 ;
        RECT 138.865 75.625 139.365 76.125 ;
        RECT 140.155 75.625 140.655 76.125 ;
        RECT 141.445 75.625 141.945 76.125 ;
        RECT 142.735 75.625 143.235 76.125 ;
        RECT 144.025 75.625 144.525 76.125 ;
        RECT 145.315 75.625 145.815 76.125 ;
        RECT 146.605 75.625 147.105 76.125 ;
        RECT 147.895 75.625 148.395 76.125 ;
        RECT 149.185 75.625 149.685 76.125 ;
        RECT 150.475 75.625 150.975 76.125 ;
        RECT 242.820 76.020 244.045 76.160 ;
        RECT 242.820 75.960 243.140 76.020 ;
        RECT 243.755 75.975 244.045 76.020 ;
        RECT 178.300 75.910 178.620 75.925 ;
        RECT 177.570 75.705 177.800 75.720 ;
        RECT 132.015 74.300 133.845 74.530 ;
        RECT 132.680 74.165 133.180 74.300 ;
        RECT 132.680 73.240 133.180 73.375 ;
        RECT 134.050 73.290 134.280 74.250 ;
        RECT 132.015 73.010 133.845 73.240 ;
        RECT 132.680 72.875 133.180 73.010 ;
        RECT 131.445 72.230 131.945 72.730 ;
        RECT 131.580 72.000 131.810 72.230 ;
        RECT 132.680 71.950 133.180 72.085 ;
        RECT 134.050 72.000 134.280 72.960 ;
        RECT 137.710 72.625 137.940 75.625 ;
        RECT 139.000 72.625 139.230 75.625 ;
        RECT 140.290 72.625 140.520 75.625 ;
        RECT 141.580 72.625 141.810 75.625 ;
        RECT 142.870 72.625 143.100 75.625 ;
        RECT 144.160 72.625 144.390 75.625 ;
        RECT 145.450 72.625 145.680 75.625 ;
        RECT 146.740 72.625 146.970 75.625 ;
        RECT 148.030 72.625 148.260 75.625 ;
        RECT 149.320 72.625 149.550 75.625 ;
        RECT 150.610 72.625 150.840 75.625 ;
        RECT 177.475 75.445 177.800 75.705 ;
        RECT 177.960 75.680 178.960 75.910 ;
        RECT 179.615 75.720 179.875 75.735 ;
        RECT 179.120 75.705 179.350 75.720 ;
        RECT 178.300 75.665 178.620 75.680 ;
        RECT 178.300 75.470 178.620 75.485 ;
        RECT 177.570 75.430 177.800 75.445 ;
        RECT 177.960 75.240 178.960 75.470 ;
        RECT 179.120 75.445 179.445 75.705 ;
        RECT 179.120 75.430 179.350 75.445 ;
        RECT 179.600 75.430 179.890 75.720 ;
        RECT 245.580 75.620 245.900 75.880 ;
        RECT 232.700 75.480 233.020 75.540 ;
        RECT 240.995 75.480 241.285 75.525 ;
        RECT 179.615 75.415 179.875 75.430 ;
        RECT 232.700 75.340 241.285 75.480 ;
        RECT 232.700 75.280 233.020 75.340 ;
        RECT 240.995 75.295 241.285 75.340 ;
        RECT 178.300 75.225 178.620 75.240 ;
        RECT 188.930 74.660 247.810 75.140 ;
        RECT 240.060 74.260 240.380 74.520 ;
        RECT 232.205 74.120 232.495 74.165 ;
        RECT 234.095 74.120 234.385 74.165 ;
        RECT 237.215 74.120 237.505 74.165 ;
        RECT 232.205 73.980 237.505 74.120 ;
        RECT 232.205 73.935 232.495 73.980 ;
        RECT 234.095 73.935 234.385 73.980 ;
        RECT 237.215 73.935 237.505 73.980 ;
        RECT 231.320 73.580 231.640 73.840 ;
        RECT 232.715 73.780 233.005 73.825 ;
        RECT 240.535 73.780 240.825 73.825 ;
        RECT 232.715 73.640 240.825 73.780 ;
        RECT 232.715 73.595 233.005 73.640 ;
        RECT 240.535 73.595 240.825 73.640 ;
        RECT 231.800 73.440 232.090 73.485 ;
        RECT 233.635 73.440 233.925 73.485 ;
        RECT 237.215 73.440 237.505 73.485 ;
        RECT 231.800 73.300 237.505 73.440 ;
        RECT 231.800 73.255 232.090 73.300 ;
        RECT 233.635 73.255 233.925 73.300 ;
        RECT 237.215 73.255 237.505 73.300 ;
        RECT 235.000 73.145 235.320 73.160 ;
        RECT 238.295 73.145 238.585 73.460 ;
        RECT 243.280 73.240 243.600 73.500 ;
        RECT 234.995 73.100 235.645 73.145 ;
        RECT 238.295 73.100 238.885 73.145 ;
        RECT 234.995 72.960 238.885 73.100 ;
        RECT 234.995 72.915 235.645 72.960 ;
        RECT 238.595 72.915 238.885 72.960 ;
        RECT 235.000 72.900 235.320 72.915 ;
        RECT 137.990 72.190 138.950 72.420 ;
        RECT 139.280 72.190 140.240 72.420 ;
        RECT 140.570 72.190 141.530 72.420 ;
        RECT 141.860 72.190 142.820 72.420 ;
        RECT 143.150 72.190 144.110 72.420 ;
        RECT 144.440 72.190 145.400 72.420 ;
        RECT 145.730 72.190 146.690 72.420 ;
        RECT 147.020 72.190 147.980 72.420 ;
        RECT 148.310 72.190 149.270 72.420 ;
        RECT 149.600 72.190 150.560 72.420 ;
        RECT 126.145 71.520 127.975 71.750 ;
        RECT 132.015 71.720 133.845 71.950 ;
        RECT 132.680 71.585 133.180 71.720 ;
        RECT 144.025 71.545 144.525 72.045 ;
        RECT 188.930 71.940 247.810 72.420 ;
        RECT 240.075 71.740 240.365 71.785 ;
        RECT 243.280 71.740 243.600 71.800 ;
        RECT 240.075 71.600 243.600 71.740 ;
        RECT 240.075 71.555 240.365 71.600 ;
        RECT 243.280 71.540 243.600 71.600 ;
        RECT 126.810 71.385 127.310 71.520 ;
        RECT 232.700 71.200 233.020 71.460 ;
        RECT 235.000 71.445 235.320 71.460 ;
        RECT 234.995 71.400 235.645 71.445 ;
        RECT 238.595 71.400 238.885 71.445 ;
        RECT 234.995 71.260 238.885 71.400 ;
        RECT 234.995 71.215 235.645 71.260 ;
        RECT 238.295 71.215 238.885 71.260 ;
        RECT 235.000 71.200 235.320 71.215 ;
        RECT 66.160 70.520 66.620 70.705 ;
        RECT 71.970 70.520 72.430 70.705 ;
        RECT 62.290 69.440 63.290 70.440 ;
        RECT 65.880 70.110 66.110 70.360 ;
        RECT 66.670 70.110 66.900 70.360 ;
        RECT 71.690 70.110 71.920 70.360 ;
        RECT 72.480 70.110 72.710 70.360 ;
        RECT 65.745 69.610 66.245 70.110 ;
        RECT 66.535 69.610 67.035 70.110 ;
        RECT 71.555 69.610 72.055 70.110 ;
        RECT 72.345 69.610 72.845 70.110 ;
        RECT 75.230 69.640 76.230 70.640 ;
        RECT 81.655 70.595 82.155 71.095 ;
        RECT 82.395 70.970 82.895 71.095 ;
        RECT 87.375 70.970 87.875 71.095 ;
        RECT 82.395 70.720 84.605 70.970 ;
        RECT 85.665 70.720 87.875 70.970 ;
        RECT 231.320 70.860 231.640 71.120 ;
        RECT 231.800 71.060 232.090 71.105 ;
        RECT 233.635 71.060 233.925 71.105 ;
        RECT 237.215 71.060 237.505 71.105 ;
        RECT 231.800 70.920 237.505 71.060 ;
        RECT 231.800 70.875 232.090 70.920 ;
        RECT 233.635 70.875 233.925 70.920 ;
        RECT 237.215 70.875 237.505 70.920 ;
        RECT 238.295 70.900 238.585 71.215 ;
        RECT 242.820 71.060 243.140 71.120 ;
        RECT 244.675 71.060 244.965 71.105 ;
        RECT 242.820 70.920 244.965 71.060 ;
        RECT 242.820 70.860 243.140 70.920 ;
        RECT 244.675 70.875 244.965 70.920 ;
        RECT 82.395 70.595 82.895 70.720 ;
        RECT 87.375 70.595 87.875 70.720 ;
        RECT 232.205 70.380 232.495 70.425 ;
        RECT 234.095 70.380 234.385 70.425 ;
        RECT 237.215 70.380 237.505 70.425 ;
        RECT 232.205 70.240 237.505 70.380 ;
        RECT 65.880 69.360 66.110 69.610 ;
        RECT 66.670 69.360 66.900 69.610 ;
        RECT 71.690 69.360 71.920 69.610 ;
        RECT 72.480 69.360 72.710 69.610 ;
        RECT 66.160 68.970 66.620 69.200 ;
        RECT 71.970 68.970 72.430 69.200 ;
        RECT 126.700 69.055 127.200 70.230 ;
        RECT 132.510 69.055 133.010 70.230 ;
        RECT 232.205 70.195 232.495 70.240 ;
        RECT 234.095 70.195 234.385 70.240 ;
        RECT 237.215 70.195 237.505 70.240 ;
        RECT 245.580 69.840 245.900 70.100 ;
        RECT 126.720 68.870 127.180 69.055 ;
        RECT 132.530 68.870 132.990 69.055 ;
        RECT 66.190 68.750 66.590 68.775 ;
        RECT 63.460 68.575 66.590 68.750 ;
        RECT 63.285 68.400 66.590 68.575 ;
        RECT 63.285 68.130 63.635 68.400 ;
        RECT 66.190 68.375 66.590 68.400 ;
        RECT 72.000 68.750 72.400 68.775 ;
        RECT 72.000 68.575 74.460 68.750 ;
        RECT 72.000 68.400 74.635 68.575 ;
        RECT 72.000 68.375 72.400 68.400 ;
        RECT 74.285 68.130 74.635 68.400 ;
        RECT 63.210 67.630 63.710 68.130 ;
        RECT 74.210 67.630 74.710 68.130 ;
        RECT 122.850 67.790 123.850 68.790 ;
        RECT 126.440 68.460 126.670 68.710 ;
        RECT 127.230 68.460 127.460 68.710 ;
        RECT 132.250 68.460 132.480 68.710 ;
        RECT 133.040 68.460 133.270 68.710 ;
        RECT 126.305 67.960 126.805 68.460 ;
        RECT 127.095 67.960 127.595 68.460 ;
        RECT 132.115 67.960 132.615 68.460 ;
        RECT 132.905 67.960 133.405 68.460 ;
        RECT 135.790 67.990 136.790 68.990 ;
        RECT 142.215 68.945 142.715 69.445 ;
        RECT 142.955 69.320 143.455 69.445 ;
        RECT 147.935 69.320 148.435 69.445 ;
        RECT 142.955 69.070 145.165 69.320 ;
        RECT 146.225 69.070 148.435 69.320 ;
        RECT 188.930 69.220 247.810 69.700 ;
        RECT 142.955 68.945 143.455 69.070 ;
        RECT 147.935 68.945 148.435 69.070 ;
        RECT 239.140 68.000 239.460 68.060 ;
        RECT 244.675 68.000 244.965 68.045 ;
        RECT 126.440 67.710 126.670 67.960 ;
        RECT 127.230 67.710 127.460 67.960 ;
        RECT 132.250 67.710 132.480 67.960 ;
        RECT 133.040 67.710 133.270 67.960 ;
        RECT 239.140 67.860 244.965 68.000 ;
        RECT 239.140 67.800 239.460 67.860 ;
        RECT 244.675 67.815 244.965 67.860 ;
        RECT 80.125 67.570 80.625 67.705 ;
        RECT 78.750 67.340 82.000 67.570 ;
        RECT 78.360 66.950 78.590 67.290 ;
        RECT 80.125 67.205 80.625 67.340 ;
        RECT 72.765 66.350 73.265 66.485 ;
        RECT 66.190 66.140 66.690 66.275 ;
        RECT 65.960 65.910 66.920 66.140 ;
        RECT 71.080 66.120 74.950 66.350 ;
        RECT 66.190 65.775 66.690 65.910 ;
        RECT 70.690 65.840 70.920 66.070 ;
        RECT 72.765 65.985 73.265 66.120 ;
        RECT 65.680 65.675 65.910 65.750 ;
        RECT 66.970 65.675 67.200 65.750 ;
        RECT 65.545 65.175 66.045 65.675 ;
        RECT 66.835 65.175 67.335 65.675 ;
        RECT 70.555 65.340 71.055 65.840 ;
        RECT 65.680 65.100 65.910 65.175 ;
        RECT 66.970 65.100 67.200 65.175 ;
        RECT 70.690 65.110 70.920 65.340 ;
        RECT 72.765 65.060 73.265 65.195 ;
        RECT 75.110 65.110 75.340 66.070 ;
        RECT 75.485 65.340 75.985 65.840 ;
        RECT 78.355 65.770 78.595 66.950 ;
        RECT 80.125 66.280 80.625 66.415 ;
        RECT 82.160 66.330 82.390 67.290 ;
        RECT 78.750 66.050 82.000 66.280 ;
        RECT 80.125 65.915 80.625 66.050 ;
        RECT 78.225 65.270 78.725 65.770 ;
        RECT 65.960 64.710 66.920 64.940 ;
        RECT 71.080 64.830 74.950 65.060 ;
        RECT 78.360 65.040 78.590 65.270 ;
        RECT 80.125 64.990 80.625 65.125 ;
        RECT 82.160 65.040 82.390 66.000 ;
        RECT 82.535 65.915 83.035 66.415 ;
        RECT 89.110 66.380 90.110 67.380 ;
        RECT 126.720 67.320 127.180 67.550 ;
        RECT 132.530 67.320 132.990 67.550 ;
        RECT 126.750 67.100 127.150 67.125 ;
        RECT 124.020 66.925 127.150 67.100 ;
        RECT 123.845 66.750 127.150 66.925 ;
        RECT 123.845 66.480 124.195 66.750 ;
        RECT 126.750 66.725 127.150 66.750 ;
        RECT 132.560 67.100 132.960 67.125 ;
        RECT 245.580 67.120 245.900 67.380 ;
        RECT 132.560 66.925 135.020 67.100 ;
        RECT 132.560 66.750 135.195 66.925 ;
        RECT 132.560 66.725 132.960 66.750 ;
        RECT 134.845 66.480 135.195 66.750 ;
        RECT 188.930 66.500 247.810 66.980 ;
        RECT 123.770 65.980 124.270 66.480 ;
        RECT 134.770 65.980 135.270 66.480 ;
        RECT 140.685 65.920 141.185 66.055 ;
        RECT 139.310 65.690 142.560 65.920 ;
        RECT 138.920 65.300 139.150 65.640 ;
        RECT 140.685 65.555 141.185 65.690 ;
        RECT 72.765 64.695 73.265 64.830 ;
        RECT 78.750 64.760 82.000 64.990 ;
        RECT 80.125 64.625 80.625 64.760 ;
        RECT 133.325 64.700 133.825 64.835 ;
        RECT 66.190 64.065 66.690 64.565 ;
        RECT 126.750 64.490 127.250 64.625 ;
        RECT 126.520 64.260 127.480 64.490 ;
        RECT 131.640 64.470 135.510 64.700 ;
        RECT 126.750 64.125 127.250 64.260 ;
        RECT 131.250 64.190 131.480 64.420 ;
        RECT 133.325 64.335 133.825 64.470 ;
        RECT 126.240 64.025 126.470 64.100 ;
        RECT 127.530 64.025 127.760 64.100 ;
        RECT 126.105 63.525 126.605 64.025 ;
        RECT 127.395 63.525 127.895 64.025 ;
        RECT 131.115 63.690 131.615 64.190 ;
        RECT 126.240 63.450 126.470 63.525 ;
        RECT 127.530 63.450 127.760 63.525 ;
        RECT 131.250 63.460 131.480 63.690 ;
        RECT 133.325 63.410 133.825 63.545 ;
        RECT 135.670 63.460 135.900 64.420 ;
        RECT 136.045 63.690 136.545 64.190 ;
        RECT 138.915 64.120 139.155 65.300 ;
        RECT 140.685 64.630 141.185 64.765 ;
        RECT 142.720 64.680 142.950 65.640 ;
        RECT 139.310 64.400 142.560 64.630 ;
        RECT 140.685 64.265 141.185 64.400 ;
        RECT 138.785 63.620 139.285 64.120 ;
        RECT 126.520 63.060 127.480 63.290 ;
        RECT 131.640 63.180 135.510 63.410 ;
        RECT 138.920 63.390 139.150 63.620 ;
        RECT 140.685 63.340 141.185 63.475 ;
        RECT 142.720 63.390 142.950 64.350 ;
        RECT 143.095 64.265 143.595 64.765 ;
        RECT 149.670 64.730 150.670 65.730 ;
        RECT 133.325 63.045 133.825 63.180 ;
        RECT 139.310 63.110 142.560 63.340 ;
        RECT 140.685 62.975 141.185 63.110 ;
        RECT 126.750 62.415 127.250 62.915 ;
        RECT 80.700 60.310 81.700 61.310 ;
        RECT 141.260 58.660 142.260 59.660 ;
      LAYER met2 ;
        RECT 103.390 131.835 103.650 131.865 ;
        RECT 103.370 131.545 103.650 131.835 ;
        RECT 66.470 131.095 66.730 131.130 ;
        RECT 66.455 130.835 66.775 131.095 ;
        RECT 66.470 129.330 66.730 130.835 ;
        RECT 65.670 129.070 66.730 129.330 ;
        RECT 52.850 128.930 53.350 129.050 ;
        RECT 53.840 128.930 54.160 128.935 ;
        RECT 52.850 128.675 54.160 128.930 ;
        RECT 56.590 128.930 56.910 128.935 ;
        RECT 56.590 128.675 56.930 128.930 ;
        RECT 52.850 128.670 54.130 128.675 ;
        RECT 52.850 128.550 53.350 128.670 ;
        RECT 56.670 127.230 56.930 128.675 ;
        RECT 65.670 128.130 65.930 129.070 ;
        RECT 103.370 128.930 103.630 131.545 ;
        RECT 140.270 131.095 140.530 131.130 ;
        RECT 140.265 130.835 140.585 131.095 ;
        RECT 103.170 128.915 103.630 128.930 ;
        RECT 66.150 128.350 66.650 128.850 ;
        RECT 103.150 128.670 103.630 128.915 ;
        RECT 140.270 128.850 140.530 130.835 ;
        RECT 169.830 129.730 170.090 129.745 ;
        RECT 169.830 129.425 170.130 129.730 ;
        RECT 145.995 128.930 146.330 128.975 ;
        RECT 103.150 128.595 103.430 128.670 ;
        RECT 66.270 128.145 66.530 128.350 ;
        RECT 65.570 127.870 65.930 128.130 ;
        RECT 66.215 127.885 66.535 128.145 ;
        RECT 66.270 127.870 66.530 127.885 ;
        RECT 56.670 127.130 57.730 127.230 ;
        RECT 64.850 127.130 65.350 127.250 ;
        RECT 56.670 126.970 65.350 127.130 ;
        RECT 57.570 126.870 65.350 126.970 ;
        RECT 64.850 126.750 65.350 126.870 ;
        RECT 65.570 124.730 65.830 127.870 ;
        RECT 66.050 127.150 66.550 127.650 ;
        RECT 65.370 124.470 65.830 124.730 ;
        RECT 66.170 124.725 66.430 127.150 ;
        RECT 103.170 126.650 103.430 128.595 ;
        RECT 140.150 128.350 140.650 128.850 ;
        RECT 145.470 128.670 146.330 128.930 ;
        RECT 140.025 127.885 140.345 128.145 ;
        RECT 140.070 127.650 140.330 127.885 ;
        RECT 139.950 127.150 140.450 127.650 ;
        RECT 102.950 126.150 103.450 126.650 ;
        RECT 103.170 125.495 103.430 126.150 ;
        RECT 103.030 125.175 103.430 125.495 ;
        RECT 65.370 109.030 65.630 124.470 ;
        RECT 66.095 124.465 66.430 124.725 ;
        RECT 103.070 125.170 103.430 125.175 ;
        RECT 65.850 123.750 66.350 124.250 ;
        RECT 65.970 121.535 66.230 123.750 ;
        RECT 103.070 122.305 103.330 125.170 ;
        RECT 139.970 124.725 140.230 124.730 ;
        RECT 139.905 124.465 140.230 124.725 ;
        RECT 139.970 124.250 140.230 124.465 ;
        RECT 139.850 123.750 140.350 124.250 ;
        RECT 102.920 122.275 103.330 122.305 ;
        RECT 102.870 121.970 103.330 122.275 ;
        RECT 145.470 122.130 145.730 128.670 ;
        RECT 145.950 127.950 146.450 128.450 ;
        RECT 146.070 125.785 146.330 127.950 ;
        RECT 169.870 126.555 170.130 129.425 ;
        RECT 193.605 128.715 193.930 128.975 ;
        RECT 193.670 128.450 193.930 128.715 ;
        RECT 193.550 127.950 194.050 128.450 ;
        RECT 169.830 126.235 170.130 126.555 ;
        RECT 145.995 125.525 146.330 125.785 ;
        RECT 169.870 122.430 170.130 126.235 ;
        RECT 193.670 125.785 193.930 125.830 ;
        RECT 193.605 125.525 193.930 125.785 ;
        RECT 65.970 121.275 66.305 121.535 ;
        RECT 65.970 121.270 66.230 121.275 ;
        RECT 66.150 120.550 66.650 121.050 ;
        RECT 66.270 118.565 66.530 120.550 ;
        RECT 102.870 119.750 103.130 121.970 ;
        RECT 144.970 121.870 145.730 122.130 ;
        RECT 139.795 121.275 140.130 121.535 ;
        RECT 139.870 121.050 140.130 121.275 ;
        RECT 139.750 120.550 140.250 121.050 ;
        RECT 102.850 119.610 103.290 119.750 ;
        RECT 102.850 119.450 103.430 119.610 ;
        RECT 102.850 119.170 103.650 119.450 ;
        RECT 102.870 119.070 103.650 119.170 ;
        RECT 103.150 118.950 103.650 119.070 ;
        RECT 66.270 118.305 66.605 118.565 ;
        RECT 66.270 118.270 66.530 118.305 ;
        RECT 80.830 113.160 81.330 113.660 ;
        RECT 71.730 109.955 72.230 110.005 ;
        RECT 65.860 109.755 66.360 109.805 ;
        RECT 71.730 109.755 72.640 109.955 ;
        RECT 65.860 109.555 66.770 109.755 ;
        RECT 71.730 109.555 72.840 109.755 ;
        RECT 65.860 109.355 66.970 109.555 ;
        RECT 71.730 109.505 72.230 109.555 ;
        RECT 65.860 109.305 66.360 109.355 ;
        RECT 61.750 108.300 62.250 108.800 ;
        RECT 64.770 108.770 65.630 109.030 ;
        RECT 54.610 105.130 54.870 105.160 ;
        RECT 55.880 105.130 56.140 105.160 ;
        RECT 54.570 104.870 56.140 105.130 ;
        RECT 54.610 104.840 54.870 104.870 ;
        RECT 55.870 104.840 56.140 104.870 ;
        RECT 55.870 96.830 56.130 104.840 ;
        RECT 59.650 103.330 60.150 103.350 ;
        RECT 56.970 103.070 60.150 103.330 ;
        RECT 64.770 103.230 65.030 108.770 ;
        RECT 65.200 108.465 65.700 108.515 ;
        RECT 65.860 108.465 66.360 108.515 ;
        RECT 65.200 108.065 66.360 108.465 ;
        RECT 65.200 108.015 65.700 108.065 ;
        RECT 65.860 108.015 66.360 108.065 ;
        RECT 59.650 102.850 60.150 103.070 ;
        RECT 64.170 102.970 65.030 103.230 ;
        RECT 65.250 105.885 65.650 108.015 ;
        RECT 65.860 107.175 66.360 107.225 ;
        RECT 66.570 107.175 66.970 109.355 ;
        RECT 72.440 108.860 72.840 109.555 ;
        RECT 77.270 109.375 77.770 109.875 ;
        RECT 77.320 108.860 77.720 109.375 ;
        RECT 79.320 108.860 79.820 108.910 ;
        RECT 71.070 108.665 71.570 108.715 ;
        RECT 71.730 108.665 72.230 108.715 ;
        RECT 71.070 108.265 72.230 108.665 ;
        RECT 71.070 108.215 71.570 108.265 ;
        RECT 71.730 108.215 72.230 108.265 ;
        RECT 72.440 108.460 79.820 108.860 ;
        RECT 65.860 106.775 66.970 107.175 ;
        RECT 65.860 106.725 66.360 106.775 ;
        RECT 65.860 105.885 66.360 105.935 ;
        RECT 65.250 105.485 66.360 105.885 ;
        RECT 65.250 103.305 65.650 105.485 ;
        RECT 65.860 105.435 66.360 105.485 ;
        RECT 65.860 104.595 66.360 104.645 ;
        RECT 66.570 104.595 66.970 106.775 ;
        RECT 71.120 106.085 71.520 108.215 ;
        RECT 71.730 107.375 72.230 107.425 ;
        RECT 72.440 107.375 72.840 108.460 ;
        RECT 79.320 108.410 79.820 108.460 ;
        RECT 71.730 106.975 72.840 107.375 ;
        RECT 71.730 106.925 72.230 106.975 ;
        RECT 71.730 106.085 72.230 106.135 ;
        RECT 67.605 105.435 68.105 105.935 ;
        RECT 71.120 105.685 72.230 106.085 ;
        RECT 65.860 104.195 66.970 104.595 ;
        RECT 65.860 104.145 66.360 104.195 ;
        RECT 65.860 103.305 66.360 103.355 ;
        RECT 65.250 103.105 66.360 103.305 ;
        RECT 64.170 99.930 64.430 102.970 ;
        RECT 65.450 102.905 66.360 103.105 ;
        RECT 65.860 102.855 66.360 102.905 ;
        RECT 64.625 102.660 65.125 102.710 ;
        RECT 66.570 102.660 66.970 104.195 ;
        RECT 71.120 103.505 71.520 105.685 ;
        RECT 71.730 105.635 72.230 105.685 ;
        RECT 71.730 104.795 72.230 104.845 ;
        RECT 72.440 104.795 72.840 106.975 ;
        RECT 76.625 106.855 77.125 106.905 ;
        RECT 76.625 106.455 89.975 106.855 ;
        RECT 73.475 105.635 73.975 106.135 ;
        RECT 76.625 105.805 77.125 106.455 ;
        RECT 79.255 106.305 79.655 106.455 ;
        RECT 81.835 106.305 82.235 106.455 ;
        RECT 84.415 106.305 84.815 106.455 ;
        RECT 86.995 106.305 87.395 106.455 ;
        RECT 89.575 106.305 89.975 106.455 ;
        RECT 77.915 105.805 78.415 106.305 ;
        RECT 79.205 105.805 79.705 106.305 ;
        RECT 80.495 106.250 80.995 106.305 ;
        RECT 80.495 105.955 81.150 106.250 ;
        RECT 80.495 105.815 81.310 105.955 ;
        RECT 80.495 105.805 81.450 105.815 ;
        RECT 81.785 105.805 82.285 106.305 ;
        RECT 83.075 105.805 83.575 106.305 ;
        RECT 84.365 105.805 84.865 106.305 ;
        RECT 85.655 105.805 86.155 106.305 ;
        RECT 86.945 105.805 87.445 106.305 ;
        RECT 77.965 105.655 78.365 105.805 ;
        RECT 80.545 105.655 81.450 105.805 ;
        RECT 83.125 105.655 83.525 105.805 ;
        RECT 85.705 105.655 86.105 105.805 ;
        RECT 88.235 105.655 88.735 106.305 ;
        RECT 89.525 105.805 90.025 106.305 ;
        RECT 77.965 105.255 88.735 105.655 ;
        RECT 71.730 104.395 72.840 104.795 ;
        RECT 71.730 104.345 72.230 104.395 ;
        RECT 71.730 103.505 72.230 103.555 ;
        RECT 71.120 103.305 72.230 103.505 ;
        RECT 71.320 103.105 72.230 103.305 ;
        RECT 71.730 103.055 72.230 103.105 ;
        RECT 64.625 102.260 66.970 102.660 ;
        RECT 70.495 102.410 70.995 102.910 ;
        RECT 64.625 102.210 65.125 102.260 ;
        RECT 65.860 102.015 66.360 102.065 ;
        RECT 66.570 102.015 66.970 102.260 ;
        RECT 65.860 101.615 66.970 102.015 ;
        RECT 65.860 101.565 66.360 101.615 ;
        RECT 66.570 100.710 66.970 101.615 ;
        RECT 70.545 100.710 70.945 102.410 ;
        RECT 71.730 102.215 72.230 102.265 ;
        RECT 72.440 102.215 72.840 104.395 ;
        RECT 71.730 102.015 72.840 102.215 ;
        RECT 71.730 101.815 72.640 102.015 ;
        RECT 71.730 101.765 72.230 101.815 ;
        RECT 66.570 100.510 71.415 100.710 ;
        RECT 63.370 99.670 64.430 99.930 ;
        RECT 65.750 99.910 66.250 100.410 ;
        RECT 66.770 100.310 71.415 100.510 ;
        RECT 62.150 98.630 62.650 98.720 ;
        RECT 63.370 98.630 63.630 99.670 ;
        RECT 63.820 99.365 64.320 99.415 ;
        RECT 65.800 99.365 66.200 99.910 ;
        RECT 63.820 99.165 66.200 99.365 ;
        RECT 63.820 98.965 66.000 99.165 ;
        RECT 63.820 98.915 64.320 98.965 ;
        RECT 62.150 98.370 63.630 98.630 ;
        RECT 62.150 98.220 62.650 98.370 ;
        RECT 62.270 97.950 62.530 98.220 ;
        RECT 65.355 98.140 65.855 98.640 ;
        RECT 66.145 98.140 66.645 98.640 ;
        RECT 69.370 98.590 69.770 100.310 ;
        RECT 71.560 99.910 72.060 100.410 ;
        RECT 71.165 98.590 71.665 98.640 ;
        RECT 69.370 98.390 71.665 98.590 ;
        RECT 69.570 98.190 71.665 98.390 ;
        RECT 71.165 98.140 71.665 98.190 ;
        RECT 71.955 98.140 72.455 98.640 ;
        RECT 75.090 98.630 75.590 98.920 ;
        RECT 75.090 98.430 75.630 98.630 ;
        RECT 77.650 98.430 78.150 98.550 ;
        RECT 75.090 98.420 78.150 98.430 ;
        RECT 75.370 98.170 78.150 98.420 ;
        RECT 62.150 97.450 62.650 97.950 ;
        RECT 55.870 96.730 62.930 96.830 ;
        RECT 55.870 96.660 63.030 96.730 ;
        RECT 55.870 96.570 63.320 96.660 ;
        RECT 62.670 96.470 63.320 96.570 ;
        RECT 62.820 96.160 63.320 96.470 ;
        RECT 66.195 96.360 66.595 98.140 ;
        RECT 72.005 96.360 72.405 98.140 ;
        RECT 77.650 98.050 78.150 98.170 ;
        RECT 66.195 96.160 72.405 96.360 ;
        RECT 73.820 96.160 74.320 96.660 ;
        RECT 66.395 95.960 72.205 96.160 ;
        RECT 65.800 94.755 66.300 94.805 ;
        RECT 65.405 94.555 66.300 94.755 ;
        RECT 65.205 94.355 66.300 94.555 ;
        RECT 65.205 94.205 65.605 94.355 ;
        RECT 65.800 94.305 66.300 94.355 ;
        RECT 70.165 94.320 70.665 94.370 ;
        RECT 65.155 94.155 65.655 94.205 ;
        RECT 64.570 93.955 65.655 94.155 ;
        RECT 64.370 93.755 65.655 93.955 ;
        RECT 61.320 91.360 61.820 91.410 ;
        RECT 64.370 91.360 64.770 93.755 ;
        RECT 65.155 93.705 65.655 93.755 ;
        RECT 66.445 93.705 66.945 94.205 ;
        RECT 69.570 94.120 70.665 94.320 ;
        RECT 69.370 93.920 70.665 94.120 ;
        RECT 65.800 92.595 66.300 93.095 ;
        RECT 69.370 91.360 69.770 93.920 ;
        RECT 70.165 93.870 70.665 93.920 ;
        RECT 71.370 93.675 71.770 95.960 ;
        RECT 79.735 95.735 80.235 96.235 ;
        RECT 72.375 94.515 72.875 95.015 ;
        RECT 79.735 94.445 80.235 94.945 ;
        RECT 75.095 93.870 75.595 94.370 ;
        RECT 77.835 94.250 78.335 94.300 ;
        RECT 76.070 94.050 78.335 94.250 ;
        RECT 75.870 93.850 78.335 94.050 ;
        RECT 72.375 93.675 72.875 93.725 ;
        RECT 71.370 93.475 72.875 93.675 ;
        RECT 71.570 93.275 72.875 93.475 ;
        RECT 72.375 93.225 72.875 93.275 ;
        RECT 75.870 91.360 76.270 93.850 ;
        RECT 77.835 93.800 78.335 93.850 ;
        RECT 76.820 93.605 77.320 93.655 ;
        RECT 79.735 93.605 80.235 93.655 ;
        RECT 76.820 93.205 80.235 93.605 ;
        RECT 76.820 93.155 77.320 93.205 ;
        RECT 79.735 93.155 80.235 93.205 ;
        RECT 61.320 90.960 78.085 91.360 ;
        RECT 61.320 90.910 61.820 90.960 ;
        RECT 63.850 90.630 64.350 90.750 ;
        RECT 63.670 90.250 64.350 90.630 ;
        RECT 63.670 81.330 63.930 90.250 ;
        RECT 80.770 90.230 81.030 105.255 ;
        RECT 88.235 105.205 88.735 105.255 ;
        RECT 83.075 101.725 83.575 102.225 ;
        RECT 88.350 100.530 88.850 100.650 ;
        RECT 103.270 100.530 103.530 118.950 ;
        RECT 140.095 118.530 140.430 118.565 ;
        RECT 144.970 118.530 145.230 121.870 ;
        RECT 146.050 121.850 146.550 122.350 ;
        RECT 169.870 122.170 170.230 122.430 ;
        RECT 193.670 122.350 193.930 125.525 ;
        RECT 169.950 122.105 170.230 122.170 ;
        RECT 146.170 121.655 146.430 121.850 ;
        RECT 146.115 121.630 146.435 121.655 ;
        RECT 140.095 118.305 145.230 118.530 ;
        RECT 140.170 118.270 145.230 118.305 ;
        RECT 145.470 121.395 146.435 121.630 ;
        RECT 145.470 121.370 146.430 121.395 ;
        RECT 140.170 110.750 140.430 118.270 ;
        RECT 141.970 112.680 142.470 113.180 ;
        RECT 140.050 110.250 140.550 110.750 ;
        RECT 145.470 110.030 145.730 121.370 ;
        RECT 145.950 120.650 146.450 121.150 ;
        RECT 146.070 118.585 146.330 120.650 ;
        RECT 169.970 119.355 170.230 122.105 ;
        RECT 193.550 121.850 194.050 122.350 ;
        RECT 193.725 121.395 194.045 121.655 ;
        RECT 193.770 121.150 194.030 121.395 ;
        RECT 193.650 120.650 194.150 121.150 ;
        RECT 169.830 119.070 170.230 119.355 ;
        RECT 169.830 119.035 170.130 119.070 ;
        RECT 145.995 118.325 146.330 118.585 ;
        RECT 132.370 109.830 145.730 110.030 ;
        RECT 126.570 109.770 145.730 109.830 ;
        RECT 126.570 109.570 132.630 109.770 ;
        RECT 126.570 108.530 126.830 109.570 ;
        RECT 132.870 109.475 133.370 109.525 ;
        RECT 127.000 109.275 127.500 109.325 ;
        RECT 132.870 109.275 133.780 109.475 ;
        RECT 127.000 109.075 127.910 109.275 ;
        RECT 132.870 109.075 133.980 109.275 ;
        RECT 127.000 108.875 128.110 109.075 ;
        RECT 132.870 109.025 133.370 109.075 ;
        RECT 127.000 108.825 127.500 108.875 ;
        RECT 122.890 107.820 123.390 108.320 ;
        RECT 125.870 108.270 126.830 108.530 ;
        RECT 125.870 102.730 126.130 108.270 ;
        RECT 126.340 107.985 126.840 108.035 ;
        RECT 127.000 107.985 127.500 108.035 ;
        RECT 126.340 107.585 127.500 107.985 ;
        RECT 126.340 107.535 126.840 107.585 ;
        RECT 127.000 107.535 127.500 107.585 ;
        RECT 88.350 100.270 103.530 100.530 ;
        RECT 88.350 100.150 88.850 100.270 ;
        RECT 81.265 99.125 81.765 99.625 ;
        RECT 82.005 99.125 82.505 99.625 ;
        RECT 86.985 99.125 87.485 99.625 ;
        RECT 81.315 90.910 81.715 99.125 ;
        RECT 82.055 97.860 82.455 99.125 ;
        RECT 82.650 98.430 83.150 98.550 ;
        RECT 82.650 98.170 89.330 98.430 ;
        RECT 82.650 98.050 83.150 98.170 ;
        RECT 88.320 97.860 88.820 97.910 ;
        RECT 82.055 97.660 88.820 97.860 ;
        RECT 82.255 97.460 88.820 97.660 ;
        RECT 88.320 97.410 88.820 97.460 ;
        RECT 89.070 97.530 89.330 98.170 ;
        RECT 103.270 98.130 103.530 100.270 ;
        RECT 125.270 102.470 126.130 102.730 ;
        RECT 126.390 105.405 126.790 107.535 ;
        RECT 127.000 106.695 127.500 106.745 ;
        RECT 127.710 106.695 128.110 108.875 ;
        RECT 133.580 108.380 133.980 109.075 ;
        RECT 138.410 108.895 138.910 109.395 ;
        RECT 138.460 108.380 138.860 108.895 ;
        RECT 140.460 108.380 140.960 108.430 ;
        RECT 132.210 108.185 132.710 108.235 ;
        RECT 132.870 108.185 133.370 108.235 ;
        RECT 132.210 107.785 133.370 108.185 ;
        RECT 132.210 107.735 132.710 107.785 ;
        RECT 132.870 107.735 133.370 107.785 ;
        RECT 133.580 107.980 140.960 108.380 ;
        RECT 127.000 106.295 128.110 106.695 ;
        RECT 127.000 106.245 127.500 106.295 ;
        RECT 127.000 105.405 127.500 105.455 ;
        RECT 126.390 105.005 127.500 105.405 ;
        RECT 126.390 102.825 126.790 105.005 ;
        RECT 127.000 104.955 127.500 105.005 ;
        RECT 127.000 104.115 127.500 104.165 ;
        RECT 127.710 104.115 128.110 106.295 ;
        RECT 132.260 105.605 132.660 107.735 ;
        RECT 132.870 106.895 133.370 106.945 ;
        RECT 133.580 106.895 133.980 107.980 ;
        RECT 140.460 107.930 140.960 107.980 ;
        RECT 132.870 106.495 133.980 106.895 ;
        RECT 132.870 106.445 133.370 106.495 ;
        RECT 132.870 105.605 133.370 105.655 ;
        RECT 128.745 104.955 129.245 105.455 ;
        RECT 132.260 105.205 133.370 105.605 ;
        RECT 127.000 103.715 128.110 104.115 ;
        RECT 127.000 103.665 127.500 103.715 ;
        RECT 127.000 102.825 127.500 102.875 ;
        RECT 126.390 102.625 127.500 102.825 ;
        RECT 125.270 99.430 125.530 102.470 ;
        RECT 126.590 102.425 127.500 102.625 ;
        RECT 127.000 102.375 127.500 102.425 ;
        RECT 125.765 102.180 126.265 102.230 ;
        RECT 127.710 102.180 128.110 103.715 ;
        RECT 132.260 103.025 132.660 105.205 ;
        RECT 132.870 105.155 133.370 105.205 ;
        RECT 132.870 104.315 133.370 104.365 ;
        RECT 133.580 104.315 133.980 106.495 ;
        RECT 137.765 106.375 138.265 106.425 ;
        RECT 137.765 105.975 151.115 106.375 ;
        RECT 134.615 105.155 135.115 105.655 ;
        RECT 137.765 105.325 138.265 105.975 ;
        RECT 140.395 105.825 140.795 105.975 ;
        RECT 142.975 105.825 143.375 105.975 ;
        RECT 145.555 105.825 145.955 105.975 ;
        RECT 148.135 105.825 148.535 105.975 ;
        RECT 150.715 105.825 151.115 105.975 ;
        RECT 139.055 105.325 139.555 105.825 ;
        RECT 140.345 105.325 140.845 105.825 ;
        RECT 141.635 105.325 142.135 105.825 ;
        RECT 142.925 105.325 143.425 105.825 ;
        RECT 144.215 105.325 144.715 105.825 ;
        RECT 145.505 105.325 146.005 105.825 ;
        RECT 146.795 105.325 147.295 105.825 ;
        RECT 148.085 105.325 148.585 105.825 ;
        RECT 139.105 105.175 139.505 105.325 ;
        RECT 141.685 105.175 142.085 105.325 ;
        RECT 144.265 105.175 144.665 105.325 ;
        RECT 146.845 105.175 147.245 105.325 ;
        RECT 149.375 105.175 149.875 105.825 ;
        RECT 150.665 105.325 151.165 105.825 ;
        RECT 139.105 104.775 149.875 105.175 ;
        RECT 149.375 104.725 149.875 104.775 ;
        RECT 132.870 103.915 133.980 104.315 ;
        RECT 141.450 104.050 141.950 104.550 ;
        RECT 132.870 103.865 133.370 103.915 ;
        RECT 132.870 103.025 133.370 103.075 ;
        RECT 132.260 102.825 133.370 103.025 ;
        RECT 132.460 102.625 133.370 102.825 ;
        RECT 132.870 102.575 133.370 102.625 ;
        RECT 125.765 101.780 128.110 102.180 ;
        RECT 131.635 101.930 132.135 102.430 ;
        RECT 125.765 101.730 126.265 101.780 ;
        RECT 127.000 101.535 127.500 101.585 ;
        RECT 127.710 101.535 128.110 101.780 ;
        RECT 127.000 101.135 128.110 101.535 ;
        RECT 127.000 101.085 127.500 101.135 ;
        RECT 127.710 100.230 128.110 101.135 ;
        RECT 131.685 100.230 132.085 101.930 ;
        RECT 132.870 101.735 133.370 101.785 ;
        RECT 133.580 101.735 133.980 103.915 ;
        RECT 139.850 103.050 140.350 103.550 ;
        RECT 132.870 101.535 133.980 101.735 ;
        RECT 132.870 101.335 133.780 101.535 ;
        RECT 132.870 101.285 133.370 101.335 ;
        RECT 127.710 100.030 132.555 100.230 ;
        RECT 126.890 99.430 127.390 99.930 ;
        RECT 127.910 99.830 132.555 100.030 ;
        RECT 124.470 99.170 125.530 99.430 ;
        RECT 112.450 98.130 112.950 98.250 ;
        RECT 103.270 97.870 112.950 98.130 ;
        RECT 112.450 97.750 112.950 97.870 ;
        RECT 123.290 98.130 123.790 98.240 ;
        RECT 124.470 98.130 124.730 99.170 ;
        RECT 124.960 98.885 125.460 98.935 ;
        RECT 126.940 98.885 127.340 99.430 ;
        RECT 124.960 98.770 127.340 98.885 ;
        RECT 124.960 98.630 127.480 98.770 ;
        RECT 124.960 98.450 128.230 98.630 ;
        RECT 124.960 98.435 128.450 98.450 ;
        RECT 123.290 97.870 124.730 98.130 ;
        RECT 124.970 98.370 128.450 98.435 ;
        RECT 123.290 97.740 123.790 97.870 ;
        RECT 124.970 97.630 125.230 98.370 ;
        RECT 126.495 97.660 126.995 98.160 ;
        RECT 127.285 97.660 127.785 98.160 ;
        RECT 127.950 97.950 128.450 98.370 ;
        RECT 130.510 98.110 130.910 99.830 ;
        RECT 132.700 99.430 133.200 99.930 ;
        RECT 132.305 98.110 132.805 98.160 ;
        RECT 130.510 97.910 132.805 98.110 ;
        RECT 130.710 97.710 132.805 97.910 ;
        RECT 132.305 97.660 132.805 97.710 ;
        RECT 133.095 97.660 133.595 98.160 ;
        RECT 136.230 97.940 136.730 98.440 ;
        RECT 123.970 97.530 125.230 97.630 ;
        RECT 89.070 97.370 125.230 97.530 ;
        RECT 89.070 97.270 124.230 97.370 ;
        RECT 123.960 95.680 124.460 96.180 ;
        RECT 127.335 95.880 127.735 97.660 ;
        RECT 133.145 95.880 133.545 97.660 ;
        RECT 127.335 95.680 133.545 95.880 ;
        RECT 134.960 95.680 135.460 96.180 ;
        RECT 88.970 95.160 89.470 95.660 ;
        RECT 127.535 95.480 133.345 95.680 ;
        RECT 82.145 94.445 82.645 94.945 ;
        RECT 126.940 94.275 127.440 94.325 ;
        RECT 126.545 94.075 127.440 94.275 ;
        RECT 126.345 93.875 127.440 94.075 ;
        RECT 126.345 93.725 126.745 93.875 ;
        RECT 126.940 93.825 127.440 93.875 ;
        RECT 131.305 93.840 131.805 93.890 ;
        RECT 126.295 93.675 126.795 93.725 ;
        RECT 125.710 93.475 126.795 93.675 ;
        RECT 125.510 93.275 126.795 93.475 ;
        RECT 81.265 90.410 81.765 90.910 ;
        RECT 122.460 90.880 122.960 90.930 ;
        RECT 125.510 90.880 125.910 93.275 ;
        RECT 126.295 93.225 126.795 93.275 ;
        RECT 127.585 93.225 128.085 93.725 ;
        RECT 130.710 93.640 131.805 93.840 ;
        RECT 130.510 93.440 131.805 93.640 ;
        RECT 126.940 92.115 127.440 92.615 ;
        RECT 130.510 90.880 130.910 93.440 ;
        RECT 131.305 93.390 131.805 93.440 ;
        RECT 132.510 93.195 132.910 95.480 ;
        RECT 139.970 94.950 140.230 103.050 ;
        RECT 140.875 95.255 141.375 95.755 ;
        RECT 133.515 94.035 134.015 94.535 ;
        RECT 139.850 94.450 140.350 94.950 ;
        RECT 140.875 93.965 141.375 94.465 ;
        RECT 136.235 93.390 136.735 93.890 ;
        RECT 138.975 93.770 139.475 93.820 ;
        RECT 137.210 93.570 139.475 93.770 ;
        RECT 137.010 93.370 139.475 93.570 ;
        RECT 133.515 93.195 134.015 93.245 ;
        RECT 132.510 92.995 134.015 93.195 ;
        RECT 132.710 92.795 134.015 92.995 ;
        RECT 133.515 92.745 134.015 92.795 ;
        RECT 137.010 90.880 137.410 93.370 ;
        RECT 138.975 93.320 139.475 93.370 ;
        RECT 137.960 93.125 138.460 93.175 ;
        RECT 140.875 93.125 141.375 93.175 ;
        RECT 137.960 92.725 141.375 93.125 ;
        RECT 137.960 92.675 138.460 92.725 ;
        RECT 140.875 92.675 141.375 92.725 ;
        RECT 141.570 92.430 141.830 104.050 ;
        RECT 144.215 101.245 144.715 101.745 ;
        RECT 142.405 98.645 142.905 99.145 ;
        RECT 143.145 98.645 143.645 99.145 ;
        RECT 148.125 98.645 148.625 99.145 ;
        RECT 140.970 92.170 141.830 92.430 ;
        RECT 122.460 90.480 139.225 90.880 ;
        RECT 122.460 90.430 122.960 90.480 ;
        RECT 80.770 89.970 81.530 90.230 ;
        RECT 80.560 89.090 81.060 89.590 ;
        RECT 80.550 88.350 81.050 88.850 ;
        RECT 53.870 81.325 63.930 81.330 ;
        RECT 53.840 81.070 63.930 81.325 ;
        RECT 72.120 81.425 72.620 81.475 ;
        RECT 53.840 81.065 54.160 81.070 ;
        RECT 56.590 81.065 56.910 81.070 ;
        RECT 62.140 79.770 62.640 80.270 ;
        RECT 62.540 70.030 63.040 70.190 ;
        RECT 63.670 70.030 63.930 81.070 ;
        RECT 66.250 81.225 66.750 81.275 ;
        RECT 72.120 81.225 73.030 81.425 ;
        RECT 66.250 81.025 67.160 81.225 ;
        RECT 72.120 81.025 73.230 81.225 ;
        RECT 66.250 80.825 67.360 81.025 ;
        RECT 72.120 80.975 72.620 81.025 ;
        RECT 66.250 80.775 66.750 80.825 ;
        RECT 65.590 79.935 66.090 79.985 ;
        RECT 66.250 79.935 66.750 79.985 ;
        RECT 65.590 79.535 66.750 79.935 ;
        RECT 65.590 79.485 66.090 79.535 ;
        RECT 66.250 79.485 66.750 79.535 ;
        RECT 65.640 77.355 66.040 79.485 ;
        RECT 66.250 78.645 66.750 78.695 ;
        RECT 66.960 78.645 67.360 80.825 ;
        RECT 72.830 80.330 73.230 81.025 ;
        RECT 77.660 80.845 78.160 81.345 ;
        RECT 77.710 80.330 78.110 80.845 ;
        RECT 79.710 80.330 80.210 80.380 ;
        RECT 71.460 80.135 71.960 80.185 ;
        RECT 72.120 80.135 72.620 80.185 ;
        RECT 71.460 79.735 72.620 80.135 ;
        RECT 71.460 79.685 71.960 79.735 ;
        RECT 72.120 79.685 72.620 79.735 ;
        RECT 72.830 79.930 80.210 80.330 ;
        RECT 66.250 78.245 67.360 78.645 ;
        RECT 66.250 78.195 66.750 78.245 ;
        RECT 66.250 77.355 66.750 77.405 ;
        RECT 65.640 76.955 66.750 77.355 ;
        RECT 65.640 74.775 66.040 76.955 ;
        RECT 66.250 76.905 66.750 76.955 ;
        RECT 66.250 76.065 66.750 76.115 ;
        RECT 66.960 76.065 67.360 78.245 ;
        RECT 71.510 77.555 71.910 79.685 ;
        RECT 72.120 78.845 72.620 78.895 ;
        RECT 72.830 78.845 73.230 79.930 ;
        RECT 79.710 79.880 80.210 79.930 ;
        RECT 80.670 79.050 80.930 88.350 ;
        RECT 81.270 85.850 81.530 89.970 ;
        RECT 81.150 85.350 81.650 85.850 ;
        RECT 81.220 84.630 81.720 85.130 ;
        RECT 132.680 79.775 133.180 79.825 ;
        RECT 126.810 79.575 127.310 79.625 ;
        RECT 132.680 79.575 133.590 79.775 ;
        RECT 126.810 79.375 127.720 79.575 ;
        RECT 132.680 79.375 133.790 79.575 ;
        RECT 126.810 79.175 127.920 79.375 ;
        RECT 132.680 79.325 133.180 79.375 ;
        RECT 126.810 79.125 127.310 79.175 ;
        RECT 72.120 78.445 73.230 78.845 ;
        RECT 80.550 78.550 81.050 79.050 ;
        RECT 72.120 78.395 72.620 78.445 ;
        RECT 72.120 77.555 72.620 77.605 ;
        RECT 67.995 76.905 68.495 77.405 ;
        RECT 71.510 77.155 72.620 77.555 ;
        RECT 66.250 75.665 67.360 76.065 ;
        RECT 66.250 75.615 66.750 75.665 ;
        RECT 66.250 74.775 66.750 74.825 ;
        RECT 65.640 74.575 66.750 74.775 ;
        RECT 65.840 74.375 66.750 74.575 ;
        RECT 66.250 74.325 66.750 74.375 ;
        RECT 65.015 74.130 65.515 74.180 ;
        RECT 66.960 74.130 67.360 75.665 ;
        RECT 71.510 74.975 71.910 77.155 ;
        RECT 72.120 77.105 72.620 77.155 ;
        RECT 72.120 76.265 72.620 76.315 ;
        RECT 72.830 76.265 73.230 78.445 ;
        RECT 77.015 78.325 77.515 78.375 ;
        RECT 77.015 77.925 90.365 78.325 ;
        RECT 122.700 78.120 123.200 78.620 ;
        RECT 126.150 78.285 126.650 78.335 ;
        RECT 126.810 78.285 127.310 78.335 ;
        RECT 73.865 77.105 74.365 77.605 ;
        RECT 77.015 77.275 77.515 77.925 ;
        RECT 79.645 77.775 80.045 77.925 ;
        RECT 82.225 77.775 82.625 77.925 ;
        RECT 84.805 77.775 85.205 77.925 ;
        RECT 87.385 77.775 87.785 77.925 ;
        RECT 89.965 77.775 90.365 77.925 ;
        RECT 126.150 77.885 127.310 78.285 ;
        RECT 78.305 77.275 78.805 77.775 ;
        RECT 79.595 77.275 80.095 77.775 ;
        RECT 80.885 77.275 81.385 77.775 ;
        RECT 82.175 77.275 82.675 77.775 ;
        RECT 83.465 77.275 83.965 77.775 ;
        RECT 84.755 77.275 85.255 77.775 ;
        RECT 86.045 77.275 86.545 77.775 ;
        RECT 87.335 77.275 87.835 77.775 ;
        RECT 78.355 77.125 78.755 77.275 ;
        RECT 80.935 77.125 81.335 77.275 ;
        RECT 83.515 77.125 83.915 77.275 ;
        RECT 86.095 77.125 86.495 77.275 ;
        RECT 88.625 77.125 89.125 77.775 ;
        RECT 89.915 77.275 90.415 77.775 ;
        RECT 121.050 77.350 121.550 77.850 ;
        RECT 126.150 77.835 126.650 77.885 ;
        RECT 126.810 77.835 127.310 77.885 ;
        RECT 78.355 76.725 89.125 77.125 ;
        RECT 88.625 76.675 89.125 76.725 ;
        RECT 72.120 75.865 73.230 76.265 ;
        RECT 80.750 76.050 81.250 76.550 ;
        RECT 72.120 75.815 72.620 75.865 ;
        RECT 72.120 74.975 72.620 75.025 ;
        RECT 71.510 74.775 72.620 74.975 ;
        RECT 71.710 74.575 72.620 74.775 ;
        RECT 72.120 74.525 72.620 74.575 ;
        RECT 65.015 73.730 67.360 74.130 ;
        RECT 70.885 73.880 71.385 74.380 ;
        RECT 65.015 73.680 65.515 73.730 ;
        RECT 66.250 73.485 66.750 73.535 ;
        RECT 66.960 73.485 67.360 73.730 ;
        RECT 66.250 73.085 67.360 73.485 ;
        RECT 66.250 73.035 66.750 73.085 ;
        RECT 66.960 72.180 67.360 73.085 ;
        RECT 70.935 72.180 71.335 73.880 ;
        RECT 72.120 73.685 72.620 73.735 ;
        RECT 72.830 73.685 73.230 75.865 ;
        RECT 72.120 73.485 73.230 73.685 ;
        RECT 72.120 73.285 73.030 73.485 ;
        RECT 72.120 73.235 72.620 73.285 ;
        RECT 66.960 71.980 71.805 72.180 ;
        RECT 66.140 71.380 66.640 71.880 ;
        RECT 67.160 71.780 71.805 71.980 ;
        RECT 64.210 70.835 64.710 70.885 ;
        RECT 66.190 70.835 66.590 71.380 ;
        RECT 64.210 70.635 66.590 70.835 ;
        RECT 64.210 70.435 66.390 70.635 ;
        RECT 64.210 70.385 64.710 70.435 ;
        RECT 62.540 69.770 63.930 70.030 ;
        RECT 62.540 69.690 63.040 69.770 ;
        RECT 65.745 69.610 66.245 70.110 ;
        RECT 66.535 69.610 67.035 70.110 ;
        RECT 69.760 70.060 70.160 71.780 ;
        RECT 71.950 71.380 72.450 71.880 ;
        RECT 71.555 70.060 72.055 70.110 ;
        RECT 69.760 69.860 72.055 70.060 ;
        RECT 69.960 69.660 72.055 69.860 ;
        RECT 71.555 69.610 72.055 69.660 ;
        RECT 72.345 69.610 72.845 70.110 ;
        RECT 75.480 69.890 75.980 70.390 ;
        RECT 62.670 63.550 62.930 69.250 ;
        RECT 63.210 67.630 63.710 68.130 ;
        RECT 66.585 67.830 66.985 69.610 ;
        RECT 72.395 67.830 72.795 69.610 ;
        RECT 66.585 67.630 72.795 67.830 ;
        RECT 74.210 67.630 74.710 68.130 ;
        RECT 66.785 67.430 72.595 67.630 ;
        RECT 66.190 66.225 66.690 66.275 ;
        RECT 65.795 66.025 66.690 66.225 ;
        RECT 65.595 65.825 66.690 66.025 ;
        RECT 65.595 65.675 65.995 65.825 ;
        RECT 66.190 65.775 66.690 65.825 ;
        RECT 70.555 65.790 71.055 65.840 ;
        RECT 65.545 65.625 66.045 65.675 ;
        RECT 64.960 65.425 66.045 65.625 ;
        RECT 64.760 65.225 66.045 65.425 ;
        RECT 62.670 63.170 63.250 63.550 ;
        RECT 62.750 63.050 63.250 63.170 ;
        RECT 61.710 62.830 62.210 62.880 ;
        RECT 64.760 62.830 65.160 65.225 ;
        RECT 65.545 65.175 66.045 65.225 ;
        RECT 66.835 65.175 67.335 65.675 ;
        RECT 69.960 65.590 71.055 65.790 ;
        RECT 69.760 65.390 71.055 65.590 ;
        RECT 66.190 64.065 66.690 64.565 ;
        RECT 69.760 62.830 70.160 65.390 ;
        RECT 70.555 65.340 71.055 65.390 ;
        RECT 71.760 65.145 72.160 67.430 ;
        RECT 80.125 67.205 80.625 67.705 ;
        RECT 72.765 65.985 73.265 66.485 ;
        RECT 80.125 65.915 80.625 66.415 ;
        RECT 75.485 65.340 75.985 65.840 ;
        RECT 78.225 65.720 78.725 65.770 ;
        RECT 76.460 65.520 78.725 65.720 ;
        RECT 76.260 65.320 78.725 65.520 ;
        RECT 72.765 65.145 73.265 65.195 ;
        RECT 71.760 64.945 73.265 65.145 ;
        RECT 71.960 64.745 73.265 64.945 ;
        RECT 72.765 64.695 73.265 64.745 ;
        RECT 76.260 62.830 76.660 65.320 ;
        RECT 78.225 65.270 78.725 65.320 ;
        RECT 77.210 65.075 77.710 65.125 ;
        RECT 80.125 65.075 80.625 65.125 ;
        RECT 77.210 64.675 80.625 65.075 ;
        RECT 77.210 64.625 77.710 64.675 ;
        RECT 80.125 64.625 80.625 64.675 ;
        RECT 61.710 62.430 78.475 62.830 ;
        RECT 61.710 62.380 62.210 62.430 ;
        RECT 80.870 61.850 81.130 76.050 ;
        RECT 83.465 73.195 83.965 73.695 ;
        RECT 81.655 70.595 82.155 71.095 ;
        RECT 82.395 70.595 82.895 71.095 ;
        RECT 87.375 70.595 87.875 71.095 ;
        RECT 81.705 62.380 82.105 70.595 ;
        RECT 82.445 69.330 82.845 70.595 ;
        RECT 88.710 69.330 89.210 69.380 ;
        RECT 82.445 69.130 89.210 69.330 ;
        RECT 82.645 68.930 89.210 69.130 ;
        RECT 88.710 68.880 89.210 68.930 ;
        RECT 89.360 66.630 89.860 67.130 ;
        RECT 82.535 65.915 83.035 66.415 ;
        RECT 81.655 61.880 82.155 62.380 ;
        RECT 80.750 61.350 81.250 61.850 ;
        RECT 80.950 60.560 81.450 61.060 ;
        RECT 121.170 6.750 121.430 77.350 ;
        RECT 126.200 75.705 126.600 77.835 ;
        RECT 126.810 76.995 127.310 77.045 ;
        RECT 127.520 76.995 127.920 79.175 ;
        RECT 133.390 78.680 133.790 79.375 ;
        RECT 138.220 79.195 138.720 79.695 ;
        RECT 138.270 78.680 138.670 79.195 ;
        RECT 140.270 78.680 140.770 78.730 ;
        RECT 132.020 78.485 132.520 78.535 ;
        RECT 132.680 78.485 133.180 78.535 ;
        RECT 132.020 78.085 133.180 78.485 ;
        RECT 132.020 78.035 132.520 78.085 ;
        RECT 132.680 78.035 133.180 78.085 ;
        RECT 133.390 78.280 140.770 78.680 ;
        RECT 126.810 76.595 127.920 76.995 ;
        RECT 126.810 76.545 127.310 76.595 ;
        RECT 126.810 75.705 127.310 75.755 ;
        RECT 126.200 75.305 127.310 75.705 ;
        RECT 126.200 73.125 126.600 75.305 ;
        RECT 126.810 75.255 127.310 75.305 ;
        RECT 126.810 74.415 127.310 74.465 ;
        RECT 127.520 74.415 127.920 76.595 ;
        RECT 132.070 75.905 132.470 78.035 ;
        RECT 132.680 77.195 133.180 77.245 ;
        RECT 133.390 77.195 133.790 78.280 ;
        RECT 140.270 78.230 140.770 78.280 ;
        RECT 140.970 78.030 141.230 92.170 ;
        RECT 142.455 90.430 142.855 98.645 ;
        RECT 143.195 97.380 143.595 98.645 ;
        RECT 149.460 97.380 149.960 97.430 ;
        RECT 143.195 97.180 149.960 97.380 ;
        RECT 143.395 96.980 149.960 97.180 ;
        RECT 149.460 96.930 149.960 96.980 ;
        RECT 169.870 95.930 170.130 119.035 ;
        RECT 193.670 118.585 193.930 118.630 ;
        RECT 193.605 118.325 193.930 118.585 ;
        RECT 187.650 108.910 187.910 109.230 ;
        RECT 187.710 108.745 187.850 108.910 ;
        RECT 187.640 108.375 187.920 108.745 ;
        RECT 193.670 98.130 193.930 118.325 ;
        RECT 243.760 117.215 244.040 117.585 ;
        RECT 204.480 112.795 206.020 113.165 ;
        RECT 243.830 112.630 243.970 117.215 ;
        RECT 243.770 112.310 244.030 112.630 ;
        RECT 245.610 111.970 245.870 112.290 ;
        RECT 240.090 111.290 240.350 111.610 ;
        RECT 243.310 111.290 243.570 111.610 ;
        RECT 207.780 110.075 209.320 110.445 ;
        RECT 238.250 108.570 238.510 108.890 ;
        RECT 233.650 108.230 233.910 108.550 ;
        RECT 230.890 107.890 231.150 108.210 ;
        RECT 204.480 107.355 206.020 107.725 ;
        RECT 229.510 105.510 229.770 105.830 ;
        RECT 207.780 104.635 209.320 105.005 ;
        RECT 204.480 101.915 206.020 102.285 ;
        RECT 207.780 99.195 209.320 99.565 ;
        RECT 179.870 97.930 193.930 98.130 ;
        RECT 178.470 97.870 193.930 97.930 ;
        RECT 177.105 97.415 177.430 97.675 ;
        RECT 178.470 97.670 180.130 97.870 ;
        RECT 180.335 97.675 180.595 97.705 ;
        RECT 178.470 97.635 178.795 97.670 ;
        RECT 173.650 95.930 174.150 96.050 ;
        RECT 169.870 95.670 174.150 95.930 ;
        RECT 173.650 95.550 174.150 95.670 ;
        RECT 150.110 94.680 150.610 95.180 ;
        RECT 177.170 94.730 177.430 97.415 ;
        RECT 178.470 97.195 178.795 97.455 ;
        RECT 178.470 95.050 178.730 97.195 ;
        RECT 178.970 95.630 179.230 97.670 ;
        RECT 180.335 97.385 180.630 97.675 ;
        RECT 178.970 95.370 179.330 95.630 ;
        RECT 179.650 95.550 180.150 96.050 ;
        RECT 176.670 94.470 177.430 94.730 ;
        RECT 143.285 93.965 143.785 94.465 ;
        RECT 142.405 89.930 142.905 90.430 ;
        RECT 141.700 88.610 142.200 89.110 ;
        RECT 176.670 88.650 176.930 94.470 ;
        RECT 177.605 94.230 177.930 94.255 ;
        RECT 177.170 93.970 177.930 94.230 ;
        RECT 178.250 94.215 178.750 95.050 ;
        RECT 178.350 94.030 178.850 94.050 ;
        RECT 179.070 94.030 179.330 95.370 ;
        RECT 179.770 94.350 180.030 95.550 ;
        RECT 142.350 87.850 142.850 88.350 ;
        RECT 176.450 88.150 176.950 88.650 ;
        RECT 177.170 87.935 177.430 93.970 ;
        RECT 178.350 93.770 179.330 94.030 ;
        RECT 179.650 93.850 180.150 94.350 ;
        RECT 178.350 93.550 178.850 93.770 ;
        RECT 179.770 89.650 180.030 93.850 ;
        RECT 179.550 89.150 180.050 89.650 ;
        RECT 178.570 88.155 179.330 88.230 ;
        RECT 178.515 87.970 179.330 88.155 ;
        RECT 177.145 87.930 177.465 87.935 ;
        RECT 141.780 82.980 142.280 83.480 ;
        RECT 132.680 76.795 133.790 77.195 ;
        RECT 132.680 76.745 133.180 76.795 ;
        RECT 132.680 75.905 133.180 75.955 ;
        RECT 128.555 75.255 129.055 75.755 ;
        RECT 132.070 75.505 133.180 75.905 ;
        RECT 126.810 74.015 127.920 74.415 ;
        RECT 126.810 73.965 127.310 74.015 ;
        RECT 126.810 73.125 127.310 73.175 ;
        RECT 126.200 72.925 127.310 73.125 ;
        RECT 126.400 72.725 127.310 72.925 ;
        RECT 126.810 72.675 127.310 72.725 ;
        RECT 125.575 72.480 126.075 72.530 ;
        RECT 127.520 72.480 127.920 74.015 ;
        RECT 132.070 73.325 132.470 75.505 ;
        RECT 132.680 75.455 133.180 75.505 ;
        RECT 132.680 74.615 133.180 74.665 ;
        RECT 133.390 74.615 133.790 76.795 ;
        RECT 136.770 77.770 141.230 78.030 ;
        RECT 134.425 75.455 134.925 75.955 ;
        RECT 132.680 74.215 133.790 74.615 ;
        RECT 132.680 74.165 133.180 74.215 ;
        RECT 132.680 73.325 133.180 73.375 ;
        RECT 132.070 73.125 133.180 73.325 ;
        RECT 132.270 72.925 133.180 73.125 ;
        RECT 132.680 72.875 133.180 72.925 ;
        RECT 125.575 72.080 127.920 72.480 ;
        RECT 131.445 72.230 131.945 72.730 ;
        RECT 125.575 72.030 126.075 72.080 ;
        RECT 126.810 71.835 127.310 71.885 ;
        RECT 127.520 71.835 127.920 72.080 ;
        RECT 126.810 71.435 127.920 71.835 ;
        RECT 126.810 71.385 127.310 71.435 ;
        RECT 127.520 70.530 127.920 71.435 ;
        RECT 131.495 70.530 131.895 72.230 ;
        RECT 132.680 72.035 133.180 72.085 ;
        RECT 133.390 72.035 133.790 74.215 ;
        RECT 132.680 71.835 133.790 72.035 ;
        RECT 132.680 71.635 133.590 71.835 ;
        RECT 132.680 71.585 133.180 71.635 ;
        RECT 127.520 70.330 132.365 70.530 ;
        RECT 126.700 69.730 127.200 70.230 ;
        RECT 127.720 70.130 132.365 70.330 ;
        RECT 124.770 69.185 125.270 69.235 ;
        RECT 126.750 69.185 127.150 69.730 ;
        RECT 124.770 68.985 127.150 69.185 ;
        RECT 124.770 68.785 126.950 68.985 ;
        RECT 124.770 68.735 125.270 68.785 ;
        RECT 123.100 68.430 123.600 68.540 ;
        RECT 121.770 68.170 123.600 68.430 ;
        RECT 121.770 7.750 122.030 68.170 ;
        RECT 123.100 68.040 123.600 68.170 ;
        RECT 126.305 67.960 126.805 68.460 ;
        RECT 127.095 67.960 127.595 68.460 ;
        RECT 130.320 68.410 130.720 70.130 ;
        RECT 132.510 69.730 133.010 70.230 ;
        RECT 132.115 68.410 132.615 68.460 ;
        RECT 130.320 68.210 132.615 68.410 ;
        RECT 130.520 68.010 132.615 68.210 ;
        RECT 132.115 67.960 132.615 68.010 ;
        RECT 132.905 67.960 133.405 68.460 ;
        RECT 136.040 68.240 136.540 68.740 ;
        RECT 136.770 68.030 137.030 77.770 ;
        RECT 142.470 77.350 142.730 87.850 ;
        RECT 177.070 87.675 177.465 87.930 ;
        RECT 178.515 87.895 178.835 87.970 ;
        RECT 177.070 87.670 177.430 87.675 ;
        RECT 177.070 84.030 177.330 87.670 ;
        RECT 178.515 87.630 178.835 87.715 ;
        RECT 178.470 87.455 178.835 87.630 ;
        RECT 177.550 86.950 178.050 87.450 ;
        RECT 177.670 84.750 177.930 86.950 ;
        RECT 178.470 86.450 178.830 87.455 ;
        RECT 178.350 85.950 178.850 86.450 ;
        RECT 178.570 85.750 178.830 85.950 ;
        RECT 178.350 85.250 178.850 85.750 ;
        RECT 177.550 84.250 178.050 84.750 ;
        RECT 178.470 84.735 178.830 85.250 ;
        RECT 178.390 84.570 178.830 84.735 ;
        RECT 178.390 84.475 178.730 84.570 ;
        RECT 178.390 84.230 178.730 84.295 ;
        RECT 179.070 84.230 179.330 87.970 ;
        RECT 178.390 84.035 179.330 84.230 ;
        RECT 177.070 83.770 178.130 84.030 ;
        RECT 176.950 83.050 177.450 83.550 ;
        RECT 177.070 79.375 177.330 83.050 ;
        RECT 177.005 79.115 177.330 79.375 ;
        RECT 142.350 76.850 142.850 77.350 ;
        RECT 137.575 76.675 138.075 76.725 ;
        RECT 137.575 76.275 150.925 76.675 ;
        RECT 137.575 75.625 138.075 76.275 ;
        RECT 140.205 76.125 140.605 76.275 ;
        RECT 142.785 76.125 143.185 76.275 ;
        RECT 145.365 76.125 145.765 76.275 ;
        RECT 147.945 76.125 148.345 76.275 ;
        RECT 150.525 76.125 150.925 76.275 ;
        RECT 138.865 75.625 139.365 76.125 ;
        RECT 140.155 75.625 140.655 76.125 ;
        RECT 141.445 75.625 141.945 76.125 ;
        RECT 142.735 75.625 143.235 76.125 ;
        RECT 144.025 75.625 144.525 76.125 ;
        RECT 145.315 75.625 145.815 76.125 ;
        RECT 146.605 75.625 147.105 76.125 ;
        RECT 147.895 75.625 148.395 76.125 ;
        RECT 138.915 75.475 139.315 75.625 ;
        RECT 141.495 75.475 141.895 75.625 ;
        RECT 144.075 75.475 144.475 75.625 ;
        RECT 146.655 75.475 147.055 75.625 ;
        RECT 149.185 75.475 149.685 76.125 ;
        RECT 150.475 75.625 150.975 76.125 ;
        RECT 177.070 75.730 177.330 79.115 ;
        RECT 177.870 79.130 178.130 83.770 ;
        RECT 178.470 83.970 179.330 84.035 ;
        RECT 179.670 84.270 180.030 89.150 ;
        RECT 180.370 88.050 180.630 97.385 ;
        RECT 204.480 96.475 206.020 96.845 ;
        RECT 228.590 95.310 228.850 95.630 ;
        RECT 207.780 93.755 209.320 94.125 ;
        RECT 226.290 93.270 226.550 93.590 ;
        RECT 204.480 91.035 206.020 91.405 ;
        RECT 207.780 88.315 209.320 88.685 ;
        RECT 180.250 87.550 180.750 88.050 ;
        RECT 179.670 84.225 179.965 84.270 ;
        RECT 178.470 83.030 178.730 83.970 ;
        RECT 178.470 82.770 179.330 83.030 ;
        RECT 178.350 82.050 178.850 82.550 ;
        RECT 178.370 79.630 178.630 82.050 ;
        RECT 179.070 81.350 179.330 82.770 ;
        RECT 178.950 80.850 179.450 81.350 ;
        RECT 179.670 80.350 179.930 84.225 ;
        RECT 179.550 79.850 180.050 80.350 ;
        RECT 180.370 79.630 180.630 87.550 ;
        RECT 226.350 87.470 226.490 93.270 ;
        RECT 226.290 87.150 226.550 87.470 ;
        RECT 228.650 87.130 228.790 95.310 ;
        RECT 229.050 89.190 229.310 89.510 ;
        RECT 228.590 86.810 228.850 87.130 ;
        RECT 204.480 85.595 206.020 85.965 ;
        RECT 207.780 82.875 209.320 83.245 ;
        RECT 204.480 80.155 206.020 80.525 ;
        RECT 178.370 79.370 180.630 79.630 ;
        RECT 178.370 79.335 178.695 79.370 ;
        RECT 178.370 79.130 178.695 79.155 ;
        RECT 177.870 78.870 179.130 79.130 ;
        RECT 177.070 75.705 177.730 75.730 ;
        RECT 138.915 75.075 149.685 75.475 ;
        RECT 177.070 75.470 177.795 75.705 ;
        RECT 178.150 75.650 178.650 76.150 ;
        RECT 149.185 75.025 149.685 75.075 ;
        RECT 177.470 75.445 177.795 75.470 ;
        RECT 144.025 71.545 144.525 72.045 ;
        RECT 177.470 69.930 177.730 75.445 ;
        RECT 178.300 75.430 178.630 75.485 ;
        RECT 178.870 75.430 179.130 78.870 ;
        RECT 179.450 78.650 179.950 79.150 ;
        RECT 180.235 79.085 180.630 79.370 ;
        RECT 180.270 79.070 180.630 79.085 ;
        RECT 179.570 76.150 179.830 78.650 ;
        RECT 207.780 77.435 209.320 77.805 ;
        RECT 179.450 75.650 179.950 76.150 ;
        RECT 179.570 75.445 179.875 75.650 ;
        RECT 178.300 75.225 179.130 75.430 ;
        RECT 179.615 75.415 179.875 75.445 ;
        RECT 178.370 75.170 179.130 75.225 ;
        RECT 204.480 74.715 206.020 75.085 ;
        RECT 229.110 73.385 229.250 89.190 ;
        RECT 229.570 89.170 229.710 105.510 ;
        RECT 230.430 100.750 230.690 101.070 ;
        RECT 230.490 98.350 230.630 100.750 ;
        RECT 230.430 98.030 230.690 98.350 ;
        RECT 230.950 98.010 231.090 107.890 ;
        RECT 233.710 104.130 233.850 108.230 ;
        RECT 237.790 107.890 238.050 108.210 ;
        RECT 237.850 106.510 237.990 107.890 ;
        RECT 238.310 107.190 238.450 108.570 ;
        RECT 238.250 106.870 238.510 107.190 ;
        RECT 237.790 106.190 238.050 106.510 ;
        RECT 238.710 106.190 238.970 106.510 ;
        RECT 233.650 103.810 233.910 104.130 ;
        RECT 233.710 101.150 233.850 103.810 ;
        RECT 237.330 103.130 237.590 103.450 ;
        RECT 234.110 102.450 234.370 102.770 ;
        RECT 233.250 101.010 233.850 101.150 ;
        RECT 233.250 100.390 233.390 101.010 ;
        RECT 233.190 100.070 233.450 100.390 ;
        RECT 231.350 98.030 231.610 98.350 ;
        RECT 230.890 97.690 231.150 98.010 ;
        RECT 229.970 97.010 230.230 97.330 ;
        RECT 230.030 95.290 230.170 97.010 ;
        RECT 229.970 94.970 230.230 95.290 ;
        RECT 230.430 94.290 230.690 94.610 ;
        RECT 229.970 91.570 230.230 91.890 ;
        RECT 229.510 88.850 229.770 89.170 ;
        RECT 229.570 76.930 229.710 88.850 ;
        RECT 230.030 87.130 230.170 91.570 ;
        RECT 229.970 86.810 230.230 87.130 ;
        RECT 230.490 78.970 230.630 94.290 ;
        RECT 231.410 93.590 231.550 98.030 ;
        RECT 231.350 93.270 231.610 93.590 ;
        RECT 233.250 93.250 233.390 100.070 ;
        RECT 233.190 92.930 233.450 93.250 ;
        RECT 232.730 92.250 232.990 92.570 ;
        RECT 232.790 88.150 232.930 92.250 ;
        RECT 233.250 90.430 233.390 92.930 ;
        RECT 234.170 92.910 234.310 102.450 ;
        RECT 237.390 101.750 237.530 103.130 ;
        RECT 237.850 102.770 237.990 106.190 ;
        RECT 238.770 104.470 238.910 106.190 ;
        RECT 238.710 104.150 238.970 104.470 ;
        RECT 239.170 103.470 239.430 103.790 ;
        RECT 237.790 102.450 238.050 102.770 ;
        RECT 237.330 101.430 237.590 101.750 ;
        RECT 237.850 101.070 237.990 102.450 ;
        RECT 237.790 100.750 238.050 101.070 ;
        RECT 235.030 100.070 235.290 100.390 ;
        RECT 235.090 99.030 235.230 100.070 ;
        RECT 235.030 98.710 235.290 99.030 ;
        RECT 239.230 98.010 239.370 103.470 ;
        RECT 240.150 103.110 240.290 111.290 ;
        RECT 243.370 106.510 243.510 111.290 ;
        RECT 245.670 110.785 245.810 111.970 ;
        RECT 245.600 110.415 245.880 110.785 ;
        RECT 243.310 106.190 243.570 106.510 ;
        RECT 244.690 105.850 244.950 106.170 ;
        RECT 240.090 102.790 240.350 103.110 ;
        RECT 244.750 101.070 244.890 105.850 ;
        RECT 245.610 105.170 245.870 105.490 ;
        RECT 245.670 103.985 245.810 105.170 ;
        RECT 245.600 103.615 245.880 103.985 ;
        RECT 244.690 100.750 244.950 101.070 ;
        RECT 239.170 97.690 239.430 98.010 ;
        RECT 234.110 92.590 234.370 92.910 ;
        RECT 233.250 90.290 235.230 90.430 ;
        RECT 232.730 87.830 232.990 88.150 ;
        RECT 231.350 86.810 231.610 87.130 ;
        RECT 231.410 82.710 231.550 86.810 ;
        RECT 231.350 82.390 231.610 82.710 ;
        RECT 235.090 82.370 235.230 90.290 ;
        RECT 235.030 82.050 235.290 82.370 ;
        RECT 231.350 78.990 231.610 79.310 ;
        RECT 230.430 78.650 230.690 78.970 ;
        RECT 229.510 76.610 229.770 76.930 ;
        RECT 231.410 73.870 231.550 78.990 ;
        RECT 235.090 78.630 235.230 82.050 ;
        RECT 238.710 81.370 238.970 81.690 ;
        RECT 238.770 79.990 238.910 81.370 ;
        RECT 238.710 79.670 238.970 79.990 ;
        RECT 235.030 78.310 235.290 78.630 ;
        RECT 232.730 75.250 232.990 75.570 ;
        RECT 231.350 73.550 231.610 73.870 ;
        RECT 229.040 73.015 229.320 73.385 ;
        RECT 207.780 71.995 209.320 72.365 ;
        RECT 231.410 71.150 231.550 73.550 ;
        RECT 232.790 71.490 232.930 75.250 ;
        RECT 235.090 73.190 235.230 78.310 ;
        RECT 235.030 72.870 235.290 73.190 ;
        RECT 235.090 71.490 235.230 72.870 ;
        RECT 232.730 71.170 232.990 71.490 ;
        RECT 235.030 71.170 235.290 71.490 ;
        RECT 231.350 70.830 231.610 71.150 ;
        RECT 123.770 65.980 124.270 66.480 ;
        RECT 127.145 66.180 127.545 67.960 ;
        RECT 132.955 66.180 133.355 67.960 ;
        RECT 136.070 67.770 137.030 68.030 ;
        RECT 141.770 69.670 177.730 69.930 ;
        RECT 127.145 65.980 133.355 66.180 ;
        RECT 134.770 65.980 135.270 66.480 ;
        RECT 127.345 65.780 133.155 65.980 ;
        RECT 126.750 64.575 127.250 64.625 ;
        RECT 126.355 64.375 127.250 64.575 ;
        RECT 126.155 64.175 127.250 64.375 ;
        RECT 126.155 64.025 126.555 64.175 ;
        RECT 126.750 64.125 127.250 64.175 ;
        RECT 131.115 64.140 131.615 64.190 ;
        RECT 126.105 63.975 126.605 64.025 ;
        RECT 125.520 63.775 126.605 63.975 ;
        RECT 125.320 63.575 126.605 63.775 ;
        RECT 122.270 61.180 122.770 61.230 ;
        RECT 125.320 61.180 125.720 63.575 ;
        RECT 126.105 63.525 126.605 63.575 ;
        RECT 127.395 63.525 127.895 64.025 ;
        RECT 130.520 63.940 131.615 64.140 ;
        RECT 130.320 63.740 131.615 63.940 ;
        RECT 126.750 62.415 127.250 62.915 ;
        RECT 130.320 61.180 130.720 63.740 ;
        RECT 131.115 63.690 131.615 63.740 ;
        RECT 132.320 63.495 132.720 65.780 ;
        RECT 136.070 65.650 136.330 67.770 ;
        RECT 136.550 67.330 137.050 67.450 ;
        RECT 141.770 67.330 142.030 69.670 ;
        RECT 142.250 69.445 142.750 69.450 ;
        RECT 142.215 68.950 142.750 69.445 ;
        RECT 142.215 68.945 142.715 68.950 ;
        RECT 142.955 68.945 143.455 69.445 ;
        RECT 147.935 68.945 148.435 69.445 ;
        RECT 204.480 69.275 206.020 69.645 ;
        RECT 136.550 67.070 142.030 67.330 ;
        RECT 136.550 66.950 137.050 67.070 ;
        RECT 135.950 65.150 136.450 65.650 ;
        RECT 140.685 65.555 141.185 66.055 ;
        RECT 133.325 64.335 133.825 64.835 ;
        RECT 140.685 64.265 141.185 64.765 ;
        RECT 136.045 63.690 136.545 64.190 ;
        RECT 138.785 64.070 139.285 64.120 ;
        RECT 137.020 63.870 139.285 64.070 ;
        RECT 136.820 63.670 139.285 63.870 ;
        RECT 133.325 63.495 133.825 63.545 ;
        RECT 132.320 63.295 133.825 63.495 ;
        RECT 132.520 63.095 133.825 63.295 ;
        RECT 133.325 63.045 133.825 63.095 ;
        RECT 136.820 61.180 137.220 63.670 ;
        RECT 138.785 63.620 139.285 63.670 ;
        RECT 137.770 63.425 138.270 63.475 ;
        RECT 140.685 63.425 141.185 63.475 ;
        RECT 137.770 63.025 141.185 63.425 ;
        RECT 137.770 62.975 138.270 63.025 ;
        RECT 140.685 62.975 141.185 63.025 ;
        RECT 122.270 60.780 139.035 61.180 ;
        RECT 122.270 60.730 122.770 60.780 ;
        RECT 142.265 60.730 142.665 68.945 ;
        RECT 143.005 67.680 143.405 68.945 ;
        RECT 239.230 68.090 239.370 97.690 ;
        RECT 245.610 97.350 245.870 97.670 ;
        RECT 245.670 97.185 245.810 97.350 ;
        RECT 245.600 96.815 245.880 97.185 ;
        RECT 245.610 91.570 245.870 91.890 ;
        RECT 245.670 90.385 245.810 91.570 ;
        RECT 245.600 90.015 245.880 90.385 ;
        RECT 244.690 84.090 244.950 84.410 ;
        RECT 243.770 81.370 244.030 81.690 ;
        RECT 243.830 79.310 243.970 81.370 ;
        RECT 243.770 78.990 244.030 79.310 ;
        RECT 240.090 78.650 240.350 78.970 ;
        RECT 240.150 74.550 240.290 78.650 ;
        RECT 243.830 78.630 243.970 78.990 ;
        RECT 244.750 78.970 244.890 84.090 ;
        RECT 245.610 83.585 245.870 83.730 ;
        RECT 245.600 83.215 245.880 83.585 ;
        RECT 244.690 78.650 244.950 78.970 ;
        RECT 243.770 78.310 244.030 78.630 ;
        RECT 242.850 77.970 243.110 78.290 ;
        RECT 242.910 76.250 243.050 77.970 ;
        RECT 243.830 76.930 243.970 78.310 ;
        RECT 243.770 76.610 244.030 76.930 ;
        RECT 243.310 76.270 243.570 76.590 ;
        RECT 245.600 76.415 245.880 76.785 ;
        RECT 242.850 75.930 243.110 76.250 ;
        RECT 240.090 74.230 240.350 74.550 ;
        RECT 242.910 71.150 243.050 75.930 ;
        RECT 243.370 73.530 243.510 76.270 ;
        RECT 245.670 75.910 245.810 76.415 ;
        RECT 245.610 75.590 245.870 75.910 ;
        RECT 243.310 73.210 243.570 73.530 ;
        RECT 243.370 71.830 243.510 73.210 ;
        RECT 243.310 71.510 243.570 71.830 ;
        RECT 242.850 70.830 243.110 71.150 ;
        RECT 245.610 69.985 245.870 70.130 ;
        RECT 245.600 69.615 245.880 69.985 ;
        RECT 239.170 67.770 239.430 68.090 ;
        RECT 149.270 67.680 149.770 67.730 ;
        RECT 143.005 67.480 149.770 67.680 ;
        RECT 143.205 67.280 149.770 67.480 ;
        RECT 149.270 67.230 149.770 67.280 ;
        RECT 245.610 67.090 245.870 67.410 ;
        RECT 207.780 66.555 209.320 66.925 ;
        RECT 149.150 64.950 149.650 65.450 ;
        RECT 149.920 64.980 150.420 65.480 ;
        RECT 143.095 64.265 143.595 64.765 ;
        RECT 142.215 60.230 142.715 60.730 ;
        RECT 142.370 59.450 142.630 60.230 ;
        RECT 141.510 58.910 142.010 59.410 ;
        RECT 142.250 58.950 142.750 59.450 ;
        RECT 132.650 55.450 133.150 55.950 ;
        RECT 132.770 7.750 133.030 55.450 ;
        RECT 149.270 20.350 149.530 64.950 ;
        RECT 245.670 63.185 245.810 67.090 ;
        RECT 245.600 62.815 245.880 63.185 ;
        RECT 149.150 19.850 149.650 20.350 ;
        RECT 121.650 7.250 122.150 7.750 ;
        RECT 132.650 7.250 133.150 7.750 ;
        RECT 121.050 6.250 121.550 6.750 ;
      LAYER met3 ;
        RECT 94.050 221.750 265.250 222.250 ;
        RECT 52.850 128.550 53.350 129.050 ;
        RECT 66.150 128.350 140.650 128.850 ;
        RECT 145.950 127.950 194.050 128.450 ;
        RECT 64.850 126.750 65.550 127.250 ;
        RECT 66.050 127.150 140.450 127.650 ;
        RECT 65.050 126.650 65.550 126.750 ;
        RECT 65.050 126.150 103.450 126.650 ;
        RECT 65.850 123.750 140.350 124.250 ;
        RECT 146.050 121.850 194.050 122.350 ;
        RECT 66.150 120.550 140.250 121.050 ;
        RECT 145.950 120.650 194.150 121.150 ;
        RECT 103.150 118.950 103.650 119.450 ;
        RECT 243.735 117.550 244.065 117.565 ;
        RECT 249.410 117.550 253.410 117.700 ;
        RECT 243.735 117.250 253.410 117.550 ;
        RECT 243.735 117.235 244.065 117.250 ;
        RECT 249.410 117.100 253.410 117.250 ;
        RECT 80.780 113.650 81.380 113.710 ;
        RECT 80.050 113.560 81.380 113.650 ;
        RECT 65.450 113.160 89.570 113.560 ;
        RECT 65.150 113.150 89.570 113.160 ;
        RECT 141.920 113.150 142.520 113.230 ;
        RECT 65.150 113.080 142.520 113.150 ;
        RECT 65.150 112.760 150.710 113.080 ;
        RECT 204.460 112.815 206.040 113.145 ;
        RECT 61.650 108.200 62.350 108.900 ;
        RECT 65.150 107.965 65.750 112.760 ;
        RECT 67.555 105.385 68.155 112.760 ;
        RECT 71.020 108.165 71.620 112.760 ;
        RECT 73.425 105.585 74.025 112.760 ;
        RECT 80.850 112.650 150.710 112.760 ;
        RECT 79.220 108.310 79.920 109.010 ;
        RECT 59.650 101.450 60.150 103.350 ;
        RECT 59.650 100.950 63.350 101.450 ;
        RECT 62.400 100.160 72.110 100.460 ;
        RECT 62.100 99.860 72.110 100.160 ;
        RECT 62.100 98.670 62.700 99.860 ;
        RECT 63.720 98.815 64.420 99.515 ;
        RECT 61.680 98.370 63.120 98.670 ;
        RECT 61.380 97.950 63.120 98.370 ;
        RECT 60.650 97.750 63.120 97.950 ;
        RECT 60.650 97.450 63.070 97.750 ;
        RECT 61.220 90.810 61.920 91.510 ;
        RECT 62.770 89.740 63.370 96.710 ;
        RECT 63.850 90.250 64.350 98.815 ;
        RECT 65.255 98.040 65.955 98.740 ;
        RECT 74.990 98.320 75.690 99.020 ;
        RECT 66.395 93.955 66.995 94.255 ;
        RECT 66.345 93.145 67.045 93.955 ;
        RECT 65.750 89.740 67.045 93.145 ;
        RECT 72.325 89.740 72.925 95.065 ;
        RECT 73.770 89.740 74.370 96.710 ;
        RECT 75.050 94.420 75.550 97.950 ;
        RECT 76.575 96.460 77.175 106.955 ;
        RECT 80.850 106.250 81.350 112.650 ;
        RECT 80.650 105.750 81.350 106.250 ;
        RECT 83.025 101.675 83.625 112.650 ;
        RECT 88.185 105.155 88.785 112.650 ;
        RECT 126.290 112.280 150.710 112.650 ;
        RECT 91.850 104.450 112.010 110.440 ;
        RECT 122.790 107.720 123.490 108.420 ;
        RECT 126.290 107.485 126.890 112.280 ;
        RECT 128.695 104.905 129.295 112.280 ;
        RECT 132.160 107.685 132.760 112.280 ;
        RECT 134.565 105.105 135.165 112.280 ;
        RECT 135.650 110.250 140.550 110.750 ;
        RECT 135.650 104.650 136.150 110.250 ;
        RECT 140.050 109.450 140.550 110.250 ;
        RECT 141.950 110.450 142.450 112.280 ;
        RECT 141.950 109.950 143.050 110.450 ;
        RECT 140.050 108.950 142.050 109.450 ;
        RECT 140.360 107.830 141.060 108.530 ;
        RECT 141.550 107.350 142.050 108.950 ;
        RECT 141.450 106.850 142.050 107.350 ;
        RECT 129.750 104.450 136.150 104.650 ;
        RECT 89.350 104.150 136.150 104.450 ;
        RECT 89.350 103.950 130.250 104.150 ;
        RECT 78.250 100.150 88.850 100.650 ;
        RECT 86.885 99.025 87.585 99.725 ;
        RECT 77.650 98.050 83.150 98.550 ;
        RECT 88.220 97.310 88.920 98.010 ;
        RECT 89.350 96.850 89.850 103.950 ;
        RECT 88.950 96.460 89.850 96.850 ;
        RECT 91.850 96.460 112.010 103.950 ;
        RECT 123.540 99.680 133.250 99.980 ;
        RECT 123.240 99.380 133.250 99.680 ;
        RECT 76.575 96.160 112.010 96.460 ;
        RECT 76.770 95.860 112.010 96.160 ;
        RECT 112.450 96.450 112.950 98.250 ;
        RECT 123.240 97.690 123.840 99.380 ;
        RECT 124.860 98.335 125.560 99.035 ;
        RECT 126.395 97.560 127.095 98.260 ;
        RECT 127.950 97.950 128.450 98.450 ;
        RECT 136.130 97.840 136.830 98.540 ;
        RECT 112.450 96.230 124.250 96.450 ;
        RECT 112.450 95.950 124.510 96.230 ;
        RECT 75.045 89.740 75.645 94.420 ;
        RECT 76.770 93.105 77.370 95.860 ;
        RECT 79.685 95.685 80.285 95.860 ;
        RECT 87.530 95.440 89.520 95.860 ;
        RECT 87.830 95.140 89.520 95.440 ;
        RECT 88.920 95.110 89.520 95.140 ;
        RECT 79.685 89.740 80.285 94.995 ;
        RECT 82.095 90.960 82.695 94.995 ;
        RECT 91.850 92.040 112.010 95.860 ;
        RECT 80.915 89.740 82.695 90.960 ;
        RECT 122.360 90.330 123.060 91.030 ;
        RECT 62.770 88.940 82.695 89.740 ;
        RECT 123.910 89.260 124.510 95.950 ;
        RECT 127.535 93.475 128.135 93.775 ;
        RECT 127.485 92.665 128.185 93.475 ;
        RECT 126.890 89.260 128.185 92.665 ;
        RECT 133.465 89.260 134.065 94.585 ;
        RECT 134.910 89.260 135.510 96.230 ;
        RECT 136.250 93.940 136.750 97.450 ;
        RECT 137.715 95.980 138.315 106.475 ;
        RECT 141.450 104.050 141.950 106.850 ;
        RECT 142.550 106.350 143.050 109.950 ;
        RECT 142.450 105.850 143.050 106.350 ;
        RECT 142.450 103.550 142.950 105.850 ;
        RECT 139.850 103.050 142.950 103.550 ;
        RECT 144.165 101.195 144.765 112.280 ;
        RECT 149.325 104.675 149.925 112.280 ;
        RECT 245.575 110.750 245.905 110.765 ;
        RECT 249.410 110.750 253.410 110.900 ;
        RECT 245.575 110.450 253.410 110.750 ;
        RECT 245.575 110.435 245.905 110.450 ;
        RECT 207.760 110.095 209.340 110.425 ;
        RECT 249.410 110.300 253.410 110.450 ;
        RECT 148.025 98.545 148.725 99.245 ;
        RECT 149.360 96.830 150.060 97.530 ;
        RECT 152.990 95.980 173.150 109.960 ;
        RECT 187.615 108.710 187.945 108.725 ;
        RECT 187.400 108.395 187.945 108.710 ;
        RECT 187.400 108.180 187.700 108.395 ;
        RECT 183.410 107.730 187.700 108.180 ;
        RECT 183.410 107.580 187.410 107.730 ;
        RECT 204.460 107.375 206.040 107.705 ;
        RECT 207.760 104.655 209.340 104.985 ;
        RECT 245.575 103.950 245.905 103.965 ;
        RECT 249.410 103.950 253.410 104.100 ;
        RECT 245.575 103.650 253.410 103.950 ;
        RECT 245.575 103.635 245.905 103.650 ;
        RECT 249.410 103.500 253.410 103.650 ;
        RECT 204.460 101.935 206.040 102.265 ;
        RECT 207.760 99.215 209.340 99.545 ;
        RECT 245.575 97.150 245.905 97.165 ;
        RECT 249.410 97.150 253.410 97.300 ;
        RECT 245.575 96.850 253.410 97.150 ;
        RECT 245.575 96.835 245.905 96.850 ;
        RECT 204.460 96.495 206.040 96.825 ;
        RECT 249.410 96.700 253.410 96.850 ;
        RECT 137.715 95.680 173.150 95.980 ;
        RECT 137.910 95.380 173.150 95.680 ;
        RECT 173.650 95.550 180.150 96.050 ;
        RECT 136.185 89.260 136.785 93.940 ;
        RECT 137.910 92.625 138.510 95.380 ;
        RECT 140.825 95.205 141.425 95.380 ;
        RECT 139.850 94.450 140.350 94.950 ;
        RECT 150.060 94.630 150.660 95.380 ;
        RECT 140.825 89.260 141.425 94.515 ;
        RECT 143.235 90.480 143.835 94.515 ;
        RECT 150.150 94.050 150.650 94.630 ;
        RECT 152.990 94.050 173.150 95.380 ;
        RECT 178.250 94.550 178.750 95.050 ;
        RECT 150.150 93.550 178.850 94.050 ;
        RECT 179.650 93.850 207.050 94.350 ;
        RECT 207.760 93.775 209.340 94.105 ;
        RECT 152.990 91.560 173.150 93.550 ;
        RECT 204.460 91.055 206.040 91.385 ;
        RECT 142.055 89.650 143.835 90.480 ;
        RECT 245.575 90.350 245.905 90.365 ;
        RECT 249.410 90.350 253.410 90.500 ;
        RECT 245.575 90.050 253.410 90.350 ;
        RECT 245.575 90.035 245.905 90.050 ;
        RECT 249.410 89.900 253.410 90.050 ;
        RECT 141.750 89.260 180.050 89.650 ;
        RECT 123.910 89.150 180.050 89.260 ;
        RECT 80.550 88.350 81.050 88.940 ;
        RECT 123.910 88.460 143.835 89.150 ;
        RECT 141.750 88.040 143.570 88.460 ;
        RECT 176.450 88.150 177.950 88.650 ;
        RECT 207.760 88.335 209.340 88.665 ;
        RECT 141.750 87.850 143.270 88.040 ;
        RECT 141.830 87.740 143.270 87.850 ;
        RECT 177.450 87.450 177.950 88.150 ;
        RECT 180.250 87.550 187.650 88.050 ;
        RECT 177.450 86.950 178.050 87.450 ;
        RECT 81.150 85.180 81.650 85.850 ;
        RECT 177.930 85.230 179.270 86.470 ;
        RECT 204.460 85.615 206.040 85.945 ;
        RECT 81.150 85.030 81.770 85.180 ;
        RECT 65.840 84.630 89.960 85.030 ;
        RECT 65.540 84.230 89.960 84.630 ;
        RECT 176.950 84.250 178.050 84.750 ;
        RECT 62.040 79.670 62.740 80.370 ;
        RECT 65.540 79.435 66.140 84.230 ;
        RECT 67.945 76.855 68.545 84.230 ;
        RECT 71.410 79.635 72.010 84.230 ;
        RECT 73.815 77.055 74.415 84.230 ;
        RECT 79.610 79.780 80.310 80.480 ;
        RECT 62.790 71.630 72.500 71.930 ;
        RECT 62.490 71.330 72.500 71.630 ;
        RECT 62.490 69.640 63.090 71.330 ;
        RECT 64.110 70.285 64.810 70.985 ;
        RECT 65.645 69.510 66.345 70.210 ;
        RECT 75.380 69.790 76.080 70.490 ;
        RECT 63.160 63.550 63.760 68.180 ;
        RECT 66.785 65.425 67.385 65.725 ;
        RECT 66.735 64.615 67.435 65.425 ;
        RECT 66.140 63.550 67.435 64.615 ;
        RECT 72.715 63.550 73.315 66.535 ;
        RECT 74.160 63.550 74.760 68.180 ;
        RECT 76.965 67.930 77.565 78.425 ;
        RECT 80.550 76.550 81.050 79.050 ;
        RECT 80.550 76.050 81.250 76.550 ;
        RECT 83.415 73.145 84.015 84.230 ;
        RECT 88.575 76.625 89.175 84.230 ;
        RECT 141.730 83.450 142.330 83.530 ;
        RECT 141.050 83.380 142.330 83.450 ;
        RECT 126.400 83.270 150.520 83.380 ;
        RECT 126.400 82.980 150.940 83.270 ;
        RECT 176.950 83.050 177.450 84.250 ;
        RECT 245.575 83.550 245.905 83.565 ;
        RECT 249.410 83.550 253.410 83.700 ;
        RECT 245.575 83.250 253.410 83.550 ;
        RECT 245.575 83.235 245.905 83.250 ;
        RECT 126.100 82.970 150.940 82.980 ;
        RECT 126.100 82.580 151.240 82.970 ;
        RECT 207.760 82.895 209.340 83.225 ;
        RECT 249.410 83.100 253.410 83.250 ;
        RECT 87.275 70.495 87.975 71.195 ;
        RECT 88.610 68.780 89.310 69.480 ;
        RECT 92.240 67.930 112.400 81.910 ;
        RECT 122.600 78.570 123.300 78.720 ;
        RECT 122.180 78.270 123.720 78.570 ;
        RECT 121.880 77.850 123.720 78.270 ;
        RECT 121.050 77.600 123.720 77.850 ;
        RECT 126.100 77.785 126.700 82.580 ;
        RECT 121.050 77.350 123.670 77.600 ;
        RECT 121.880 77.300 123.670 77.350 ;
        RECT 128.505 75.205 129.105 82.580 ;
        RECT 131.970 77.985 132.570 82.580 ;
        RECT 134.375 75.405 134.975 82.580 ;
        RECT 141.750 82.550 151.240 82.580 ;
        RECT 141.750 82.050 178.850 82.550 ;
        RECT 141.830 81.860 151.240 82.050 ;
        RECT 140.170 78.130 140.870 78.830 ;
        RECT 142.250 76.850 142.850 77.350 ;
        RECT 123.350 69.980 133.060 70.280 ;
        RECT 123.050 69.680 133.060 69.980 ;
        RECT 123.050 67.990 123.650 69.680 ;
        RECT 124.670 68.635 125.370 69.335 ;
        RECT 76.965 67.630 112.400 67.930 ;
        RECT 126.205 67.860 126.905 68.560 ;
        RECT 135.940 68.140 136.640 68.840 ;
        RECT 77.160 67.450 112.400 67.630 ;
        RECT 77.160 67.330 137.050 67.450 ;
        RECT 75.435 63.550 76.035 65.890 ;
        RECT 77.160 64.575 77.760 67.330 ;
        RECT 80.075 67.155 80.675 67.330 ;
        RECT 89.310 66.950 137.050 67.330 ;
        RECT 89.310 66.580 89.910 66.950 ;
        RECT 80.075 63.550 80.675 66.465 ;
        RECT 62.750 63.050 81.450 63.550 ;
        RECT 61.610 62.280 62.310 62.980 ;
        RECT 63.160 61.210 63.760 63.050 ;
        RECT 66.140 61.210 67.435 63.050 ;
        RECT 72.715 61.210 73.315 63.050 ;
        RECT 74.160 61.210 74.760 63.050 ;
        RECT 75.435 61.210 76.035 63.050 ;
        RECT 80.075 62.570 81.450 63.050 ;
        RECT 80.030 62.430 81.450 62.570 ;
        RECT 82.485 62.430 83.085 66.465 ;
        RECT 92.240 63.510 112.400 66.950 ;
        RECT 80.030 61.210 83.085 62.430 ;
        RECT 63.160 61.050 83.085 61.210 ;
        RECT 63.160 60.550 121.750 61.050 ;
        RECT 122.170 60.630 122.870 61.330 ;
        RECT 63.160 60.410 83.085 60.550 ;
        RECT 121.250 60.150 121.750 60.550 ;
        RECT 123.720 60.150 124.320 66.530 ;
        RECT 127.345 63.775 127.945 64.075 ;
        RECT 127.295 62.965 127.995 63.775 ;
        RECT 121.250 59.650 124.320 60.150 ;
        RECT 123.720 59.560 124.320 59.650 ;
        RECT 126.700 59.560 127.995 62.965 ;
        RECT 133.275 59.560 133.875 64.885 ;
        RECT 134.720 59.560 135.320 66.530 ;
        RECT 137.525 66.280 138.125 76.775 ;
        RECT 142.250 68.950 142.750 76.850 ;
        RECT 143.975 71.495 144.575 81.860 ;
        RECT 149.135 74.975 149.735 81.860 ;
        RECT 178.950 80.850 181.050 81.350 ;
        RECT 147.835 68.845 148.535 69.545 ;
        RECT 149.170 67.130 149.870 67.830 ;
        RECT 152.800 66.280 172.960 80.260 ;
        RECT 179.550 79.150 180.050 80.350 ;
        RECT 179.450 78.650 180.050 79.150 ;
        RECT 178.150 75.650 179.950 76.150 ;
        RECT 137.525 65.980 172.960 66.280 ;
        RECT 137.720 65.680 172.960 65.980 ;
        RECT 135.950 65.150 137.050 65.650 ;
        RECT 135.995 59.560 136.595 64.240 ;
        RECT 137.720 62.925 138.320 65.680 ;
        RECT 140.635 65.505 141.235 65.680 ;
        RECT 148.430 65.260 150.470 65.680 ;
        RECT 148.730 64.960 150.470 65.260 ;
        RECT 149.150 64.950 150.470 64.960 ;
        RECT 149.870 64.930 150.470 64.950 ;
        RECT 140.635 59.560 141.235 64.815 ;
        RECT 143.045 60.780 143.645 64.815 ;
        RECT 152.800 61.860 172.960 65.680 ;
        RECT 141.865 59.560 143.645 60.780 ;
        RECT 123.720 58.760 143.645 59.560 ;
        RECT 132.230 55.630 133.570 56.030 ;
        RECT 131.930 54.730 133.870 55.630 ;
        RECT 180.550 55.250 181.050 80.850 ;
        RECT 204.460 80.175 206.040 80.505 ;
        RECT 207.760 77.455 209.340 77.785 ;
        RECT 245.575 76.750 245.905 76.765 ;
        RECT 249.410 76.750 253.410 76.900 ;
        RECT 245.575 76.450 253.410 76.750 ;
        RECT 245.575 76.435 245.905 76.450 ;
        RECT 249.410 76.300 253.410 76.450 ;
        RECT 204.460 74.735 206.040 75.065 ;
        RECT 229.015 73.350 229.345 73.365 ;
        RECT 198.440 73.050 229.345 73.350 ;
        RECT 183.410 72.670 187.410 72.820 ;
        RECT 198.440 72.670 198.740 73.050 ;
        RECT 229.015 73.035 229.345 73.050 ;
        RECT 183.410 72.370 198.740 72.670 ;
        RECT 183.410 72.220 187.410 72.370 ;
        RECT 207.760 72.015 209.340 72.345 ;
        RECT 245.575 69.950 245.905 69.965 ;
        RECT 249.410 69.950 253.410 70.100 ;
        RECT 245.575 69.650 253.410 69.950 ;
        RECT 245.575 69.635 245.905 69.650 ;
        RECT 204.460 69.295 206.040 69.625 ;
        RECT 249.410 69.500 253.410 69.650 ;
        RECT 207.760 66.575 209.340 66.905 ;
        RECT 245.575 63.150 245.905 63.165 ;
        RECT 249.410 63.150 253.410 63.300 ;
        RECT 245.575 62.850 253.410 63.150 ;
        RECT 245.575 62.835 245.905 62.850 ;
        RECT 249.410 62.700 253.410 62.850 ;
        RECT 180.350 54.950 181.050 55.250 ;
        RECT 180.350 54.750 180.850 54.950 ;
        RECT 64.480 21.550 94.880 53.710 ;
        RECT 96.480 21.550 126.880 53.710 ;
        RECT 128.480 21.550 158.880 53.710 ;
        RECT 160.480 21.550 190.880 53.710 ;
        RECT 192.480 21.550 222.880 53.710 ;
        RECT 149.150 19.850 149.650 20.350 ;
        RECT 142.650 18.850 150.650 19.350 ;
        RECT 93.050 7.250 122.150 7.750 ;
        RECT 132.650 7.250 133.150 7.750 ;
        RECT 112.450 6.250 121.550 6.750 ;
      LAYER met4 ;
        RECT 30.970 224.760 33.430 225.260 ;
        RECT 33.730 224.760 36.190 225.260 ;
        RECT 36.490 224.760 38.950 225.260 ;
        RECT 39.250 224.760 41.710 225.260 ;
        RECT 42.010 224.760 44.470 225.260 ;
        RECT 44.770 224.760 47.230 225.260 ;
        RECT 47.530 224.760 49.990 225.260 ;
        RECT 50.290 224.760 52.750 225.260 ;
        RECT 53.050 224.760 55.510 225.260 ;
        RECT 55.810 224.760 58.270 225.260 ;
        RECT 58.570 224.760 61.030 225.260 ;
        RECT 61.330 224.760 63.790 225.260 ;
        RECT 64.090 224.760 66.550 225.260 ;
        RECT 66.850 224.760 69.310 225.260 ;
        RECT 69.610 224.760 72.070 225.260 ;
        RECT 72.370 224.760 74.830 225.260 ;
        RECT 75.130 224.760 77.590 225.260 ;
        RECT 77.890 224.760 80.350 225.260 ;
        RECT 80.650 224.760 83.110 225.260 ;
        RECT 83.410 224.760 85.870 225.260 ;
        RECT 86.170 224.760 88.630 225.260 ;
        RECT 88.930 224.760 91.390 225.260 ;
        RECT 91.690 224.760 94.150 225.260 ;
        RECT 94.450 224.760 94.550 225.260 ;
        RECT 94.050 221.750 94.550 224.760 ;
        RECT 141.070 145.250 141.370 224.760 ;
        RECT 143.830 145.250 144.130 224.760 ;
        RECT 140.950 144.750 141.470 145.250 ;
        RECT 143.730 144.750 144.250 145.250 ;
        RECT 53.100 128.550 53.350 129.050 ;
        RECT 53.100 113.150 80.550 113.650 ;
        RECT 103.150 112.350 103.650 119.450 ;
        RECT 103.150 111.850 113.950 112.350 ;
        RECT 110.550 110.950 112.950 111.350 ;
        RECT 91.250 110.850 112.950 110.950 ;
        RECT 91.250 110.450 111.050 110.850 ;
        RECT 91.250 109.950 91.750 110.450 ;
        RECT 78.250 109.450 91.750 109.950 ;
        RECT 61.650 108.750 62.350 108.900 ;
        RECT 78.250 108.750 78.750 109.450 ;
        RECT 61.650 108.250 78.750 108.750 ;
        RECT 60.650 92.450 61.150 97.950 ;
        RECT 60.250 91.950 61.150 92.450 ;
        RECT 60.250 56.150 60.750 91.950 ;
        RECT 61.650 91.510 62.350 108.250 ;
        RECT 62.850 99.650 63.350 101.450 ;
        RECT 64.070 100.910 75.340 101.260 ;
        RECT 63.720 100.560 75.690 100.910 ;
        RECT 63.720 99.650 64.420 100.560 ;
        RECT 62.850 99.150 66.950 99.650 ;
        RECT 63.720 98.815 64.420 99.150 ;
        RECT 66.450 98.950 66.950 99.150 ;
        RECT 74.990 98.950 75.690 100.560 ;
        RECT 78.250 98.950 78.750 100.650 ;
        RECT 65.255 97.010 65.955 98.740 ;
        RECT 66.450 98.450 75.690 98.950 ;
        RECT 76.100 98.450 78.750 98.950 ;
        RECT 74.990 98.320 75.690 98.450 ;
        RECT 75.050 97.450 75.550 97.950 ;
        RECT 79.220 97.010 79.920 109.010 ;
        RECT 92.245 101.590 109.855 110.045 ;
        RECT 87.235 101.240 109.855 101.590 ;
        RECT 86.885 100.890 109.855 101.240 ;
        RECT 86.885 99.025 87.585 100.890 ;
        RECT 88.220 97.010 88.920 98.010 ;
        RECT 65.255 96.660 88.920 97.010 ;
        RECT 65.605 96.310 88.570 96.660 ;
        RECT 61.220 91.160 62.350 91.510 ;
        RECT 61.220 90.810 62.250 91.160 ;
        RECT 61.750 80.370 62.250 90.810 ;
        RECT 88.250 81.450 88.750 95.650 ;
        RECT 92.245 92.435 109.855 100.890 ;
        RECT 111.510 92.100 111.990 110.380 ;
        RECT 112.450 108.350 112.950 110.850 ;
        RECT 113.450 109.350 113.950 111.850 ;
        RECT 140.950 110.850 141.450 144.750 ;
        RECT 143.750 111.850 144.250 144.750 ;
        RECT 143.750 111.350 175.050 111.850 ;
        RECT 140.950 110.350 174.050 110.850 ;
        RECT 113.450 108.850 124.450 109.350 ;
        RECT 122.790 108.350 123.490 108.420 ;
        RECT 112.450 107.850 123.490 108.350 ;
        RECT 122.790 91.030 123.490 107.850 ;
        RECT 123.950 98.750 124.450 108.850 ;
        RECT 125.210 100.430 136.480 100.780 ;
        RECT 124.860 100.080 136.830 100.430 ;
        RECT 124.860 99.250 125.560 100.080 ;
        RECT 124.860 98.750 128.050 99.250 ;
        RECT 124.860 98.335 125.560 98.750 ;
        RECT 127.550 98.450 128.050 98.750 ;
        RECT 136.130 98.450 136.830 100.080 ;
        RECT 126.395 96.530 127.095 98.260 ;
        RECT 127.550 97.950 136.830 98.450 ;
        RECT 136.130 97.840 136.830 97.950 ;
        RECT 136.250 96.950 136.750 97.440 ;
        RECT 140.360 96.530 141.060 108.530 ;
        RECT 153.385 101.110 170.995 109.565 ;
        RECT 148.375 100.760 170.995 101.110 ;
        RECT 148.025 100.410 170.995 100.760 ;
        RECT 148.025 98.545 148.725 100.410 ;
        RECT 149.360 96.530 150.060 97.530 ;
        RECT 126.395 96.180 150.060 96.530 ;
        RECT 126.745 95.830 149.710 96.180 ;
        RECT 139.850 94.450 141.550 94.950 ;
        RECT 122.360 90.680 123.490 91.030 ;
        RECT 122.360 90.330 123.350 90.680 ;
        RECT 78.650 80.950 88.750 81.450 ;
        RECT 61.750 79.750 62.740 80.370 ;
        RECT 62.040 62.980 62.740 79.750 ;
        RECT 64.460 72.380 75.730 72.730 ;
        RECT 64.110 72.030 76.080 72.380 ;
        RECT 64.110 70.285 64.810 72.030 ;
        RECT 75.380 70.350 76.080 72.030 ;
        RECT 78.650 70.350 79.150 80.950 ;
        RECT 65.645 68.480 66.345 70.210 ;
        RECT 75.380 69.850 79.150 70.350 ;
        RECT 75.380 69.790 76.080 69.850 ;
        RECT 79.610 68.480 80.310 80.480 ;
        RECT 92.635 73.060 110.245 81.515 ;
        RECT 87.625 72.710 110.245 73.060 ;
        RECT 87.275 72.360 110.245 72.710 ;
        RECT 87.275 70.495 87.975 72.360 ;
        RECT 88.610 68.480 89.310 69.480 ;
        RECT 65.645 68.130 89.310 68.480 ;
        RECT 65.995 67.780 88.960 68.130 ;
        RECT 92.635 63.905 110.245 72.360 ;
        RECT 111.900 63.570 112.380 81.850 ;
        RECT 122.850 78.720 123.350 90.330 ;
        RECT 141.050 82.950 141.550 94.450 ;
        RECT 153.385 91.955 170.995 100.410 ;
        RECT 172.650 91.620 173.130 109.900 ;
        RECT 173.550 108.150 174.050 110.350 ;
        RECT 174.550 109.150 175.050 111.350 ;
        RECT 174.550 108.650 186.650 109.150 ;
        RECT 173.550 107.650 185.650 108.150 ;
        RECT 178.250 87.750 178.750 95.050 ;
        RECT 178.250 87.250 178.850 87.750 ;
        RECT 178.350 86.470 178.850 87.250 ;
        RECT 177.930 85.230 179.270 86.470 ;
        RECT 178.350 81.150 178.850 85.230 ;
        RECT 171.550 80.850 178.850 81.150 ;
        RECT 152.250 80.650 178.850 80.850 ;
        RECT 152.250 80.350 172.050 80.650 ;
        RECT 152.250 79.750 152.750 80.350 ;
        RECT 122.600 78.150 123.350 78.720 ;
        RECT 139.250 79.250 152.750 79.750 ;
        RECT 61.610 62.630 62.740 62.980 ;
        RECT 61.610 62.280 62.390 62.630 ;
        RECT 122.600 61.330 123.300 78.150 ;
        RECT 125.020 70.730 136.290 71.080 ;
        RECT 124.670 70.380 136.640 70.730 ;
        RECT 124.670 68.635 125.370 70.380 ;
        RECT 135.940 68.750 136.640 70.380 ;
        RECT 139.250 68.750 139.750 79.250 ;
        RECT 126.205 66.830 126.905 68.560 ;
        RECT 135.940 68.250 139.750 68.750 ;
        RECT 135.940 68.140 136.640 68.250 ;
        RECT 140.170 66.830 140.870 78.830 ;
        RECT 153.195 71.410 170.805 79.865 ;
        RECT 148.185 71.060 170.805 71.410 ;
        RECT 147.835 70.710 170.805 71.060 ;
        RECT 147.835 68.845 148.535 70.710 ;
        RECT 149.170 66.830 149.870 67.830 ;
        RECT 126.205 66.480 149.870 66.830 ;
        RECT 126.555 66.130 149.520 66.480 ;
        RECT 136.550 65.150 140.550 65.650 ;
        RECT 122.170 60.980 123.300 61.330 ;
        RECT 122.170 60.630 122.950 60.980 ;
        RECT 59.050 55.650 60.750 56.150 ;
        RECT 59.050 54.250 59.550 55.650 ;
        RECT 132.650 55.150 133.150 55.950 ;
        RECT 140.050 55.150 140.550 65.150 ;
        RECT 153.195 62.255 170.805 70.710 ;
        RECT 172.460 61.920 172.940 80.200 ;
        RECT 186.150 72.750 186.650 108.650 ;
        RECT 204.450 88.050 206.050 113.220 ;
        RECT 206.550 90.150 207.050 94.350 ;
        RECT 207.750 90.150 209.350 113.220 ;
        RECT 206.550 89.650 264.400 90.150 ;
        RECT 187.150 87.550 206.050 88.050 ;
        RECT 185.150 72.250 186.650 72.750 ;
        RECT 204.450 66.500 206.050 87.550 ;
        RECT 207.750 66.500 209.350 89.650 ;
        RECT 180.350 55.210 180.850 55.250 ;
        RECT 142.680 55.200 180.850 55.210 ;
        RECT 142.650 55.150 180.850 55.200 ;
        RECT 132.650 54.690 180.850 55.150 ;
        RECT 132.650 54.650 143.180 54.690 ;
        RECT 59.050 53.750 62.650 54.250 ;
        RECT 62.150 36.950 62.650 53.750 ;
        RECT 142.680 53.710 143.180 54.650 ;
        RECT 63.680 53.190 223.680 53.710 ;
        RECT 64.875 37.010 94.485 51.555 ;
        RECT 96.875 37.010 126.485 51.555 ;
        RECT 128.875 37.010 158.485 51.555 ;
        RECT 160.875 37.010 190.485 51.555 ;
        RECT 192.875 37.010 222.485 51.555 ;
        RECT 63.680 36.950 223.680 37.010 ;
        RECT 62.150 36.490 223.680 36.950 ;
        RECT 62.150 36.450 158.485 36.490 ;
        RECT 64.875 21.945 94.485 36.450 ;
        RECT 96.875 21.945 126.485 36.450 ;
        RECT 128.875 21.945 158.485 36.450 ;
        RECT 160.875 21.945 190.485 36.490 ;
        RECT 192.875 21.945 222.485 36.490 ;
        RECT 142.650 18.850 143.150 21.945 ;
        RECT 251.150 21.350 251.650 63.250 ;
        RECT 148.150 20.850 251.650 21.350 ;
        RECT 148.150 9.750 148.650 20.850 ;
        RECT 130.650 9.250 148.650 9.750 ;
        RECT 130.650 8.750 131.150 9.250 ;
        RECT 149.150 8.750 149.650 20.350 ;
        RECT 73.750 8.250 131.150 8.750 ;
        RECT 131.650 8.250 149.650 8.750 ;
        RECT 73.750 7.750 74.250 8.250 ;
        RECT 131.650 7.750 132.150 8.250 ;
        RECT 150.150 7.750 150.650 19.350 ;
        RECT 55.410 7.250 74.250 7.750 ;
        RECT 74.730 7.250 93.550 7.750 ;
        RECT 94.050 7.250 112.850 7.750 ;
        RECT 113.350 7.250 132.150 7.750 ;
        RECT 132.650 7.250 133.190 7.750 ;
        RECT 150.150 7.250 152.550 7.750 ;
        RECT 55.410 1.000 55.910 7.250 ;
        RECT 74.730 1.000 75.230 7.250 ;
        RECT 94.050 1.000 94.550 7.250 ;
        RECT 112.350 6.750 112.850 7.250 ;
        RECT 112.350 6.250 112.950 6.750 ;
        RECT 113.370 1.000 113.870 7.250 ;
        RECT 132.690 1.000 133.190 7.250 ;
        RECT 152.010 1.000 152.510 7.250 ;
  END
END tt_um_p_sensing_ANG
END LIBRARY

